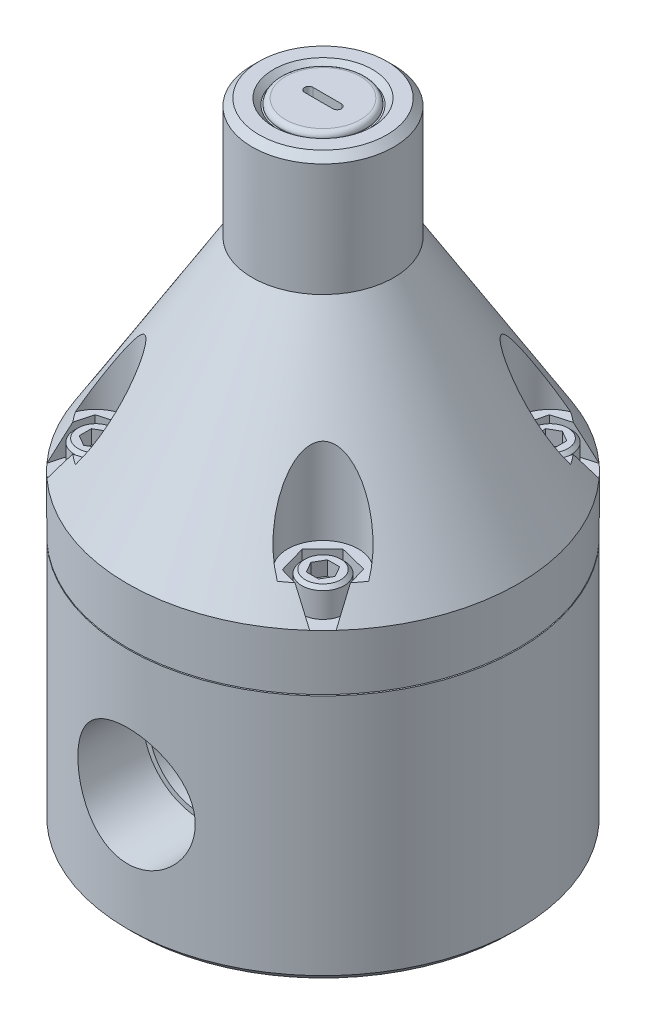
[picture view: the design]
ISO-10303-21;
HEADER;
FILE_DESCRIPTION(('STEP AP214'),'2;1');
FILE_NAME('part.step','',(''),(''),'','','');
FILE_SCHEMA(('AUTOMOTIVE_DESIGN { 1 0 10303 214 1 1 1 1 }'));
ENDSEC;
DATA;
#1=APPLICATION_CONTEXT('core data for automotive mechanical design processes');
#2=APPLICATION_PROTOCOL_DEFINITION('international standard','automotive_design',2000,#1);
#3=PRODUCT_CONTEXT('',#1,'mechanical');
#4=PRODUCT('Part','Part','',(#3));
#5=PRODUCT_RELATED_PRODUCT_CATEGORY('part','',(#4));
#6=PRODUCT_DEFINITION_FORMATION('','',#4);
#7=PRODUCT_DEFINITION_CONTEXT('part definition',#1,'design');
#8=PRODUCT_DEFINITION('design','',#6,#7);
#9=PRODUCT_DEFINITION_SHAPE('','',#8);
#10=(LENGTH_UNIT() NAMED_UNIT(*) SI_UNIT(.MILLI.,.METRE.));
#11=(NAMED_UNIT(*) PLANE_ANGLE_UNIT() SI_UNIT($,.RADIAN.));
#12=(NAMED_UNIT(*) SI_UNIT($,.STERADIAN.) SOLID_ANGLE_UNIT());
#13=UNCERTAINTY_MEASURE_WITH_UNIT(LENGTH_MEASURE(1.E-05),#10,'distance_accuracy_value','');
#14=(GEOMETRIC_REPRESENTATION_CONTEXT(3) GLOBAL_UNCERTAINTY_ASSIGNED_CONTEXT((#13)) GLOBAL_UNIT_ASSIGNED_CONTEXT((#10,
#11,#12)) REPRESENTATION_CONTEXT('',''));
#15=CARTESIAN_POINT('',(0.,0.,0.));
#16=DIRECTION('',(0.,0.,1.));
#17=DIRECTION('',(1.,0.,0.));
#18=AXIS2_PLACEMENT_3D('',#15,#16,#17);
#19=CARTESIAN_POINT('',(0.,68.58,0.));
#20=DIRECTION('',(0.,-1.,0.));
#21=DIRECTION('',(0.,0.,-1.));
#22=AXIS2_PLACEMENT_3D('',#19,#20,#21);
#23=CONICAL_SURFACE('',#22,43.815,0.551031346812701);
#24=CARTESIAN_POINT('',(31.1854504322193,74.9302,-24.909570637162));
#25=CARTESIAN_POINT('',(31.2917993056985,74.4052604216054,-25.2932994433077));
#26=CARTESIAN_POINT('',(31.3977224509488,73.8791142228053,-25.6754921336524));
#27=CARTESIAN_POINT('',(31.6087824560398,72.8246364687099,-26.4370404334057));
#28=CARTESIAN_POINT('',(31.713919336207,72.2963049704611,-26.8163961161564));
#29=CARTESIAN_POINT('',(31.9234771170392,71.2376591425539,-27.5725240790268));
#30=CARTESIAN_POINT('',(32.0278980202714,70.7073448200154,-27.9492963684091));
#31=CARTESIAN_POINT('',(32.2360838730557,69.6448927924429,-28.7004741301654));
#32=CARTESIAN_POINT('',(32.3398488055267,69.1127550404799,-29.0748795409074));
#33=CARTESIAN_POINT('',(32.443312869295,68.5798,-29.4481993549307));
#34=B_SPLINE_CURVE_WITH_KNOTS('',3,(#24,#25,#26,#27,#28,#29,#30,#31,#32,#33),.UNSPECIFIED.,.F.,
.F.,(4,2,2,2,4),(0.,1.97662629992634,3.95320132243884,5.9297692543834,7.90638844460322),.UNSPECIFIED.);
#35=CARTESIAN_POINT('',(31.1854909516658,74.93,-24.9097168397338));
#36=VERTEX_POINT('',#35);
#37=CARTESIAN_POINT('',(32.4432740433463,68.58,-29.4480592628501));
#38=VERTEX_POINT('',#37);
#39=EDGE_CURVE('E746',#36,#38,#34,.T.);
#40=ORIENTED_EDGE('',*,*,#39,.F.);
#41=CARTESIAN_POINT('',(0.,74.93,0.));
#42=DIRECTION('',(0.,1.,0.));
#43=DIRECTION('',(0.,0.,1.));
#44=AXIS2_PLACEMENT_3D('',#41,#42,#43);
#45=CIRCLE('',#44,39.9127653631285);
#46=CARTESIAN_POINT('',(32.8759602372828,74.93,-22.6318376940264));
#47=VERTEX_POINT('',#46);
#48=EDGE_CURVE('E1544',#36,#47,#45,.F.);
#49=ORIENTED_EDGE('',*,*,#48,.T.);
#50=CARTESIAN_POINT('',(32.8760134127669,74.9298,-22.6319772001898));
#51=CARTESIAN_POINT('',(32.8078201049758,75.1861952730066,-22.4531520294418));
#52=CARTESIAN_POINT('',(32.7341907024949,75.4445704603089,-22.2793275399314));
#53=CARTESIAN_POINT('',(32.5770087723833,75.9645959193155,-21.9414911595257));
#54=CARTESIAN_POINT('',(32.4934589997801,76.2262452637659,-21.7774765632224));
#55=CARTESIAN_POINT('',(32.3174500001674,76.7519681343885,-21.4591594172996));
#56=CARTESIAN_POINT('',(32.2250013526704,77.0160384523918,-21.3048456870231));
#57=CARTESIAN_POINT('',(32.0318436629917,77.5464258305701,-21.0055220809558));
#58=CARTESIAN_POINT('',(31.9311339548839,77.8127430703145,-20.8605129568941));
#59=CARTESIAN_POINT('',(31.6173532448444,78.6150033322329,-20.4388792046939));
#60=CARTESIAN_POINT('',(31.3928032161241,79.1537454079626,-20.1759549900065));
#61=CARTESIAN_POINT('',(30.9170512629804,80.2357477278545,-19.6857657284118));
#62=CARTESIAN_POINT('',(30.6658395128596,80.7790095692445,-19.458513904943));
#63=CARTESIAN_POINT('',(30.118158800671,81.9115352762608,-19.022517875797));
#64=CARTESIAN_POINT('',(29.8196739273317,82.5009764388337,-18.8167433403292));
#65=CARTESIAN_POINT('',(29.3524342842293,83.3846139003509,-18.5396319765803));
#66=CARTESIAN_POINT('',(29.1934054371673,83.6791250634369,-18.452507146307));
#67=CARTESIAN_POINT('',(28.8689346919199,84.2675878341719,-18.2889878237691));
#68=CARTESIAN_POINT('',(28.7034932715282,84.5615394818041,-18.2125925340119));
#69=CARTESIAN_POINT('',(28.3660149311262,85.1488284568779,-18.0707333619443));
#70=CARTESIAN_POINT('',(28.1939696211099,85.442164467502,-18.0052839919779));
#71=CARTESIAN_POINT('',(27.8434345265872,86.0273145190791,-17.885863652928));
#72=CARTESIAN_POINT('',(27.6649449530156,86.3191286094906,-17.8318923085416));
#73=CARTESIAN_POINT('',(27.3014619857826,86.9004622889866,-17.7360312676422));
#74=CARTESIAN_POINT('',(27.1164723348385,87.1899830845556,-17.6941347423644));
#75=CARTESIAN_POINT('',(26.7396312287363,87.7661102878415,-17.6231649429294));
#76=CARTESIAN_POINT('',(26.5477800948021,88.0527168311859,-17.5940910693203));
#77=CARTESIAN_POINT('',(26.1388486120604,88.6481794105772,-17.5477736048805));
#78=CARTESIAN_POINT('',(25.9210687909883,88.9566632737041,-17.531860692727));
#79=CARTESIAN_POINT('',(25.4761618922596,89.5671217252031,-17.5184250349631));
#80=CARTESIAN_POINT('',(25.2490377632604,89.8690983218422,-17.5208965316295));
#81=CARTESIAN_POINT('',(24.7853264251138,90.462861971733,-17.546770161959));
#82=CARTESIAN_POINT('',(24.5487844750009,90.7546875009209,-17.5700815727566));
#83=CARTESIAN_POINT('',(24.1854004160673,91.182662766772,-17.6234209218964));
#84=CARTESIAN_POINT('',(24.0628808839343,91.3236542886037,-17.6442539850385));
#85=CARTESIAN_POINT('',(23.8147710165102,91.6017141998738,-17.6926688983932));
#86=CARTESIAN_POINT('',(23.6891808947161,91.7387828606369,-17.7202502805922));
#87=CARTESIAN_POINT('',(23.3476505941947,92.1003741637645,-17.8043004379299));
#88=CARTESIAN_POINT('',(23.1286985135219,92.320550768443,-17.8676208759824));
#89=CARTESIAN_POINT('',(22.6802930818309,92.7420139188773,-18.0200246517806));
#90=CARTESIAN_POINT('',(22.450819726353,92.9432620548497,-18.1091589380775));
#91=CARTESIAN_POINT('',(22.0978320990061,93.2244666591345,-18.2671443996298));
#92=CARTESIAN_POINT('',(21.9777912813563,93.315346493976,-18.3243659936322));
#93=CARTESIAN_POINT('',(21.7355133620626,93.4877899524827,-18.4477596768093));
#94=CARTESIAN_POINT('',(21.6132758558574,93.5693518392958,-18.5139334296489));
#95=CARTESIAN_POINT('',(21.3676920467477,93.7206957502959,-18.6557254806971));
#96=CARTESIAN_POINT('',(21.2443516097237,93.7905207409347,-18.7313074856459));
#97=CARTESIAN_POINT('',(20.997270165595,93.9162293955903,-18.8925662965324));
#98=CARTESIAN_POINT('',(20.8735295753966,93.9721245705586,-18.9782346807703));
#99=CARTESIAN_POINT('',(20.596353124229,94.0793061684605,-19.1825009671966));
#100=CARTESIAN_POINT('',(20.4431915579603,94.1259831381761,-19.303987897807));
#101=CARTESIAN_POINT('',(20.1429486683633,94.1891665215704,-19.561379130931));
#102=CARTESIAN_POINT('',(19.995862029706,94.2056998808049,-19.6972704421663));
#103=CARTESIAN_POINT('',(19.7121854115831,94.2068511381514,-19.9801670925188));
#104=CARTESIAN_POINT('',(19.5756118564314,94.1914201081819,-20.1271891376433));
#105=CARTESIAN_POINT('',(19.3168358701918,94.130256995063,-20.4274436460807));
#106=CARTESIAN_POINT('',(19.1946462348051,94.0844981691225,-20.5806814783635));
#107=CARTESIAN_POINT('',(18.9333227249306,93.9499537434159,-20.9335168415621));
#108=CARTESIAN_POINT('',(18.7994959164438,93.8525556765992,-21.1337148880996));
#109=CARTESIAN_POINT('',(18.5575341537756,93.6253225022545,-21.5311982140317));
#110=CARTESIAN_POINT('',(18.4494578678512,93.4954146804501,-21.7284758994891));
#111=CARTESIAN_POINT('',(18.2734255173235,93.2378861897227,-22.0822323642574));
#112=CARTESIAN_POINT('',(18.2017503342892,93.114033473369,-22.2396830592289));
#113=CARTESIAN_POINT('',(18.0717731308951,92.8543658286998,-22.5502860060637));
#114=CARTESIAN_POINT('',(18.0134803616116,92.7185427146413,-22.7034352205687));
#115=CARTESIAN_POINT('',(17.9085459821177,92.4375711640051,-23.0055063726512));
#116=CARTESIAN_POINT('',(17.8619238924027,92.2924076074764,-23.1544208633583));
#117=CARTESIAN_POINT('',(17.7789950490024,91.9949331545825,-23.4479825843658));
#118=CARTESIAN_POINT('',(17.7426923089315,91.842619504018,-23.5926281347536));
#119=CARTESIAN_POINT('',(17.6793668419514,91.5330276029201,-23.877261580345));
#120=CARTESIAN_POINT('',(17.6523073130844,91.3757718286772,-24.0172658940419));
#121=CARTESIAN_POINT('',(17.6063247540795,91.0568516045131,-24.2934532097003));
#122=CARTESIAN_POINT('',(17.5874006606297,90.8951877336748,-24.4296367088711));
#123=CARTESIAN_POINT('',(17.5416007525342,90.4045581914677,-24.8331155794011));
#124=CARTESIAN_POINT('',(17.5257415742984,90.0701857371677,-25.0951300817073));
#125=CARTESIAN_POINT('',(17.5187750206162,89.3910127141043,-25.6073018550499));
#126=CARTESIAN_POINT('',(17.5277362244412,89.0461858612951,-25.8574243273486));
#127=CARTESIAN_POINT('',(17.5674604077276,88.3499543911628,-26.346266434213));
#128=CARTESIAN_POINT('',(17.5982177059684,87.9985515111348,-26.5849890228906));
#129=CARTESIAN_POINT('',(17.6752315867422,87.3273950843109,-27.0279886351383));
#130=CARTESIAN_POINT('',(17.7195760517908,87.0080899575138,-27.2332880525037));
#131=CARTESIAN_POINT('',(17.8230232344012,86.366765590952,-27.6358491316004));
#132=CARTESIAN_POINT('',(17.8821279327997,86.0447459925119,-27.8331097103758));
#133=CARTESIAN_POINT('',(18.0143479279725,85.3986613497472,-28.2199078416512));
#134=CARTESIAN_POINT('',(18.0874725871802,85.0745950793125,-28.4094401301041));
#135=CARTESIAN_POINT('',(18.247146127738,84.4253288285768,-28.7807004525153));
#136=CARTESIAN_POINT('',(18.3336943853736,84.100128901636,-28.9624288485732));
#137=CARTESIAN_POINT('',(18.5196821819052,83.4497138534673,-29.3177238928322));
#138=CARTESIAN_POINT('',(18.6190998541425,83.1244996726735,-29.4913037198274));
#139=CARTESIAN_POINT('',(18.8307065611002,82.4740292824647,-29.830436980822));
#140=CARTESIAN_POINT('',(18.9428959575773,82.1487730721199,-29.9959901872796));
#141=CARTESIAN_POINT('',(19.1798765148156,81.4988617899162,-30.3186806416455));
#142=CARTESIAN_POINT('',(19.3046623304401,81.1742065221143,-30.4758214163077));
#143=CARTESIAN_POINT('',(19.566846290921,80.5258852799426,-30.7813029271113));
#144=CARTESIAN_POINT('',(19.7042435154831,80.2022192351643,-30.929644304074));
#145=CARTESIAN_POINT('',(20.0356080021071,79.4577845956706,-31.2608218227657));
#146=CARTESIAN_POINT('',(20.2340425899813,79.0375277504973,-31.4403688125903));
#147=CARTESIAN_POINT('',(20.6528330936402,78.2009180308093,-31.7817933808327));
#148=CARTESIAN_POINT('',(20.8731810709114,77.7845638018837,-31.943677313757));
#149=CARTESIAN_POINT('',(21.2204706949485,77.1642648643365,-32.1715277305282));
#150=CARTESIAN_POINT('',(21.3389735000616,76.9582923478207,-32.244953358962));
#151=CARTESIAN_POINT('',(21.5816967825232,76.5479021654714,-32.3865049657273));
#152=CARTESIAN_POINT('',(21.7059169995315,76.3434844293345,-32.454631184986));
#153=CARTESIAN_POINT('',(21.9602864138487,75.936277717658,-32.5852592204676));
#154=CARTESIAN_POINT('',(22.0904406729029,75.7334903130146,-32.647756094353));
#155=CARTESIAN_POINT('',(22.3567119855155,75.3299985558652,-32.7666088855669));
#156=CARTESIAN_POINT('',(22.4928299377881,75.1292945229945,-32.8229638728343));
#157=CARTESIAN_POINT('',(22.6319772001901,74.9298,-32.8760134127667));
#158=B_SPLINE_CURVE_WITH_KNOTS('',3,(#50,#51,#52,#53,#54,#55,#56,#57,#58,#59,#60,#61,#62,#63,
#64,#65,#66,#67,#68,#69,#70,#71,#72,#73,#74,#75,#76,#77,#78,#79,#80,#81,#82,#83,#84,#85,#86,#87,
#88,#89,#90,#91,#92,#93,#94,#95,#96,#97,#98,#99,#100,#101,#102,#103,#104,#105,#106,#107,#108,
#109,#110,#111,#112,#113,#114,#115,#116,#117,#118,#119,#120,#121,#122,#123,#124,#125,#126,#127,
#128,#129,#130,#131,#132,#133,#134,#135,#136,#137,#138,#139,#140,#141,#142,#143,#144,#145,#146,
#147,#148,#149,#150,#151,#152,#153,#154,#155,#156,#157),.UNSPECIFIED.,.F.,.F.,(4,2,2,2,2,2,2,2,
2,2,2,2,2,2,2,2,2,2,2,2,2,2,2,2,2,2,2,2,2,2,2,2,2,2,2,2,2,2,2,2,2,2,2,2,2,2,2,2,2,2,2,2,2,4),
(0.,0.959681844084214,1.9190977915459,2.87738689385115,3.83575332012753,5.75433905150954,
7.67363431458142,9.74768208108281,10.7850777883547,11.8223963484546,12.8610794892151,
13.8997286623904,14.9377892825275,15.9758013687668,17.1090815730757,18.2420068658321,
19.3700240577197,19.9337037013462,20.4973442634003,21.4467185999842,22.3979796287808,
22.8807596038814,23.363629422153,23.8446911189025,24.3253539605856,24.9256472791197,
25.5254037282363,26.1260789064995,26.7272844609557,27.5022221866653,28.2789089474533,
28.9163059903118,29.5541423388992,30.193038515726,30.8321828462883,31.4687519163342,
32.1052377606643,33.3791509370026,34.6565874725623,35.9336911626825,37.0798743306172,
38.2262114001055,39.3733166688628,40.520368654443,41.665496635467,42.8106570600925,
43.9553335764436,45.0999266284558,46.5938371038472,48.0872083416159,48.8332472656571,
49.5792522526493,50.325905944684,51.0726725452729),.UNSPECIFIED.);
#159=CARTESIAN_POINT('',(22.6318376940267,74.93,-32.8759602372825));
#160=VERTEX_POINT('',#159);
#161=EDGE_CURVE('E897',#47,#160,#158,.T.);
#162=ORIENTED_EDGE('',*,*,#161,.T.);
#163=CARTESIAN_POINT('',(24.9752922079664,74.93,-31.1329988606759));
#164=VERTEX_POINT('',#163);
#165=EDGE_CURVE('E906',#160,#164,#45,.F.);
#166=ORIENTED_EDGE('',*,*,#165,.T.);
#167=CARTESIAN_POINT('',(29.4766640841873,68.5798,-32.4174531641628));
#168=CARTESIAN_POINT('',(29.1062316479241,69.1125841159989,-32.3117512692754));
#169=CARTESIAN_POINT('',(28.7347583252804,69.6445870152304,-32.2057523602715));
#170=CARTESIAN_POINT('',(27.9895431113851,70.7068520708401,-31.9931072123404));
#171=CARTESIAN_POINT('',(27.6158012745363,71.2371142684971,-31.8864609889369));
#172=CARTESIAN_POINT('',(26.8658433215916,72.2957468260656,-31.6724625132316));
#173=CARTESIAN_POINT('',(26.4896271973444,72.8241171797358,-31.5651102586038));
#174=CARTESIAN_POINT('',(25.7344797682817,73.8787747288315,-31.3496309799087));
#175=CARTESIAN_POINT('',(25.3555483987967,74.4050618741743,-31.2415039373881));
#176=CARTESIAN_POINT('',(24.9751473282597,74.9302,-31.132957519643));
#177=B_SPLINE_CURVE_WITH_KNOTS('',3,(#167,#168,#169,#170,#171,#172,#173,#174,#175,#176),
.UNSPECIFIED.,.F.,.F.,(4,2,2,2,4),(0.,1.97237650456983,3.9447058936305,5.91704178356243,
7.88942480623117),.UNSPECIFIED.);
#178=CARTESIAN_POINT('',(29.4765250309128,68.58,-32.4174134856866));
#179=VERTEX_POINT('',#178);
#180=EDGE_CURVE('E729',#179,#164,#177,.T.);
#181=ORIENTED_EDGE('',*,*,#180,.F.);
#182=CARTESIAN_POINT('',(0.,68.58,0.));
#183=DIRECTION('',(0.,-1.,0.));
#184=DIRECTION('',(0.,0.,-1.));
#185=AXIS2_PLACEMENT_3D('',#182,#183,#184);
#186=CIRCLE('',#185,43.815);
#187=CARTESIAN_POINT('',(-29.4480592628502,68.58,-32.4432740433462));
#188=VERTEX_POINT('',#187);
#189=EDGE_CURVE('E1308',#188,#179,#186,.T.);
#190=ORIENTED_EDGE('',*,*,#189,.F.);
#191=CARTESIAN_POINT('',(-24.9095706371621,74.9302,-31.1854504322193));
#192=CARTESIAN_POINT('',(-25.2932994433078,74.4052604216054,-31.2917993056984));
#193=CARTESIAN_POINT('',(-25.6754921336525,73.8791142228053,-31.3977224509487));
#194=CARTESIAN_POINT('',(-26.4370404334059,72.8246364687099,-31.6087824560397));
#195=CARTESIAN_POINT('',(-26.8163961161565,72.2963049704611,-31.7139193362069));
#196=CARTESIAN_POINT('',(-27.5725240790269,71.2376591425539,-31.9234771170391));
#197=CARTESIAN_POINT('',(-27.9492963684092,70.7073448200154,-32.0278980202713));
#198=CARTESIAN_POINT('',(-28.7004741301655,69.6448927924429,-32.2360838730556));
#199=CARTESIAN_POINT('',(-29.0748795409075,69.1127550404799,-32.3398488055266));
#200=CARTESIAN_POINT('',(-29.4481993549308,68.5798,-32.4433128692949));
#201=B_SPLINE_CURVE_WITH_KNOTS('',3,(#191,#192,#193,#194,#195,#196,#197,#198,#199,#200),
.UNSPECIFIED.,.F.,.F.,(4,2,2,2,4),(0.,1.97662629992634,3.95320132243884,5.9297692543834,
7.90638844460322),.UNSPECIFIED.);
#202=CARTESIAN_POINT('',(-24.9097168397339,74.93,-31.1854909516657));
#203=VERTEX_POINT('',#202);
#204=EDGE_CURVE('E803',#203,#188,#201,.T.);
#205=ORIENTED_EDGE('',*,*,#204,.F.);
#206=CARTESIAN_POINT('',(0.,74.93,0.));
#207=DIRECTION('',(0.,1.,0.));
#208=DIRECTION('',(0.,0.,1.));
#209=AXIS2_PLACEMENT_3D('',#206,#207,#208);
#210=CIRCLE('',#209,39.9127653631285);
#211=CARTESIAN_POINT('',(-22.6318376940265,74.93,-32.8759602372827));
#212=VERTEX_POINT('',#211);
#213=EDGE_CURVE('E1676',#203,#212,#210,.F.);
#214=ORIENTED_EDGE('',*,*,#213,.T.);
#215=CARTESIAN_POINT('',(-22.6319772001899,74.9298,-32.8760134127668));
#216=CARTESIAN_POINT('',(-22.4531520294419,75.1861952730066,-32.8078201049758));
#217=CARTESIAN_POINT('',(-22.2793275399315,75.4445704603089,-32.7341907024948));
#218=CARTESIAN_POINT('',(-21.9414911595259,75.9645959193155,-32.5770087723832));
#219=CARTESIAN_POINT('',(-21.7774765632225,76.2262452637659,-32.49345899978));
#220=CARTESIAN_POINT('',(-21.4591594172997,76.7519681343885,-32.3174500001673));
#221=CARTESIAN_POINT('',(-21.3048456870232,77.0160384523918,-32.2250013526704));
#222=CARTESIAN_POINT('',(-21.0055220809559,77.5464258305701,-32.0318436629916));
#223=CARTESIAN_POINT('',(-20.8605129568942,77.8127430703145,-31.9311339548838));
#224=CARTESIAN_POINT('',(-20.438879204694,78.6150033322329,-31.6173532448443));
#225=CARTESIAN_POINT('',(-20.1759549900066,79.1537454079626,-31.392803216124));
#226=CARTESIAN_POINT('',(-19.6857657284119,80.2357477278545,-30.9170512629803));
#227=CARTESIAN_POINT('',(-19.4585139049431,80.7790095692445,-30.6658395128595));
#228=CARTESIAN_POINT('',(-19.0225178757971,81.9115352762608,-30.1181588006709));
#229=CARTESIAN_POINT('',(-18.8167433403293,82.5009764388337,-29.8196739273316));
#230=CARTESIAN_POINT('',(-18.5396319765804,83.3846139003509,-29.3524342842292));
#231=CARTESIAN_POINT('',(-18.4525071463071,83.6791250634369,-29.1934054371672));
#232=CARTESIAN_POINT('',(-18.2889878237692,84.2675878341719,-28.8689346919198));
#233=CARTESIAN_POINT('',(-18.212592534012,84.5615394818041,-28.7034932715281));
#234=CARTESIAN_POINT('',(-18.0707333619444,85.148828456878,-28.3660149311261));
#235=CARTESIAN_POINT('',(-18.005283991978,85.4421644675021,-28.1939696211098));
#236=CARTESIAN_POINT('',(-17.8858636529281,86.0273145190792,-27.8434345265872));
#237=CARTESIAN_POINT('',(-17.8318923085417,86.3191286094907,-27.6649449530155));
#238=CARTESIAN_POINT('',(-17.7360312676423,86.9004622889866,-27.3014619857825));
#239=CARTESIAN_POINT('',(-17.6941347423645,87.1899830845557,-27.1164723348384));
#240=CARTESIAN_POINT('',(-17.6231649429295,87.7661102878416,-26.7396312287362));
#241=CARTESIAN_POINT('',(-17.5940910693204,88.052716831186,-26.547780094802));
#242=CARTESIAN_POINT('',(-17.5477736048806,88.6481794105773,-26.1388486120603));
#243=CARTESIAN_POINT('',(-17.5318606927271,88.9566632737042,-25.9210687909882));
#244=CARTESIAN_POINT('',(-17.5184250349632,89.5671217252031,-25.4761618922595));
#245=CARTESIAN_POINT('',(-17.5208965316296,89.8690983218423,-25.2490377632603));
#246=CARTESIAN_POINT('',(-17.5467701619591,90.462861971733,-24.7853264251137));
#247=CARTESIAN_POINT('',(-17.5700815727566,90.754687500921,-24.5487844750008));
#248=CARTESIAN_POINT('',(-17.6234209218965,91.1826627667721,-24.1854004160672));
#249=CARTESIAN_POINT('',(-17.6442539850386,91.3236542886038,-24.0628808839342));
#250=CARTESIAN_POINT('',(-17.6926688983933,91.6017141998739,-23.8147710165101));
#251=CARTESIAN_POINT('',(-17.7202502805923,91.7387828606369,-23.6891808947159));
#252=CARTESIAN_POINT('',(-17.80430043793,92.1003741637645,-23.3476505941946));
#253=CARTESIAN_POINT('',(-17.8676208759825,92.320550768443,-23.1286985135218));
#254=CARTESIAN_POINT('',(-18.0200246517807,92.7420139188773,-22.6802930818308));
#255=CARTESIAN_POINT('',(-18.1091589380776,92.9432620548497,-22.4508197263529));
#256=CARTESIAN_POINT('',(-18.2671443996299,93.2244666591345,-22.097832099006));
#257=CARTESIAN_POINT('',(-18.3243659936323,93.3153464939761,-21.9777912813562));
#258=CARTESIAN_POINT('',(-18.4477596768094,93.4877899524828,-21.7355133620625));
#259=CARTESIAN_POINT('',(-18.513933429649,93.5693518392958,-21.6132758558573));
#260=CARTESIAN_POINT('',(-18.6557254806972,93.7206957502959,-21.3676920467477));
#261=CARTESIAN_POINT('',(-18.731307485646,93.7905207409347,-21.2443516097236));
#262=CARTESIAN_POINT('',(-18.8925662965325,93.9162293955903,-20.9972701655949));
#263=CARTESIAN_POINT('',(-18.9782346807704,93.9721245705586,-20.8735295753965));
#264=CARTESIAN_POINT('',(-19.1825009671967,94.0793061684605,-20.5963531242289));
#265=CARTESIAN_POINT('',(-19.3039878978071,94.1259831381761,-20.4431915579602));
#266=CARTESIAN_POINT('',(-19.5613791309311,94.1891665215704,-20.1429486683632));
#267=CARTESIAN_POINT('',(-19.6972704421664,94.2056998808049,-19.9958620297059));
#268=CARTESIAN_POINT('',(-19.9801670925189,94.2068511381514,-19.7121854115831));
#269=CARTESIAN_POINT('',(-20.1271891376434,94.1914201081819,-19.5756118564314));
#270=CARTESIAN_POINT('',(-20.4274436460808,94.130256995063,-19.3168358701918));
#271=CARTESIAN_POINT('',(-20.5806814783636,94.0844981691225,-19.194646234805));
#272=CARTESIAN_POINT('',(-20.9335168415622,93.9499537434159,-18.9333227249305));
#273=CARTESIAN_POINT('',(-21.1337148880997,93.8525556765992,-18.7994959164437));
#274=CARTESIAN_POINT('',(-21.5311982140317,93.6253225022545,-18.5575341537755));
#275=CARTESIAN_POINT('',(-21.7284758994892,93.4954146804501,-18.4494578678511));
#276=CARTESIAN_POINT('',(-22.0822323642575,93.2378861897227,-18.2734255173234));
#277=CARTESIAN_POINT('',(-22.239683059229,93.114033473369,-18.2017503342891));
#278=CARTESIAN_POINT('',(-22.5502860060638,92.8543658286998,-18.071773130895));
#279=CARTESIAN_POINT('',(-22.7034352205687,92.7185427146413,-18.0134803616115));
#280=CARTESIAN_POINT('',(-23.0055063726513,92.437571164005,-17.9085459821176));
#281=CARTESIAN_POINT('',(-23.1544208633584,92.2924076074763,-17.8619238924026));
#282=CARTESIAN_POINT('',(-23.4479825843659,91.9949331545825,-17.7789950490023));
#283=CARTESIAN_POINT('',(-23.5926281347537,91.842619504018,-17.7426923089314));
#284=CARTESIAN_POINT('',(-23.8772615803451,91.5330276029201,-17.6793668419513));
#285=CARTESIAN_POINT('',(-24.017265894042,91.3757718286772,-17.6523073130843));
#286=CARTESIAN_POINT('',(-24.2934532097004,91.0568516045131,-17.6063247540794));
#287=CARTESIAN_POINT('',(-24.4296367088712,90.8951877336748,-17.5874006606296));
#288=CARTESIAN_POINT('',(-24.8331155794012,90.4045581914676,-17.5416007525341));
#289=CARTESIAN_POINT('',(-25.0951300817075,90.0701857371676,-17.5257415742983));
#290=CARTESIAN_POINT('',(-25.60730185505,89.3910127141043,-17.5187750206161));
#291=CARTESIAN_POINT('',(-25.8574243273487,89.046185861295,-17.5277362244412));
#292=CARTESIAN_POINT('',(-26.3462664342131,88.3499543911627,-17.5674604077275));
#293=CARTESIAN_POINT('',(-26.5849890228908,87.9985515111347,-17.5982177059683));
#294=CARTESIAN_POINT('',(-27.0279886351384,87.3273950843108,-17.6752315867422));
#295=CARTESIAN_POINT('',(-27.2332880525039,87.0080899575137,-17.7195760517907));
#296=CARTESIAN_POINT('',(-27.6358491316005,86.366765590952,-17.8230232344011));
#297=CARTESIAN_POINT('',(-27.8331097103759,86.0447459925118,-17.8821279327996));
#298=CARTESIAN_POINT('',(-28.2199078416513,85.3986613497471,-18.0143479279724));
#299=CARTESIAN_POINT('',(-28.4094401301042,85.0745950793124,-18.0874725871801));
#300=CARTESIAN_POINT('',(-28.7807004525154,84.4253288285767,-18.2471461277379));
#301=CARTESIAN_POINT('',(-28.9624288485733,84.1001289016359,-18.3336943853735));
#302=CARTESIAN_POINT('',(-29.3177238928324,83.4497138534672,-18.5196821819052));
#303=CARTESIAN_POINT('',(-29.4913037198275,83.1244996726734,-18.6190998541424));
#304=CARTESIAN_POINT('',(-29.8304369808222,82.4740292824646,-18.8307065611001));
#305=CARTESIAN_POINT('',(-29.9959901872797,82.1487730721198,-18.9428959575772));
#306=CARTESIAN_POINT('',(-30.3186806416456,81.498861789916,-19.1798765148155));
#307=CARTESIAN_POINT('',(-30.4758214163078,81.1742065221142,-19.3046623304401));
#308=CARTESIAN_POINT('',(-30.7813029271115,80.5258852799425,-19.5668462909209));
#309=CARTESIAN_POINT('',(-30.9296443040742,80.2022192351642,-19.7042435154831));
#310=CARTESIAN_POINT('',(-31.2608218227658,79.4577845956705,-20.0356080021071));
#311=CARTESIAN_POINT('',(-31.4403688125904,79.0375277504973,-20.2340425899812));
#312=CARTESIAN_POINT('',(-31.7817933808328,78.2009180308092,-20.6528330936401));
#313=CARTESIAN_POINT('',(-31.9436773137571,77.7845638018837,-20.8731810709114));
#314=CARTESIAN_POINT('',(-32.1715277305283,77.1642648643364,-21.2204706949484));
#315=CARTESIAN_POINT('',(-32.2449533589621,76.9582923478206,-21.3389735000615));
#316=CARTESIAN_POINT('',(-32.3865049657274,76.5479021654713,-21.5816967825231));
#317=CARTESIAN_POINT('',(-32.4546311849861,76.3434844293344,-21.7059169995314));
#318=CARTESIAN_POINT('',(-32.5852592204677,75.9362777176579,-21.9602864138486));
#319=CARTESIAN_POINT('',(-32.6477560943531,75.7334903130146,-22.0904406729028));
#320=CARTESIAN_POINT('',(-32.766608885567,75.3299985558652,-22.3567119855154));
#321=CARTESIAN_POINT('',(-32.8229638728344,75.1292945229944,-22.492829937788));
#322=CARTESIAN_POINT('',(-32.8760134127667,74.9298,-22.63197720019));
#323=B_SPLINE_CURVE_WITH_KNOTS('',3,(#215,#216,#217,#218,#219,#220,#221,#222,#223,#224,#225,
#226,#227,#228,#229,#230,#231,#232,#233,#234,#235,#236,#237,#238,#239,#240,#241,#242,#243,#244,
#245,#246,#247,#248,#249,#250,#251,#252,#253,#254,#255,#256,#257,#258,#259,#260,#261,#262,#263,
#264,#265,#266,#267,#268,#269,#270,#271,#272,#273,#274,#275,#276,#277,#278,#279,#280,#281,#282,
#283,#284,#285,#286,#287,#288,#289,#290,#291,#292,#293,#294,#295,#296,#297,#298,#299,#300,#301,
#302,#303,#304,#305,#306,#307,#308,#309,#310,#311,#312,#313,#314,#315,#316,#317,#318,#319,#320,
#321,#322),.UNSPECIFIED.,.F.,.F.,(4,2,2,2,2,2,2,2,2,2,2,2,2,2,2,2,2,2,2,2,2,2,2,2,2,2,2,2,2,2,2,
2,2,2,2,2,2,2,2,2,2,2,2,2,2,2,2,2,2,2,2,2,2,4),(0.,0.959681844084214,1.9190977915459,
2.87738689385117,3.83575332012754,5.75433905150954,7.67363431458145,9.74768208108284,
10.7850777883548,11.8223963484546,12.8610794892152,13.8997286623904,14.9377892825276,
15.9758013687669,17.1090815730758,18.2420068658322,19.3700240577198,19.9337037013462,
20.4973442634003,21.4467185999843,22.3979796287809,22.8807596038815,23.3636294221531,
23.8446911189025,24.3253539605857,24.9256472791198,25.5254037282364,26.1260789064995,
26.7272844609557,27.5022221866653,28.2789089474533,28.9163059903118,29.5541423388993,
30.193038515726,30.8321828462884,31.4687519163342,32.1052377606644,33.3791509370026,
34.6565874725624,35.9336911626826,37.0798743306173,38.2262114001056,39.373316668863,
40.5203686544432,41.6654966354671,42.8106570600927,43.9553335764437,45.0999266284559,
46.5938371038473,48.0872083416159,48.8332472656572,49.5792522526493,50.3259059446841,
51.0726725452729),.UNSPECIFIED.);
#324=CARTESIAN_POINT('',(-32.8759602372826,74.93,-22.6318376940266));
#325=VERTEX_POINT('',#324);
#326=EDGE_CURVE('E1545',#212,#325,#323,.T.);
#327=ORIENTED_EDGE('',*,*,#326,.T.);
#328=CARTESIAN_POINT('',(-31.132998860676,74.93,-24.9752922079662));
#329=VERTEX_POINT('',#328);
#330=EDGE_CURVE('E1359',#325,#329,#210,.F.);
#331=ORIENTED_EDGE('',*,*,#330,.T.);
#332=CARTESIAN_POINT('',(-32.4174531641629,68.5798,-29.4766640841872));
#333=CARTESIAN_POINT('',(-32.3117512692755,69.1125841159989,-29.106231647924));
#334=CARTESIAN_POINT('',(-32.2057523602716,69.6445870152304,-28.7347583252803));
#335=CARTESIAN_POINT('',(-31.9931072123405,70.7068520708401,-27.989543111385));
#336=CARTESIAN_POINT('',(-31.886460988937,71.2371142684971,-27.6158012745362));
#337=CARTESIAN_POINT('',(-31.6724625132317,72.2957468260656,-26.8658433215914));
#338=CARTESIAN_POINT('',(-31.5651102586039,72.8241171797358,-26.4896271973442));
#339=CARTESIAN_POINT('',(-31.3496309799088,73.8787747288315,-25.7344797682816));
#340=CARTESIAN_POINT('',(-31.2415039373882,74.4050618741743,-25.3555483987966));
#341=CARTESIAN_POINT('',(-31.1329575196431,74.9302,-24.9751473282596));
#342=B_SPLINE_CURVE_WITH_KNOTS('',3,(#332,#333,#334,#335,#336,#337,#338,#339,#340,#341),
.UNSPECIFIED.,.F.,.F.,(4,2,2,2,4),(0.,1.9723765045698,3.94470589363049,5.91704178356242,
7.88942480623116),.UNSPECIFIED.);
#343=CARTESIAN_POINT('',(-32.4174134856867,68.58,-29.4765250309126));
#344=VERTEX_POINT('',#343);
#345=EDGE_CURVE('E796',#344,#329,#342,.T.);
#346=ORIENTED_EDGE('',*,*,#345,.F.);
#347=CARTESIAN_POINT('',(-32.4432740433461,68.58,29.4480592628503));
#348=VERTEX_POINT('',#347);
#349=EDGE_CURVE('E1315',#348,#344,#186,.T.);
#350=ORIENTED_EDGE('',*,*,#349,.F.);
#351=CARTESIAN_POINT('',(-31.1854504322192,74.9302,24.9095706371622));
#352=CARTESIAN_POINT('',(-31.2917993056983,74.4052604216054,25.2932994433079));
#353=CARTESIAN_POINT('',(-31.3977224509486,73.8791142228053,25.6754921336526));
#354=CARTESIAN_POINT('',(-31.6087824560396,72.8246364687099,26.437040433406));
#355=CARTESIAN_POINT('',(-31.7139193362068,72.2963049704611,26.8163961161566));
#356=CARTESIAN_POINT('',(-31.9234771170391,71.2376591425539,27.572524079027));
#357=CARTESIAN_POINT('',(-32.0278980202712,70.7073448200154,27.9492963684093));
#358=CARTESIAN_POINT('',(-32.2360838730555,69.6448927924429,28.7004741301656));
#359=CARTESIAN_POINT('',(-32.3398488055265,69.1127550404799,29.0748795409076));
#360=CARTESIAN_POINT('',(-32.4433128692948,68.5798,29.4481993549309));
#361=B_SPLINE_CURVE_WITH_KNOTS('',3,(#351,#352,#353,#354,#355,#356,#357,#358,#359,#360),
.UNSPECIFIED.,.F.,.F.,(4,2,2,2,4),(0.,1.97662629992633,3.95320132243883,5.9297692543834,
7.90638844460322),.UNSPECIFIED.);
#362=CARTESIAN_POINT('',(-31.1854909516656,74.93,24.9097168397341));
#363=VERTEX_POINT('',#362);
#364=EDGE_CURVE('E866',#363,#348,#361,.T.);
#365=ORIENTED_EDGE('',*,*,#364,.F.);
#366=CARTESIAN_POINT('',(0.,74.93,0.));
#367=DIRECTION('',(0.,1.,0.));
#368=DIRECTION('',(0.,0.,1.));
#369=AXIS2_PLACEMENT_3D('',#366,#367,#368);
#370=CIRCLE('',#369,39.9127653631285);
#371=CARTESIAN_POINT('',(-32.8759602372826,74.93,22.6318376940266));
#372=VERTEX_POINT('',#371);
#373=EDGE_CURVE('E1673',#363,#372,#370,.F.);
#374=ORIENTED_EDGE('',*,*,#373,.T.);
#375=CARTESIAN_POINT('',(-32.8760134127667,74.9298,22.63197720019));
#376=CARTESIAN_POINT('',(-32.8078201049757,75.1861952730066,22.453152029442));
#377=CARTESIAN_POINT('',(-32.7341907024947,75.4445704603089,22.2793275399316));
#378=CARTESIAN_POINT('',(-32.5770087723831,75.9645959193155,21.941491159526));
#379=CARTESIAN_POINT('',(-32.4934589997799,76.2262452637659,21.7774765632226));
#380=CARTESIAN_POINT('',(-32.3174500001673,76.7519681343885,21.4591594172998));
#381=CARTESIAN_POINT('',(-32.2250013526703,77.0160384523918,21.3048456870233));
#382=CARTESIAN_POINT('',(-32.0318436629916,77.5464258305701,21.005522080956));
#383=CARTESIAN_POINT('',(-31.9311339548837,77.8127430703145,20.8605129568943));
#384=CARTESIAN_POINT('',(-31.6173532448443,78.6150033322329,20.4388792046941));
#385=CARTESIAN_POINT('',(-31.3928032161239,79.1537454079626,20.1759549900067));
#386=CARTESIAN_POINT('',(-30.9170512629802,80.2357477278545,19.685765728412));
#387=CARTESIAN_POINT('',(-30.6658395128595,80.7790095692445,19.4585139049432));
#388=CARTESIAN_POINT('',(-30.1181588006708,81.9115352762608,19.0225178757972));
#389=CARTESIAN_POINT('',(-29.8196739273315,82.5009764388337,18.8167433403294));
#390=CARTESIAN_POINT('',(-29.3524342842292,83.3846139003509,18.5396319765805));
#391=CARTESIAN_POINT('',(-29.1934054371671,83.6791250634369,18.4525071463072));
#392=CARTESIAN_POINT('',(-28.8689346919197,84.2675878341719,18.2889878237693));
#393=CARTESIAN_POINT('',(-28.703493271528,84.5615394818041,18.2125925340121));
#394=CARTESIAN_POINT('',(-28.3660149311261,85.1488284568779,18.0707333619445));
#395=CARTESIAN_POINT('',(-28.1939696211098,85.442164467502,18.0052839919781));
#396=CARTESIAN_POINT('',(-27.8434345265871,86.0273145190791,17.8858636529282));
#397=CARTESIAN_POINT('',(-27.6649449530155,86.3191286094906,17.8318923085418));
#398=CARTESIAN_POINT('',(-27.3014619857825,86.9004622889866,17.7360312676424));
#399=CARTESIAN_POINT('',(-27.1164723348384,87.1899830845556,17.6941347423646));
#400=CARTESIAN_POINT('',(-26.7396312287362,87.7661102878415,17.6231649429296));
#401=CARTESIAN_POINT('',(-26.5477800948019,88.0527168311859,17.5940910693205));
#402=CARTESIAN_POINT('',(-26.1388486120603,88.6481794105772,17.5477736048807));
#403=CARTESIAN_POINT('',(-25.9210687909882,88.9566632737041,17.5318606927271));
#404=CARTESIAN_POINT('',(-25.4761618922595,89.5671217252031,17.5184250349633));
#405=CARTESIAN_POINT('',(-25.2490377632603,89.8690983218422,17.5208965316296));
#406=CARTESIAN_POINT('',(-24.7853264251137,90.462861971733,17.5467701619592));
#407=CARTESIAN_POINT('',(-24.5487844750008,90.7546875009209,17.5700815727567));
#408=CARTESIAN_POINT('',(-24.1854004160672,91.1826627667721,17.6234209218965));
#409=CARTESIAN_POINT('',(-24.0628808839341,91.3236542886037,17.6442539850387));
#410=CARTESIAN_POINT('',(-23.8147710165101,91.6017141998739,17.6926688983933));
#411=CARTESIAN_POINT('',(-23.6891808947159,91.7387828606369,17.7202502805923));
#412=CARTESIAN_POINT('',(-23.3476505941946,92.1003741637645,17.80430043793));
#413=CARTESIAN_POINT('',(-23.1286985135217,92.320550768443,17.8676208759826));
#414=CARTESIAN_POINT('',(-22.6802930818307,92.7420139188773,18.0200246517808));
#415=CARTESIAN_POINT('',(-22.4508197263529,92.9432620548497,18.1091589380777));
#416=CARTESIAN_POINT('',(-22.0978320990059,93.2244666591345,18.2671443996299));
#417=CARTESIAN_POINT('',(-21.9777912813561,93.315346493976,18.3243659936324));
#418=CARTESIAN_POINT('',(-21.7355133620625,93.4877899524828,18.4477596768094));
#419=CARTESIAN_POINT('',(-21.6132758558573,93.5693518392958,18.5139334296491));
#420=CARTESIAN_POINT('',(-21.3676920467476,93.7206957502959,18.6557254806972));
#421=CARTESIAN_POINT('',(-21.2443516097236,93.7905207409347,18.7313074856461));
#422=CARTESIAN_POINT('',(-20.9972701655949,93.9162293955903,18.8925662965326));
#423=CARTESIAN_POINT('',(-20.8735295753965,93.9721245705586,18.9782346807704));
#424=CARTESIAN_POINT('',(-20.5963531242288,94.0793061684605,19.1825009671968));
#425=CARTESIAN_POINT('',(-20.4431915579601,94.1259831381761,19.3039878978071));
#426=CARTESIAN_POINT('',(-20.1429486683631,94.1891665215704,19.5613791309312));
#427=CARTESIAN_POINT('',(-19.9958620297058,94.2056998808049,19.6972704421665));
#428=CARTESIAN_POINT('',(-19.712185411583,94.2068511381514,19.980167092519));
#429=CARTESIAN_POINT('',(-19.5756118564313,94.1914201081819,20.1271891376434));
#430=CARTESIAN_POINT('',(-19.3168358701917,94.130256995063,20.4274436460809));
#431=CARTESIAN_POINT('',(-19.194646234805,94.0844981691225,20.5806814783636));
#432=CARTESIAN_POINT('',(-18.9333227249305,93.9499537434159,20.9335168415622));
#433=CARTESIAN_POINT('',(-18.7994959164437,93.8525556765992,21.1337148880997));
#434=CARTESIAN_POINT('',(-18.5575341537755,93.6253225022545,21.5311982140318));
#435=CARTESIAN_POINT('',(-18.449457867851,93.4954146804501,21.7284758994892));
#436=CARTESIAN_POINT('',(-18.2734255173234,93.2378861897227,22.0822323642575));
#437=CARTESIAN_POINT('',(-18.201750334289,93.114033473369,22.239683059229));
#438=CARTESIAN_POINT('',(-18.0717731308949,92.8543658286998,22.5502860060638));
#439=CARTESIAN_POINT('',(-18.0134803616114,92.7185427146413,22.7034352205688));
#440=CARTESIAN_POINT('',(-17.9085459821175,92.4375711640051,23.0055063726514));
#441=CARTESIAN_POINT('',(-17.8619238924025,92.2924076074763,23.1544208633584));
#442=CARTESIAN_POINT('',(-17.7789950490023,91.9949331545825,23.447982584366));
#443=CARTESIAN_POINT('',(-17.7426923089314,91.842619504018,23.5926281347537));
#444=CARTESIAN_POINT('',(-17.6793668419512,91.5330276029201,23.8772615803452));
#445=CARTESIAN_POINT('',(-17.6523073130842,91.3757718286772,24.017265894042));
#446=CARTESIAN_POINT('',(-17.6063247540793,91.0568516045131,24.2934532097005));
#447=CARTESIAN_POINT('',(-17.5874006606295,90.8951877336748,24.4296367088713));
#448=CARTESIAN_POINT('',(-17.541600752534,90.4045581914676,24.8331155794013));
#449=CARTESIAN_POINT('',(-17.5257415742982,90.0701857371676,25.0951300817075));
#450=CARTESIAN_POINT('',(-17.518775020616,89.3910127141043,25.6073018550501));
#451=CARTESIAN_POINT('',(-17.5277362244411,89.046185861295,25.8574243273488));
#452=CARTESIAN_POINT('',(-17.5674604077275,88.3499543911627,26.3462664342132));
#453=CARTESIAN_POINT('',(-17.5982177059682,87.9985515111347,26.5849890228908));
#454=CARTESIAN_POINT('',(-17.6752315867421,87.3273950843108,27.0279886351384));
#455=CARTESIAN_POINT('',(-17.7195760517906,87.0080899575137,27.2332880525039));
#456=CARTESIAN_POINT('',(-17.823023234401,86.366765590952,27.6358491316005));
#457=CARTESIAN_POINT('',(-17.8821279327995,86.0447459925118,27.833109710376));
#458=CARTESIAN_POINT('',(-18.0143479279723,85.3986613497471,28.2199078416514));
#459=CARTESIAN_POINT('',(-18.08747258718,85.0745950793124,28.4094401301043));
#460=CARTESIAN_POINT('',(-18.2471461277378,84.4253288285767,28.7807004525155));
#461=CARTESIAN_POINT('',(-18.3336943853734,84.1001289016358,28.9624288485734));
#462=CARTESIAN_POINT('',(-18.5196821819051,83.4497138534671,29.3177238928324));
#463=CARTESIAN_POINT('',(-18.6190998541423,83.1244996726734,29.4913037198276));
#464=CARTESIAN_POINT('',(-18.8307065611,82.4740292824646,29.8304369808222));
#465=CARTESIAN_POINT('',(-18.9428959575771,82.1487730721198,29.9959901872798));
#466=CARTESIAN_POINT('',(-19.1798765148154,81.498861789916,30.3186806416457));
#467=CARTESIAN_POINT('',(-19.30466233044,81.1742065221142,30.4758214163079));
#468=CARTESIAN_POINT('',(-19.5668462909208,80.5258852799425,30.7813029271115));
#469=CARTESIAN_POINT('',(-19.704243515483,80.2022192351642,30.9296443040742));
#470=CARTESIAN_POINT('',(-20.035608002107,79.4577845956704,31.2608218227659));
#471=CARTESIAN_POINT('',(-20.2340425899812,79.0375277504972,31.4403688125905));
#472=CARTESIAN_POINT('',(-20.65283309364,78.2009180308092,31.7817933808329));
#473=CARTESIAN_POINT('',(-20.8731810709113,77.7845638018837,31.9436773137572));
#474=CARTESIAN_POINT('',(-21.2204706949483,77.1642648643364,32.1715277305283));
#475=CARTESIAN_POINT('',(-21.3389735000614,76.9582923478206,32.2449533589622));
#476=CARTESIAN_POINT('',(-21.581696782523,76.5479021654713,32.3865049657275));
#477=CARTESIAN_POINT('',(-21.7059169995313,76.3434844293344,32.4546311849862));
#478=CARTESIAN_POINT('',(-21.9602864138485,75.9362777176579,32.5852592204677));
#479=CARTESIAN_POINT('',(-22.0904406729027,75.7334903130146,32.6477560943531));
#480=CARTESIAN_POINT('',(-22.3567119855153,75.3299985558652,32.7666088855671));
#481=CARTESIAN_POINT('',(-22.4928299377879,75.1292945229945,32.8229638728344));
#482=CARTESIAN_POINT('',(-22.6319772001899,74.9298,32.8760134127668));
#483=B_SPLINE_CURVE_WITH_KNOTS('',3,(#375,#376,#377,#378,#379,#380,#381,#382,#383,#384,#385,
#386,#387,#388,#389,#390,#391,#392,#393,#394,#395,#396,#397,#398,#399,#400,#401,#402,#403,#404,
#405,#406,#407,#408,#409,#410,#411,#412,#413,#414,#415,#416,#417,#418,#419,#420,#421,#422,#423,
#424,#425,#426,#427,#428,#429,#430,#431,#432,#433,#434,#435,#436,#437,#438,#439,#440,#441,#442,
#443,#444,#445,#446,#447,#448,#449,#450,#451,#452,#453,#454,#455,#456,#457,#458,#459,#460,#461,
#462,#463,#464,#465,#466,#467,#468,#469,#470,#471,#472,#473,#474,#475,#476,#477,#478,#479,#480,
#481,#482),.UNSPECIFIED.,.F.,.F.,(4,2,2,2,2,2,2,2,2,2,2,2,2,2,2,2,2,2,2,2,2,2,2,2,2,2,2,2,2,2,2,
2,2,2,2,2,2,2,2,2,2,2,2,2,2,2,2,2,2,2,2,2,2,4),(0.,0.959681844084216,1.9190977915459,
2.87738689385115,3.83575332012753,5.75433905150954,7.67363431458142,9.74768208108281,
10.7850777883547,11.8223963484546,12.8610794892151,13.8997286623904,14.9377892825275,
15.9758013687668,17.1090815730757,18.2420068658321,19.3700240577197,19.9337037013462,
20.4973442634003,21.4467185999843,22.3979796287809,22.8807596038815,23.3636294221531,
23.8446911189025,24.3253539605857,24.9256472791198,25.5254037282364,26.1260789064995,
26.7272844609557,27.5022221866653,28.2789089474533,28.9163059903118,29.5541423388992,
30.193038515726,30.8321828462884,31.4687519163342,32.1052377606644,33.3791509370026,
34.6565874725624,35.9336911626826,37.0798743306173,38.2262114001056,39.373316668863,
40.5203686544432,41.6654966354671,42.8106570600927,43.9553335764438,45.099926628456,
46.5938371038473,48.087208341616,48.8332472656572,49.5792522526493,50.325905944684,
51.0726725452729),.UNSPECIFIED.);
#484=CARTESIAN_POINT('',(-22.6318376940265,74.93,32.8759602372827));
#485=VERTEX_POINT('',#484);
#486=EDGE_CURVE('E1675',#372,#485,#483,.T.);
#487=ORIENTED_EDGE('',*,*,#486,.T.);
#488=CARTESIAN_POINT('',(-24.9752922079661,74.93,31.132998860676));
#489=VERTEX_POINT('',#488);
#490=EDGE_CURVE('E1336',#485,#489,#370,.F.);
#491=ORIENTED_EDGE('',*,*,#490,.T.);
#492=CARTESIAN_POINT('',(-29.476664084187,68.5798,32.417453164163));
#493=CARTESIAN_POINT('',(-29.1062316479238,69.1125841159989,32.3117512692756));
#494=CARTESIAN_POINT('',(-28.7347583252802,69.6445870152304,32.2057523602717));
#495=CARTESIAN_POINT('',(-27.9895431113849,70.7068520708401,31.9931072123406));
#496=CARTESIAN_POINT('',(-27.6158012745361,71.2371142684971,31.8864609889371));
#497=CARTESIAN_POINT('',(-26.8658433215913,72.2957468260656,31.6724625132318));
#498=CARTESIAN_POINT('',(-26.4896271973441,72.8241171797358,31.565110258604));
#499=CARTESIAN_POINT('',(-25.7344797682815,73.8787747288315,31.3496309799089));
#500=CARTESIAN_POINT('',(-25.3555483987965,74.4050618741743,31.2415039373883));
#501=CARTESIAN_POINT('',(-24.9751473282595,74.9302,31.1329575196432));
#502=B_SPLINE_CURVE_WITH_KNOTS('',3,(#492,#493,#494,#495,#496,#497,#498,#499,#500,#501),
.UNSPECIFIED.,.F.,.F.,(4,2,2,2,4),(0.,1.97237650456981,3.9447058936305,5.91704178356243,
7.88942480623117),.UNSPECIFIED.);
#503=CARTESIAN_POINT('',(-29.4765250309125,68.58,32.4174134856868));
#504=VERTEX_POINT('',#503);
#505=EDGE_CURVE('E850',#504,#489,#502,.T.);
#506=ORIENTED_EDGE('',*,*,#505,.F.);
#507=CARTESIAN_POINT('',(29.4480592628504,68.58,32.443274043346));
#508=VERTEX_POINT('',#507);
#509=EDGE_CURVE('E1171',#508,#504,#186,.T.);
#510=ORIENTED_EDGE('',*,*,#509,.F.);
#511=CARTESIAN_POINT('',(24.9095706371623,74.9302,31.1854504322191));
#512=CARTESIAN_POINT('',(25.2932994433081,74.4052604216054,31.2917993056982));
#513=CARTESIAN_POINT('',(25.6754921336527,73.8791142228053,31.3977224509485));
#514=CARTESIAN_POINT('',(26.4370404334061,72.8246364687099,31.6087824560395));
#515=CARTESIAN_POINT('',(26.8163961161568,72.2963049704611,31.7139193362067));
#516=CARTESIAN_POINT('',(27.5725240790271,71.2376591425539,31.923477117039));
#517=CARTESIAN_POINT('',(27.9492963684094,70.7073448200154,32.0278980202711));
#518=CARTESIAN_POINT('',(28.7004741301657,69.6448927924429,32.2360838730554));
#519=CARTESIAN_POINT('',(29.0748795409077,69.1127550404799,32.3398488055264));
#520=CARTESIAN_POINT('',(29.448199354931,68.5798,32.4433128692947));
#521=B_SPLINE_CURVE_WITH_KNOTS('',3,(#511,#512,#513,#514,#515,#516,#517,#518,#519,#520),
.UNSPECIFIED.,.F.,.F.,(4,2,2,2,4),(0.,1.97662629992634,3.95320132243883,5.9297692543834,
7.90638844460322),.UNSPECIFIED.);
#522=CARTESIAN_POINT('',(24.9097168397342,74.93,31.1854909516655));
#523=VERTEX_POINT('',#522);
#524=EDGE_CURVE('E1332',#523,#508,#521,.T.);
#525=ORIENTED_EDGE('',*,*,#524,.F.);
#526=CARTESIAN_POINT('',(0.,74.93,0.));
#527=DIRECTION('',(0.,1.,0.));
#528=DIRECTION('',(0.,0.,1.));
#529=AXIS2_PLACEMENT_3D('',#526,#527,#528);
#530=CIRCLE('',#529,39.9127653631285);
#531=CARTESIAN_POINT('',(22.6318376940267,74.93,32.8759602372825));
#532=VERTEX_POINT('',#531);
#533=EDGE_CURVE('E1211',#523,#532,#530,.F.);
#534=ORIENTED_EDGE('',*,*,#533,.T.);
#535=CARTESIAN_POINT('',(22.6319772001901,74.9298,32.8760134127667));
#536=CARTESIAN_POINT('',(22.4531520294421,75.1861952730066,32.8078201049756));
#537=CARTESIAN_POINT('',(22.2793275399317,75.4445704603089,32.7341907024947));
#538=CARTESIAN_POINT('',(21.9414911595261,75.9645959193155,32.5770087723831));
#539=CARTESIAN_POINT('',(21.7774765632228,76.2262452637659,32.4934589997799));
#540=CARTESIAN_POINT('',(21.4591594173,76.7519681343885,32.3174500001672));
#541=CARTESIAN_POINT('',(21.3048456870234,77.0160384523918,32.2250013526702));
#542=CARTESIAN_POINT('',(21.0055220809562,77.5464258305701,32.0318436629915));
#543=CARTESIAN_POINT('',(20.8605129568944,77.8127430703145,31.9311339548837));
#544=CARTESIAN_POINT('',(20.4388792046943,78.6150033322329,31.6173532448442));
#545=CARTESIAN_POINT('',(20.1759549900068,79.1537454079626,31.3928032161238));
#546=CARTESIAN_POINT('',(19.6857657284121,80.2357477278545,30.9170512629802));
#547=CARTESIAN_POINT('',(19.4585139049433,80.7790095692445,30.6658395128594));
#548=CARTESIAN_POINT('',(19.0225178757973,81.9115352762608,30.1181588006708));
#549=CARTESIAN_POINT('',(18.8167433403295,82.5009764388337,29.8196739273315));
#550=CARTESIAN_POINT('',(18.5396319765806,83.3846139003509,29.3524342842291));
#551=CARTESIAN_POINT('',(18.4525071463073,83.6791250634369,29.1934054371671));
#552=CARTESIAN_POINT('',(18.2889878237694,84.2675878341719,28.8689346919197));
#553=CARTESIAN_POINT('',(18.2125925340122,84.5615394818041,28.703493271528));
#554=CARTESIAN_POINT('',(18.0707333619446,85.1488284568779,28.366014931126));
#555=CARTESIAN_POINT('',(18.0052839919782,85.442164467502,28.1939696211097));
#556=CARTESIAN_POINT('',(17.8858636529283,86.0273145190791,27.8434345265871));
#557=CARTESIAN_POINT('',(17.8318923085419,86.3191286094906,27.6649449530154));
#558=CARTESIAN_POINT('',(17.7360312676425,86.9004622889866,27.3014619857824));
#559=CARTESIAN_POINT('',(17.6941347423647,87.1899830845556,27.1164723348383));
#560=CARTESIAN_POINT('',(17.6231649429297,87.7661102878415,26.7396312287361));
#561=CARTESIAN_POINT('',(17.5940910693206,88.0527168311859,26.5477800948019));
#562=CARTESIAN_POINT('',(17.5477736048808,88.6481794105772,26.1388486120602));
#563=CARTESIAN_POINT('',(17.5318606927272,88.9566632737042,25.9210687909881));
#564=CARTESIAN_POINT('',(17.5184250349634,89.5671217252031,25.4761618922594));
#565=CARTESIAN_POINT('',(17.5208965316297,89.8690983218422,25.2490377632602));
#566=CARTESIAN_POINT('',(17.5467701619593,90.462861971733,24.7853264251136));
#567=CARTESIAN_POINT('',(17.5700815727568,90.7546875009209,24.5487844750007));
#568=CARTESIAN_POINT('',(17.6234209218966,91.182662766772,24.1854004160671));
#569=CARTESIAN_POINT('',(17.6442539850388,91.3236542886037,24.0628808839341));
#570=CARTESIAN_POINT('',(17.6926688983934,91.6017141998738,23.81477101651));
#571=CARTESIAN_POINT('',(17.7202502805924,91.7387828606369,23.6891808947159));
#572=CARTESIAN_POINT('',(17.8043004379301,92.1003741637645,23.3476505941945));
#573=CARTESIAN_POINT('',(17.8676208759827,92.320550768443,23.1286985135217));
#574=CARTESIAN_POINT('',(18.0200246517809,92.7420139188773,22.6802930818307));
#575=CARTESIAN_POINT('',(18.1091589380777,92.9432620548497,22.4508197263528));
#576=CARTESIAN_POINT('',(18.26714439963,93.2244666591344,22.0978320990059));
#577=CARTESIAN_POINT('',(18.3243659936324,93.315346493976,21.9777912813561));
#578=CARTESIAN_POINT('',(18.4477596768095,93.4877899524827,21.7355133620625));
#579=CARTESIAN_POINT('',(18.5139334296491,93.5693518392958,21.6132758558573));
#580=CARTESIAN_POINT('',(18.6557254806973,93.7206957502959,21.3676920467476));
#581=CARTESIAN_POINT('',(18.7313074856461,93.7905207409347,21.2443516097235));
#582=CARTESIAN_POINT('',(18.8925662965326,93.9162293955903,20.9972701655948));
#583=CARTESIAN_POINT('',(18.9782346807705,93.9721245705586,20.8735295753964));
#584=CARTESIAN_POINT('',(19.1825009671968,94.0793061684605,20.5963531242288));
#585=CARTESIAN_POINT('',(19.3039878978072,94.1259831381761,20.4431915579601));
#586=CARTESIAN_POINT('',(19.5613791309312,94.1891665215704,20.1429486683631));
#587=CARTESIAN_POINT('',(19.6972704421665,94.2056998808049,19.9958620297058));
#588=CARTESIAN_POINT('',(19.980167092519,94.2068511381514,19.712185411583));
#589=CARTESIAN_POINT('',(20.1271891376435,94.1914201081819,19.5756118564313));
#590=CARTESIAN_POINT('',(20.4274436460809,94.130256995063,19.3168358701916));
#591=CARTESIAN_POINT('',(20.5806814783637,94.0844981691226,19.1946462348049));
#592=CARTESIAN_POINT('',(20.9335168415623,93.9499537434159,18.9333227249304));
#593=CARTESIAN_POINT('',(21.1337148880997,93.8525556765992,18.7994959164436));
#594=CARTESIAN_POINT('',(21.5311982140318,93.6253225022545,18.5575341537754));
#595=CARTESIAN_POINT('',(21.7284758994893,93.4954146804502,18.4494578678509));
#596=CARTESIAN_POINT('',(22.0822323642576,93.2378861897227,18.2734255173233));
#597=CARTESIAN_POINT('',(22.2396830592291,93.114033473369,18.2017503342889));
#598=CARTESIAN_POINT('',(22.5502860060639,92.8543658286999,18.0717731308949));
#599=CARTESIAN_POINT('',(22.7034352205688,92.7185427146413,18.0134803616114));
#600=CARTESIAN_POINT('',(23.0055063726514,92.4375711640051,17.9085459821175));
#601=CARTESIAN_POINT('',(23.1544208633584,92.2924076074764,17.8619238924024));
#602=CARTESIAN_POINT('',(23.447982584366,91.9949331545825,17.7789950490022));
#603=CARTESIAN_POINT('',(23.5926281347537,91.842619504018,17.7426923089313));
#604=CARTESIAN_POINT('',(23.8772615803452,91.5330276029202,17.6793668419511));
#605=CARTESIAN_POINT('',(24.017265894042,91.3757718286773,17.6523073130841));
#606=CARTESIAN_POINT('',(24.2934532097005,91.0568516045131,17.6063247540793));
#607=CARTESIAN_POINT('',(24.4296367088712,90.8951877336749,17.5874006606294));
#608=CARTESIAN_POINT('',(24.8331155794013,90.4045581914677,17.5416007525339));
#609=CARTESIAN_POINT('',(25.0951300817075,90.0701857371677,17.5257415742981));
#610=CARTESIAN_POINT('',(25.6073018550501,89.3910127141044,17.5187750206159));
#611=CARTESIAN_POINT('',(25.8574243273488,89.0461858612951,17.527736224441));
#612=CARTESIAN_POINT('',(26.3462664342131,88.3499543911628,17.5674604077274));
#613=CARTESIAN_POINT('',(26.5849890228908,87.9985515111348,17.5982177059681));
#614=CARTESIAN_POINT('',(27.0279886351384,87.327395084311,17.6752315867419));
#615=CARTESIAN_POINT('',(27.2332880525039,87.0080899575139,17.7195760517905));
#616=CARTESIAN_POINT('',(27.6358491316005,86.3667655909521,17.8230232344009));
#617=CARTESIAN_POINT('',(27.833109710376,86.044745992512,17.8821279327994));
#618=CARTESIAN_POINT('',(28.2199078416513,85.3986613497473,18.0143479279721));
#619=CARTESIAN_POINT('',(28.4094401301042,85.0745950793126,18.0874725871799));
#620=CARTESIAN_POINT('',(28.7807004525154,84.4253288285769,18.2471461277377));
#621=CARTESIAN_POINT('',(28.9624288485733,84.100128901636,18.3336943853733));
#622=CARTESIAN_POINT('',(29.3177238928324,83.4497138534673,18.5196821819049));
#623=CARTESIAN_POINT('',(29.4913037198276,83.1244996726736,18.6190998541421));
#624=CARTESIAN_POINT('',(29.8304369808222,82.4740292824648,18.8307065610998));
#625=CARTESIAN_POINT('',(29.9959901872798,82.1487730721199,18.9428959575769));
#626=CARTESIAN_POINT('',(30.3186806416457,81.4988617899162,19.1798765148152));
#627=CARTESIAN_POINT('',(30.4758214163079,81.1742065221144,19.3046623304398));
#628=CARTESIAN_POINT('',(30.7813029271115,80.5258852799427,19.5668462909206));
#629=CARTESIAN_POINT('',(30.9296443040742,80.2022192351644,19.7042435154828));
#630=CARTESIAN_POINT('',(31.2608218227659,79.4577845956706,20.0356080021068));
#631=CARTESIAN_POINT('',(31.4403688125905,79.0375277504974,20.234042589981));
#632=CARTESIAN_POINT('',(31.7817933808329,78.2009180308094,20.6528330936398));
#633=CARTESIAN_POINT('',(31.9436773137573,77.7845638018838,20.8731810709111));
#634=CARTESIAN_POINT('',(32.1715277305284,77.1642648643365,21.2204706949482));
#635=CARTESIAN_POINT('',(32.2449533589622,76.9582923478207,21.3389735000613));
#636=CARTESIAN_POINT('',(32.3865049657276,76.5479021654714,21.5816967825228));
#637=CARTESIAN_POINT('',(32.4546311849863,76.3434844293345,21.7059169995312));
#638=CARTESIAN_POINT('',(32.5852592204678,75.936277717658,21.9602864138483));
#639=CARTESIAN_POINT('',(32.6477560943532,75.7334903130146,22.0904406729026));
#640=CARTESIAN_POINT('',(32.7666088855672,75.3299985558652,22.3567119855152));
#641=CARTESIAN_POINT('',(32.8229638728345,75.1292945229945,22.4928299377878));
#642=CARTESIAN_POINT('',(32.8760134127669,74.9298,22.6319772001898));
#643=B_SPLINE_CURVE_WITH_KNOTS('',3,(#535,#536,#537,#538,#539,#540,#541,#542,#543,#544,#545,
#546,#547,#548,#549,#550,#551,#552,#553,#554,#555,#556,#557,#558,#559,#560,#561,#562,#563,#564,
#565,#566,#567,#568,#569,#570,#571,#572,#573,#574,#575,#576,#577,#578,#579,#580,#581,#582,#583,
#584,#585,#586,#587,#588,#589,#590,#591,#592,#593,#594,#595,#596,#597,#598,#599,#600,#601,#602,
#603,#604,#605,#606,#607,#608,#609,#610,#611,#612,#613,#614,#615,#616,#617,#618,#619,#620,#621,
#622,#623,#624,#625,#626,#627,#628,#629,#630,#631,#632,#633,#634,#635,#636,#637,#638,#639,#640,
#641,#642),.UNSPECIFIED.,.F.,.F.,(4,2,2,2,2,2,2,2,2,2,2,2,2,2,2,2,2,2,2,2,2,2,2,2,2,2,2,2,2,2,2,
2,2,2,2,2,2,2,2,2,2,2,2,2,2,2,2,2,2,2,2,2,2,4),(0.,0.959681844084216,1.9190977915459,
2.87738689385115,3.83575332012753,5.75433905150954,7.67363431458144,9.74768208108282,
10.7850777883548,11.8223963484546,12.8610794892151,13.8997286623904,14.9377892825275,
15.9758013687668,17.1090815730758,18.2420068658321,19.3700240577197,19.9337037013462,
20.4973442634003,21.4467185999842,22.3979796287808,22.8807596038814,23.363629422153,
23.8446911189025,24.3253539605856,24.9256472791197,25.5254037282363,26.1260789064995,
26.7272844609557,27.5022221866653,28.2789089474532,28.9163059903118,29.5541423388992,
30.193038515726,30.8321828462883,31.4687519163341,32.1052377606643,33.3791509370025,
34.6565874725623,35.9336911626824,37.0798743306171,38.2262114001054,39.3733166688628,
40.520368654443,41.6654966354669,42.8106570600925,43.9553335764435,45.0999266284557,
46.5938371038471,48.0872083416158,48.8332472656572,49.5792522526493,50.325905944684,
51.0726725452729),.UNSPECIFIED.);
#644=CARTESIAN_POINT('',(32.8759602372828,74.93,22.6318376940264));
#645=VERTEX_POINT('',#644);
#646=EDGE_CURVE('E1216',#532,#645,#643,.T.);
#647=ORIENTED_EDGE('',*,*,#646,.T.);
#648=CARTESIAN_POINT('',(31.1329988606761,74.93,24.975292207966));
#649=VERTEX_POINT('',#648);
#650=EDGE_CURVE('E1212',#645,#649,#530,.F.);
#651=ORIENTED_EDGE('',*,*,#650,.T.);
#652=CARTESIAN_POINT('',(32.4174531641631,68.5798,29.4766640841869));
#653=CARTESIAN_POINT('',(32.3117512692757,69.1125841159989,29.1062316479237));
#654=CARTESIAN_POINT('',(32.2057523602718,69.6445870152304,28.7347583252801));
#655=CARTESIAN_POINT('',(31.9931072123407,70.7068520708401,27.9895431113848));
#656=CARTESIAN_POINT('',(31.8864609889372,71.2371142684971,27.615801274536));
#657=CARTESIAN_POINT('',(31.6724625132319,72.2957468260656,26.8658433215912));
#658=CARTESIAN_POINT('',(31.5651102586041,72.8241171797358,26.489627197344));
#659=CARTESIAN_POINT('',(31.349630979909,73.8787747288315,25.7344797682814));
#660=CARTESIAN_POINT('',(31.2415039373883,74.4050618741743,25.3555483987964));
#661=CARTESIAN_POINT('',(31.1329575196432,74.9302,24.9751473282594));
#662=B_SPLINE_CURVE_WITH_KNOTS('',3,(#652,#653,#654,#655,#656,#657,#658,#659,#660,#661),
.UNSPECIFIED.,.F.,.F.,(4,2,2,2,4),(0.,1.97237650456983,3.9447058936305,5.91704178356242,
7.88942480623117),.UNSPECIFIED.);
#663=CARTESIAN_POINT('',(32.4174134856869,68.58,29.4765250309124));
#664=VERTEX_POINT('',#663);
#665=EDGE_CURVE('E1438',#664,#649,#662,.T.);
#666=ORIENTED_EDGE('',*,*,#665,.F.);
#667=EDGE_CURVE('E1173',#38,#664,#186,.T.);
#668=ORIENTED_EDGE('',*,*,#667,.F.);
#669=EDGE_LOOP('',(#40,#49,#162,#166,#181,#190,#205,#214,#327,#331,#346,#350,#365,#374,#487,
#491,#506,#510,#525,#534,#647,#651,#666,#668));
#670=FACE_BOUND('',#669,.T.);
#671=CARTESIAN_POINT('',(0.,114.046,0.));
#672=DIRECTION('',(0.,-1.,0.));
#673=DIRECTION('',(0.,0.,-1.));
#674=AXIS2_PLACEMENT_3D('',#671,#672,#673);
#675=CIRCLE('',#674,15.875);
#676=CARTESIAN_POINT('',(0.,114.046,-15.875));
#677=VERTEX_POINT('',#676);
#678=EDGE_CURVE('E1158',#677,#677,#675,.T.);
#679=ORIENTED_EDGE('',*,*,#678,.T.);
#680=EDGE_LOOP('',(#679));
#681=FACE_BOUND('',#680,.T.);
#682=ADVANCED_FACE('F37',(#670,#681),#23,.T.);
#683=CARTESIAN_POINT('',(0.,140.97,0.));
#684=DIRECTION('',(0.,-1.,0.));
#685=DIRECTION('',(0.,0.,-1.));
#686=AXIS2_PLACEMENT_3D('',#683,#684,#685);
#687=CYLINDRICAL_SURFACE('',#686,43.815);
#688=CARTESIAN_POINT('',(-9.68298069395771,18.4825735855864,-42.7316523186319));
#689=CARTESIAN_POINT('',(-9.43405366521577,18.210649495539,-42.7880588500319));
#690=CARTESIAN_POINT('',(-9.17374525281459,17.9491843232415,-42.8447565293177));
#691=CARTESIAN_POINT('',(-8.63200295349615,17.4488875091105,-42.9571795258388));
#692=CARTESIAN_POINT('',(-8.35056789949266,17.210057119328,-43.0129047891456));
#693=CARTESIAN_POINT('',(-7.76826742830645,16.7566105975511,-43.1218735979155));
#694=CARTESIAN_POINT('',(-7.46739798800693,16.5419995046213,-43.1751166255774));
#695=CARTESIAN_POINT('',(-6.84819093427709,16.1385987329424,-43.2776497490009));
#696=CARTESIAN_POINT('',(-6.52985402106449,15.949808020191,-43.3269400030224));
#697=CARTESIAN_POINT('',(-5.8772587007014,15.5992097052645,-43.4202815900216));
#698=CARTESIAN_POINT('',(-5.54297632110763,15.4374444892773,-43.4643246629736));
#699=CARTESIAN_POINT('',(-4.86121271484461,15.1425826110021,-43.5458457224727));
#700=CARTESIAN_POINT('',(-4.51373140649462,15.0094861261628,-43.5833236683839));
#701=CARTESIAN_POINT('',(-3.80812602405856,14.7731592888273,-43.6506352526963));
#702=CARTESIAN_POINT('',(-3.45000465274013,14.6699214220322,-43.6804708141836));
#703=CARTESIAN_POINT('',(-2.72569416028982,14.4942271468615,-43.7316430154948));
#704=CARTESIAN_POINT('',(-2.35950529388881,14.4217697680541,-43.7529799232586));
#705=CARTESIAN_POINT('',(-1.63316793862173,14.3100717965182,-43.7860147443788));
#706=CARTESIAN_POINT('',(-1.27317767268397,14.2698823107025,-43.7979877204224));
#707=CARTESIAN_POINT('',(-0.550921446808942,14.2194604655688,-43.8130250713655));
#708=CARTESIAN_POINT('',(-0.188655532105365,14.2092275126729,-43.8160896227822));
#709=CARTESIAN_POINT('',(0.535402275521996,14.2188148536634,-43.813224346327));
#710=CARTESIAN_POINT('',(0.897194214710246,14.2386319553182,-43.8072954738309));
#711=CARTESIAN_POINT('',(1.61764013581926,14.3081255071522,-43.7866113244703));
#712=CARTESIAN_POINT('',(1.97629414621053,14.3578016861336,-43.7718561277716));
#713=CARTESIAN_POINT('',(2.67924881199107,14.4849962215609,-43.734388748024));
#714=CARTESIAN_POINT('',(3.02368709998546,14.5618150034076,-43.7118768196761));
#715=CARTESIAN_POINT('',(3.70471577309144,14.7427859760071,-43.6594313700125));
#716=CARTESIAN_POINT('',(4.04130631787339,14.8469376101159,-43.6294979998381));
#717=CARTESIAN_POINT('',(4.70446165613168,15.0817306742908,-43.5629812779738));
#718=CARTESIAN_POINT('',(5.03102566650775,15.2123741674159,-43.5263974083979));
#719=CARTESIAN_POINT('',(5.67205240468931,15.4991352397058,-43.4475125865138));
#720=CARTESIAN_POINT('',(5.98651482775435,15.6552534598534,-43.4052114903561));
#721=CARTESIAN_POINT('',(6.6087849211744,15.9958489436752,-43.3148864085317));
#722=CARTESIAN_POINT('',(6.91625424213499,16.1809145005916,-43.2667498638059));
#723=CARTESIAN_POINT('',(7.51463998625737,16.5752341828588,-43.1668442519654));
#724=CARTESIAN_POINT('',(7.80555620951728,16.7844886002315,-43.1150751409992));
#725=CARTESIAN_POINT('',(8.3691749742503,17.225826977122,-43.0092243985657));
#726=CARTESIAN_POINT('',(8.64187350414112,17.4579159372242,-42.9551422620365));
#727=CARTESIAN_POINT('',(9.1673942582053,17.9434067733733,-42.8460633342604));
#728=CARTESIAN_POINT('',(9.42021600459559,18.1968091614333,-42.7910665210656));
#729=CARTESIAN_POINT('',(9.9141659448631,18.7338965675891,-42.6793884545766));
#730=CARTESIAN_POINT('',(10.154424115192,19.018386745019,-42.6227276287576));
#731=CARTESIAN_POINT('',(10.6102585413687,19.6069021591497,-42.511547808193));
#732=CARTESIAN_POINT('',(10.825834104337,19.9109279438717,-42.4570288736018));
#733=CARTESIAN_POINT('',(11.2308268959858,20.5365599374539,-42.351700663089));
#734=CARTESIAN_POINT('',(11.4202433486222,20.8581666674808,-42.3008914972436));
#735=CARTESIAN_POINT('',(11.771526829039,21.5168402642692,-42.2044852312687));
#736=CARTESIAN_POINT('',(11.9333941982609,21.8539069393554,-42.1588880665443));
#737=CARTESIAN_POINT('',(12.2284455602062,22.5415198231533,-42.0742550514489));
#738=CARTESIAN_POINT('',(12.3616049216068,22.8920773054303,-42.0352248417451));
#739=CARTESIAN_POINT('',(12.5979495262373,23.603930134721,-41.9649986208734));
#740=CARTESIAN_POINT('',(12.7011346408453,23.9652255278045,-41.9338026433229));
#741=CARTESIAN_POINT('',(12.8765857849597,24.6957957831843,-41.8802601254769));
#742=CARTESIAN_POINT('',(12.9488599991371,25.0650685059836,-41.8579112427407));
#743=CARTESIAN_POINT('',(13.0618478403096,25.808858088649,-41.8227912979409));
#744=CARTESIAN_POINT('',(13.1025625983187,26.1833747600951,-41.8100198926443));
#745=CARTESIAN_POINT('',(13.1511027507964,26.9204651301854,-41.7947763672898));
#746=CARTESIAN_POINT('',(13.1601164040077,27.2829533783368,-41.791932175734));
#747=CARTESIAN_POINT('',(13.1484896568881,28.0074006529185,-41.7955916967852));
#748=CARTESIAN_POINT('',(13.1278500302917,28.3693596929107,-41.8020951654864));
#749=CARTESIAN_POINT('',(13.0571070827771,29.0900824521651,-41.8242459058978));
#750=CARTESIAN_POINT('',(13.0070051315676,29.4488463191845,-41.8398927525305));
#751=CARTESIAN_POINT('',(12.8777844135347,30.1606160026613,-41.8798454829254));
#752=CARTESIAN_POINT('',(12.7986655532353,30.5136218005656,-41.904151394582));
#753=CARTESIAN_POINT('',(12.6132908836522,31.2069115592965,-41.960318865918));
#754=CARTESIAN_POINT('',(12.5073973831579,31.5473007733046,-41.9920791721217));
#755=CARTESIAN_POINT('',(12.2688361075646,32.2178274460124,-42.0623981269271));
#756=CARTESIAN_POINT('',(12.1361686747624,32.5479650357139,-42.1009566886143));
#757=CARTESIAN_POINT('',(11.8450469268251,33.1959090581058,-42.1837880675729));
#758=CARTESIAN_POINT('',(11.6865929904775,33.5137156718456,-42.2280608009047));
#759=CARTESIAN_POINT('',(11.3449405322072,34.1351843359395,-42.3211282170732));
#760=CARTESIAN_POINT('',(11.1617331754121,34.4388412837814,-42.3699245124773));
#761=CARTESIAN_POINT('',(10.7652958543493,35.039978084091,-42.4724136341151));
#762=CARTESIAN_POINT('',(10.55126773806,35.3369132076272,-42.5262155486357));
#763=CARTESIAN_POINT('',(10.0995132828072,35.9117935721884,-42.6357603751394));
#764=CARTESIAN_POINT('',(9.86178640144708,36.1897383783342,-42.6915033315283));
#765=CARTESIAN_POINT('',(9.36404574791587,36.724991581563,-42.8034338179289));
#766=CARTESIAN_POINT('',(9.10402419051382,36.9822927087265,-42.8596214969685));
#767=CARTESIAN_POINT('',(8.56345896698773,37.4744134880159,-42.9708913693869));
#768=CARTESIAN_POINT('',(8.28292233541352,37.7092407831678,-43.0259739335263));
#769=CARTESIAN_POINT('',(7.69550193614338,38.1606749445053,-43.1349621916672));
#770=CARTESIAN_POINT('',(7.38812645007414,38.3766587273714,-43.1888012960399));
#771=CARTESIAN_POINT('',(6.75550098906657,38.7818215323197,-43.2922642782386));
#772=CARTESIAN_POINT('',(6.43025063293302,38.9709999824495,-43.3418880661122));
#773=CARTESIAN_POINT('',(5.76411376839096,39.3210186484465,-43.435495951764));
#774=CARTESIAN_POINT('',(5.42322940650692,39.4818627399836,-43.4794808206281));
#775=CARTESIAN_POINT('',(4.7281825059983,39.7738687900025,-43.5605429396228));
#776=CARTESIAN_POINT('',(4.37402039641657,39.9050317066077,-43.5976204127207));
#777=CARTESIAN_POINT('',(3.66378714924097,40.1336645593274,-43.6629699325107));
#778=CARTESIAN_POINT('',(3.3079730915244,40.2318780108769,-43.6914346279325));
#779=CARTESIAN_POINT('',(2.58877520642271,40.3980251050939,-43.7399399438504));
#780=CARTESIAN_POINT('',(2.22539148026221,40.4659591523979,-43.7599806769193));
#781=CARTESIAN_POINT('',(1.49388527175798,40.5708868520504,-43.791055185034));
#782=CARTESIAN_POINT('',(1.12576389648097,40.6078876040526,-43.802091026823));
#783=CARTESIAN_POINT('',(0.387553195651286,40.6506103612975,-43.8148409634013));
#784=CARTESIAN_POINT('',(0.0174639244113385,40.6563332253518,-43.8165553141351));
#785=CARTESIAN_POINT('',(-0.707388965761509,40.6368353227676,-43.8107298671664));
#786=CARTESIAN_POINT('',(-1.0621882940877,40.6128105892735,-43.8035477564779));
#787=CARTESIAN_POINT('',(-1.76838163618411,40.5360447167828,-43.780724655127));
#788=CARTESIAN_POINT('',(-2.11977574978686,40.4833044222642,-43.7650839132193));
#789=CARTESIAN_POINT('',(-2.81668096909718,40.3495797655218,-43.725763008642));
#790=CARTESIAN_POINT('',(-3.16219211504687,40.2685955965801,-43.7020829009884));
#791=CARTESIAN_POINT('',(-3.84497099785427,40.0790812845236,-43.6473107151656));
#792=CARTESIAN_POINT('',(-4.18223862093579,39.970550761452,-43.6162185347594));
#793=CARTESIAN_POINT('',(-4.84689013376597,39.7266206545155,-43.5473732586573));
#794=CARTESIAN_POINT('',(-5.17425538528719,39.5911736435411,-43.5096084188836));
#795=CARTESIAN_POINT('',(-5.81639472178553,39.2945900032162,-43.428429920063));
#796=CARTESIAN_POINT('',(-6.13116885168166,39.1334534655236,-43.3850162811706));
#797=CARTESIAN_POINT('',(-6.74621507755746,38.786668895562,-43.2936424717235));
#798=CARTESIAN_POINT('',(-7.04648709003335,38.6010207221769,-43.2456822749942));
#799=CARTESIAN_POINT('',(-7.63086759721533,38.2064210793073,-43.1464016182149));
#800=CARTESIAN_POINT('',(-7.91497027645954,37.9974613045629,-43.095079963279));
#801=CARTESIAN_POINT('',(-8.47612914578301,37.5489640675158,-42.9883033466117));
#802=CARTESIAN_POINT('',(-8.75246605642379,37.3085459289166,-42.9327652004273));
#803=CARTESIAN_POINT('',(-9.28410808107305,36.8056383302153,-42.8209454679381));
#804=CARTESIAN_POINT('',(-9.53941270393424,36.5431483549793,-42.7646638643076));
#805=CARTESIAN_POINT('',(-10.0274965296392,35.9976749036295,-42.6528575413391));
#806=CARTESIAN_POINT('',(-10.2602676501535,35.7146841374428,-42.5973330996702));
#807=CARTESIAN_POINT('',(-10.7016182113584,35.1301659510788,-42.4886013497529));
#808=CARTESIAN_POINT('',(-10.9102059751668,34.8286449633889,-42.4353932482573));
#809=CARTESIAN_POINT('',(-11.3066551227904,34.2013167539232,-42.3315107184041));
#810=CARTESIAN_POINT('',(-11.493889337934,33.8750973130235,-42.280929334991));
#811=CARTESIAN_POINT('',(-11.8402150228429,33.207260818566,-42.1852560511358));
#812=CARTESIAN_POINT('',(-11.9993059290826,32.8656434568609,-42.1401642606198));
#813=CARTESIAN_POINT('',(-12.2880419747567,32.1694384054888,-42.0568762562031));
#814=CARTESIAN_POINT('',(-12.4176926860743,31.8148531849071,-42.0186787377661));
#815=CARTESIAN_POINT('',(-12.6464716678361,31.0952092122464,-41.9503903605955));
#816=CARTESIAN_POINT('',(-12.745600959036,30.7301508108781,-41.9202992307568));
#817=CARTESIAN_POINT('',(-12.9102907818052,30.0017939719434,-41.8698679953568));
#818=CARTESIAN_POINT('',(-12.9766494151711,29.63869193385,-41.8492969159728));
#819=CARTESIAN_POINT('',(-13.0789404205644,28.9078214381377,-41.8174416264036));
#820=CARTESIAN_POINT('',(-13.1148732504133,28.5400530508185,-41.8061572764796));
#821=CARTESIAN_POINT('',(-13.1559730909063,27.802686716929,-41.793241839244));
#822=CARTESIAN_POINT('',(-13.1611446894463,27.4330890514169,-41.7916093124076));
#823=CARTESIAN_POINT('',(-13.1406847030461,26.6948371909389,-41.7980471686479));
#824=CARTESIAN_POINT('',(-13.1150537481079,26.3261829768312,-41.8061173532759));
#825=CARTESIAN_POINT('',(-13.0345565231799,25.6044756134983,-41.8312832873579));
#826=CARTESIAN_POINT('',(-12.9806612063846,25.251303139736,-41.8480791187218));
#827=CARTESIAN_POINT('',(-12.8447215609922,24.5509295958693,-41.8900036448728));
#828=CARTESIAN_POINT('',(-12.7626776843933,24.203728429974,-41.9151322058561));
#829=CARTESIAN_POINT('',(-12.5711263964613,23.5176684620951,-41.9729794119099));
#830=CARTESIAN_POINT('',(-12.4616207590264,23.1788091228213,-42.0056975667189));
#831=CARTESIAN_POINT('',(-12.2160007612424,22.5116147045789,-42.0777841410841));
#832=CARTESIAN_POINT('',(-12.0798867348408,22.1832794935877,-42.1171524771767));
#833=CARTESIAN_POINT('',(-11.7881053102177,21.552272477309,-42.1997254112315));
#834=CARTESIAN_POINT('',(-11.6334562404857,21.2490999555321,-42.2427093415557));
#835=CARTESIAN_POINT('',(-11.3015094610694,20.6558985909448,-42.3327259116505));
#836=CARTESIAN_POINT('',(-11.1242033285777,20.3658746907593,-42.3797600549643));
#837=CARTESIAN_POINT('',(-10.7480564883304,19.8006794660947,-42.4767137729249));
#838=CARTESIAN_POINT('',(-10.5492169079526,19.5255073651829,-42.5266331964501));
#839=CARTESIAN_POINT('',(-10.1311196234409,18.9914669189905,-42.6281704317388));
#840=CARTESIAN_POINT('',(-9.91186119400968,18.7325991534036,-42.6797883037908));
#841=CARTESIAN_POINT('',(-9.68298069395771,18.4825735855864,-42.7316523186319));
#842=B_SPLINE_CURVE_WITH_KNOTS('',3,(#688,#689,#690,#691,#692,#693,#694,#695,#696,#697,#698,
#699,#700,#701,#702,#703,#704,#705,#706,#707,#708,#709,#710,#711,#712,#713,#714,#715,#716,#717,
#718,#719,#720,#721,#722,#723,#724,#725,#726,#727,#728,#729,#730,#731,#732,#733,#734,#735,#736,
#737,#738,#739,#740,#741,#742,#743,#744,#745,#746,#747,#748,#749,#750,#751,#752,#753,#754,#755,
#756,#757,#758,#759,#760,#761,#762,#763,#764,#765,#766,#767,#768,#769,#770,#771,#772,#773,#774,
#775,#776,#777,#778,#779,#780,#781,#782,#783,#784,#785,#786,#787,#788,#789,#790,#791,#792,#793,
#794,#795,#796,#797,#798,#799,#800,#801,#802,#803,#804,#805,#806,#807,#808,#809,#810,#811,#812,
#813,#814,#815,#816,#817,#818,#819,#820,#821,#822,#823,#824,#825,#826,#827,#828,#829,#830,#831,
#832,#833,#834,#835,#836,#837,#838,#839,#840,#841),.UNSPECIFIED.,.T.,.F.,(4,2,2,2,2,2,2,2,2,2,2,
2,2,2,2,2,2,2,2,2,2,2,2,2,2,2,2,2,2,2,2,2,2,2,2,2,2,2,2,2,2,2,2,2,2,2,2,2,2,2,2,2,2,2,2,2,2,2,2,
2,2,2,2,2,2,2,2,2,2,2,2,2,2,2,2,2,4),(0.,1.11854474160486,2.23715131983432,3.3559902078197,
4.47478427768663,5.595316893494,6.71585644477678,7.83611375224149,8.95633573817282,
10.0422670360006,11.1281768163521,12.2139712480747,13.2997558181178,14.359382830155,
15.4189882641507,16.4786762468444,17.538390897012,18.6234169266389,19.7084560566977,
20.7937333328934,21.8790366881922,23.0076761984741,24.1363473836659,25.2650520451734,
26.3937427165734,27.5233979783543,28.6530580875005,29.7824188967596,30.9117392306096,
31.9982494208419,33.0847312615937,34.1711625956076,35.2575974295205,36.3300516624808,
37.4024921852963,38.4749169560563,39.5477255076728,40.6563523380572,41.765004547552,
42.8740454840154,43.9827079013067,45.1198525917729,46.2570215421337,47.3940348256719,
48.5310114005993,49.6402667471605,50.7495072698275,51.8584931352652,52.9674485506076,
54.033229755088,55.0989796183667,56.1647221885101,57.2304794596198,58.2981315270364,
59.3657797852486,60.4334341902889,61.5014701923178,62.611609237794,63.7217741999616,
64.8323358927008,65.9425142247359,67.0796824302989,68.2168734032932,69.3538489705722,
70.490786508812,71.5984704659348,72.7061377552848,73.8136398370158,74.921119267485,
75.9928302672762,77.0645240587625,78.1361486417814,79.2077597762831,80.235860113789,
81.2643437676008,82.2927736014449,83.3212399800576),.UNSPECIFIED.);
#843=CARTESIAN_POINT('',(-9.68298069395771,18.4825735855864,-42.7316523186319));
#844=VERTEX_POINT('',#843);
#845=EDGE_CURVE('E11',#844,#844,#842,.T.);
#846=ORIENTED_EDGE('',*,*,#845,.T.);
#847=EDGE_LOOP('',(#846));
#848=FACE_BOUND('',#847,.T.);
#849=CARTESIAN_POINT('',(-9.68298069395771,18.4825735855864,42.7316523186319));
#850=CARTESIAN_POINT('',(-9.93175038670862,18.7543276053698,42.675281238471));
#851=CARTESIAN_POINT('',(-10.1691726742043,19.0365488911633,42.6191965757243));
#852=CARTESIAN_POINT('',(-10.6197823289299,19.6201260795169,42.5091550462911));
#853=CARTESIAN_POINT('',(-10.8329683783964,19.9214830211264,42.4551982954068));
#854=CARTESIAN_POINT('',(-11.2336987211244,20.5414740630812,42.350928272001));
#855=CARTESIAN_POINT('',(-11.4212383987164,20.8601112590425,42.300615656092));
#856=CARTESIAN_POINT('',(-11.7692802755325,21.5125493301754,42.2051045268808));
#857=CARTESIAN_POINT('',(-11.9297835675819,21.8463495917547,42.1599058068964));
#858=CARTESIAN_POINT('',(-12.222758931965,22.5274358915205,42.0759036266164));
#859=CARTESIAN_POINT('',(-12.355187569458,22.8747418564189,42.0371100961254));
#860=CARTESIAN_POINT('',(-12.5906128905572,23.5799530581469,41.9671989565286));
#861=CARTESIAN_POINT('',(-12.6936094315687,23.9378583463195,41.9360813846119));
#862=CARTESIAN_POINT('',(-12.8692444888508,24.6615843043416,41.8825167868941));
#863=CARTESIAN_POINT('',(-12.9418910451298,25.0274028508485,41.8600674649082));
#864=CARTESIAN_POINT('',(-13.0561941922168,25.764298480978,41.8245575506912));
#865=CARTESIAN_POINT('',(-13.0978516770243,26.1353754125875,41.8114966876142));
#866=CARTESIAN_POINT('',(-13.1490243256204,26.8690478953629,41.7954312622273));
#867=CARTESIAN_POINT('',(-13.1594429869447,27.2315745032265,41.7921440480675));
#868=CARTESIAN_POINT('',(-13.1506108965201,27.956225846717,41.7949241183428));
#869=CARTESIAN_POINT('',(-13.131360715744,28.3183505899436,41.8009912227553));
#870=CARTESIAN_POINT('',(-13.0633679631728,29.0395341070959,41.822289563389));
#871=CARTESIAN_POINT('',(-13.014626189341,29.3985929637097,41.8375205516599));
#872=CARTESIAN_POINT('',(-12.8880855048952,30.1110675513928,41.876674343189));
#873=CARTESIAN_POINT('',(-12.8102865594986,30.4644832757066,41.9005971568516));
#874=CARTESIAN_POINT('',(-12.6275226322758,31.1585524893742,41.9560350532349));
#875=CARTESIAN_POINT('',(-12.5229319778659,31.4993131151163,41.9874451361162));
#876=CARTESIAN_POINT('',(-12.2869422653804,32.1706881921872,42.0571087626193));
#877=CARTESIAN_POINT('',(-12.1555435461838,32.5013027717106,42.0953622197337));
#878=CARTESIAN_POINT('',(-11.8669190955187,33.1502983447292,42.177635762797));
#879=CARTESIAN_POINT('',(-11.7096938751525,33.4686795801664,42.2216557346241));
#880=CARTESIAN_POINT('',(-11.3704531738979,34.0913912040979,42.3142757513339));
#881=CARTESIAN_POINT('',(-11.1884288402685,34.3957165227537,42.3628774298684));
#882=CARTESIAN_POINT('',(-10.7944069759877,34.998208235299,42.4650181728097));
#883=CARTESIAN_POINT('',(-10.5816172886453,35.2958381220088,42.5186673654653));
#884=CARTESIAN_POINT('',(-10.1322947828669,35.8722099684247,42.6279752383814));
#885=CARTESIAN_POINT('',(-9.89576141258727,36.1509514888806,42.6836339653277));
#886=CARTESIAN_POINT('',(-9.40035659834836,36.6878984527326,42.7954671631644));
#887=CARTESIAN_POINT('',(-9.14147732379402,36.9460966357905,42.8516418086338));
#888=CARTESIAN_POINT('',(-8.60313733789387,37.4401096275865,42.9629580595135));
#889=CARTESIAN_POINT('',(-8.32368366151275,37.6759320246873,43.0181000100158));
#890=CARTESIAN_POINT('',(-7.73825319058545,38.1295850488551,43.1273069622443));
#891=CARTESIAN_POINT('',(-7.43177379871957,38.3467836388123,43.1813060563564));
#892=CARTESIAN_POINT('',(-6.8008432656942,38.7544506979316,43.2851586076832));
#893=CARTESIAN_POINT('',(-6.47639173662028,38.9449185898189,43.3350119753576));
#894=CARTESIAN_POINT('',(-5.81174444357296,39.2975859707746,43.4291431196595));
#895=CARTESIAN_POINT('',(-5.47155077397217,39.4597892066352,43.473421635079));
#896=CARTESIAN_POINT('',(-4.77776854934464,39.7545754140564,43.5551274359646));
#897=CARTESIAN_POINT('',(-4.42418042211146,39.8871593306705,43.5925549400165));
#898=CARTESIAN_POINT('',(-3.7147682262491,40.1187126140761,43.6586598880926));
#899=CARTESIAN_POINT('',(-3.35919877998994,40.2184085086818,43.6875247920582));
#900=CARTESIAN_POINT('',(-2.64035448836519,40.3875265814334,43.7368554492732));
#901=CARTESIAN_POINT('',(-2.27707974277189,40.4569491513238,43.7573213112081));
#902=CARTESIAN_POINT('',(-1.54565476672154,40.5648457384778,43.7892582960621));
#903=CARTESIAN_POINT('',(-1.17750568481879,40.6033269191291,43.8007315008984));
#904=CARTESIAN_POINT('',(-0.43910315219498,40.6489883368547,43.8143555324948));
#905=CARTESIAN_POINT('',(-0.0688497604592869,40.6561694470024,43.8165066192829));
#906=CARTESIAN_POINT('',(0.656375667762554,40.6394970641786,43.8115249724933));
#907=CARTESIAN_POINT('',(1.01137851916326,40.6168474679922,43.8047523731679));
#908=CARTESIAN_POINT('',(1.71809743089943,40.542798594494,43.7827288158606));
#909=CARTESIAN_POINT('',(2.06981358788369,40.4914001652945,43.7674781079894));
#910=CARTESIAN_POINT('',(2.76747406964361,40.3603150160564,43.7289078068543));
#911=CARTESIAN_POINT('',(3.11341844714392,40.2806285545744,43.7055882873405));
#912=CARTESIAN_POINT('',(3.7971675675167,40.0936560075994,43.6514990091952));
#913=CARTESIAN_POINT('',(4.13497220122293,39.986369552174,43.6207291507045));
#914=CARTESIAN_POINT('',(4.8005920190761,39.7449416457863,43.5525040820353));
#915=CARTESIAN_POINT('',(5.12839502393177,39.6107688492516,43.515041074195));
#916=CARTESIAN_POINT('',(5.77151173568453,39.3166970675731,43.4344208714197));
#917=CARTESIAN_POINT('',(6.0868254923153,39.1567981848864,43.3912636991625));
#918=CARTESIAN_POINT('',(6.70304652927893,38.8124464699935,43.3003510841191));
#919=CARTESIAN_POINT('',(7.0039537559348,38.6279935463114,43.2525956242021));
#920=CARTESIAN_POINT('',(7.58969590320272,38.235736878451,43.1536673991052));
#921=CARTESIAN_POINT('',(7.87452504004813,38.027924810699,43.1024934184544));
#922=CARTESIAN_POINT('',(8.43720324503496,37.581754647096,42.9959650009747));
#923=CARTESIAN_POINT('',(8.71433988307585,37.3425179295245,42.9405253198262));
#924=CARTESIAN_POINT('',(9.24767832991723,36.8419187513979,42.8288328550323));
#925=CARTESIAN_POINT('',(9.50387964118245,36.5805557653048,42.7725800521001));
#926=CARTESIAN_POINT('',(9.99385192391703,36.0372754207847,42.6607586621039));
#927=CARTESIAN_POINT('',(10.2276148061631,35.7553507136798,42.6051903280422));
#928=CARTESIAN_POINT('',(10.6710409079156,35.1728956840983,42.4962966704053));
#929=CARTESIAN_POINT('',(10.8807123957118,34.8723717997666,42.442970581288));
#930=CARTESIAN_POINT('',(11.2795458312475,34.2468279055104,42.3387484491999));
#931=CARTESIAN_POINT('',(11.4680696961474,33.9213850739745,42.2879455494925));
#932=CARTESIAN_POINT('',(11.8170375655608,33.2549954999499,42.1917601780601));
#933=CARTESIAN_POINT('',(11.9774809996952,32.9140484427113,42.1463778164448));
#934=CARTESIAN_POINT('',(12.2689793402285,32.2190657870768,42.0624463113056));
#935=CARTESIAN_POINT('',(12.4000395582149,31.8650325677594,42.0238959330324));
#936=CARTESIAN_POINT('',(12.6316847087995,31.1463681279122,41.9548494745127));
#937=CARTESIAN_POINT('',(12.7322706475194,30.7817372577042,41.9243531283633));
#938=CARTESIAN_POINT('',(12.8999141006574,30.0539107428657,41.8730693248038));
#939=CARTESIAN_POINT('',(12.9677536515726,29.6909110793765,41.8520562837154));
#940=CARTESIAN_POINT('',(13.072997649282,28.9601098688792,41.8193018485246));
#941=CARTESIAN_POINT('',(13.1104025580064,28.5923083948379,41.8075603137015));
#942=CARTESIAN_POINT('',(13.1544229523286,27.8547542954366,41.7937305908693));
#943=CARTESIAN_POINT('',(13.16104413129,27.4850020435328,41.7916406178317));
#944=CARTESIAN_POINT('',(13.1434490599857,26.7463093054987,41.7971776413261));
#945=CARTESIAN_POINT('',(13.1192333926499,26.3773688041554,41.8048044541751));
#946=CARTESIAN_POINT('',(13.0414903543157,25.6551234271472,41.8291206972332));
#947=CARTESIAN_POINT('',(12.9889473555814,25.3017017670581,41.8455056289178));
#948=CARTESIAN_POINT('',(12.8556818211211,24.6007189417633,41.8866389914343));
#949=CARTESIAN_POINT('',(12.7749599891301,24.253157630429,41.911387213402));
#950=CARTESIAN_POINT('',(12.5859986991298,23.5662203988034,41.9685190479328));
#951=CARTESIAN_POINT('',(12.477757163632,23.2268450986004,42.0009032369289));
#952=CARTESIAN_POINT('',(12.2346085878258,22.5585146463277,42.0723736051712));
#953=CARTESIAN_POINT('',(12.0997009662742,22.2295597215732,42.1114599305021));
#954=CARTESIAN_POINT('',(11.8020314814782,21.5793649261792,42.1958593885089));
#955=CARTESIAN_POINT('',(11.6388874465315,21.2583109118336,42.2412560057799));
#956=CARTESIAN_POINT('',(11.2873262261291,20.6310600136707,42.3365521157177));
#957=CARTESIAN_POINT('',(11.0989088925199,20.3248632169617,42.3864516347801));
#958=CARTESIAN_POINT('',(10.6980606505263,19.7291856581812,42.4893930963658));
#959=CARTESIAN_POINT('',(10.4856302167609,19.4397045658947,42.5424349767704));
#960=CARTESIAN_POINT('',(10.0379916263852,18.8790573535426,42.6502750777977));
#961=CARTESIAN_POINT('',(9.80277298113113,18.6078997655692,42.7050740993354));
#962=CARTESIAN_POINT('',(9.30171889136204,18.0757584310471,42.8170597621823));
#963=CARTESIAN_POINT('',(9.03506018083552,17.8155515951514,42.8742580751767));
#964=CARTESIAN_POINT('',(8.48064107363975,17.318634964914,42.9873579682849));
#965=CARTESIAN_POINT('',(8.19288991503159,17.0819149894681,43.0432601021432));
#966=CARTESIAN_POINT('',(7.59792402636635,16.6334295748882,43.1522565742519));
#967=CARTESIAN_POINT('',(7.29070407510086,16.4216708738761,43.2053501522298));
#968=CARTESIAN_POINT('',(6.65885587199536,16.0247517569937,43.3072308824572));
#969=CARTESIAN_POINT('',(6.3342278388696,15.8395910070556,43.3560180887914));
#970=CARTESIAN_POINT('',(5.66979054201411,15.4973632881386,43.4479014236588));
#971=CARTESIAN_POINT('',(5.32998442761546,15.3402905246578,43.490998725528));
#972=CARTESIAN_POINT('',(4.63748652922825,15.0555196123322,43.5702809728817));
#973=CARTESIAN_POINT('',(4.28479468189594,14.9278216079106,43.6064658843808));
#974=CARTESIAN_POINT('',(3.56918508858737,14.7029817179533,43.670861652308));
#975=CARTESIAN_POINT('',(3.20626999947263,14.6058319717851,43.6990745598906));
#976=CARTESIAN_POINT('',(2.47288807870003,14.4429721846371,43.7467032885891));
#977=CARTESIAN_POINT('',(2.10242154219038,14.3772609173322,43.7661194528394));
#978=CARTESIAN_POINT('',(1.37182635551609,14.2799206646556,43.794983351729));
#979=CARTESIAN_POINT('',(1.01188005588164,14.2470288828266,43.8048001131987));
#980=CARTESIAN_POINT('',(0.290371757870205,14.2111121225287,43.8155231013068));
#981=CARTESIAN_POINT('',(-0.0711901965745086,14.2080863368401,43.8164295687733));
#982=CARTESIAN_POINT('',(-0.793205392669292,14.2319282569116,43.8093070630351));
#983=CARTESIAN_POINT('',(-1.15365872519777,14.2587934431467,43.8012788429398));
#984=CARTESIAN_POINT('',(-1.87081504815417,14.3421601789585,43.7765120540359));
#985=CARTESIAN_POINT('',(-2.22751806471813,14.3986615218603,43.7597735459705));
#986=CARTESIAN_POINT('',(-2.92691346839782,14.5392377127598,43.7185025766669));
#987=CARTESIAN_POINT('',(-3.2697419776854,14.6226888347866,43.6941467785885));
#988=CARTESIAN_POINT('',(-3.94700871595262,14.8167468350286,43.6381806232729));
#989=CARTESIAN_POINT('',(-4.28144703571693,14.9273534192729,43.6065703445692));
#990=CARTESIAN_POINT('',(-4.93974509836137,15.1748209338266,43.5369120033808));
#991=CARTESIAN_POINT('',(-5.26360531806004,15.3116806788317,43.4988642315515));
#992=CARTESIAN_POINT('',(-5.89874691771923,15.6106124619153,43.4172953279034));
#993=CARTESIAN_POINT('',(-6.21002838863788,15.7726843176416,43.373774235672));
#994=CARTESIAN_POINT('',(-6.80933853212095,16.1158285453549,43.2836724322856));
#995=CARTESIAN_POINT('',(-7.09777957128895,16.2962145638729,43.2372168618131));
#996=CARTESIAN_POINT('',(-7.65958886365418,16.678587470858,43.1412351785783));
#997=CARTESIAN_POINT('',(-7.93295139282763,16.88058247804,43.0917079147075));
#998=CARTESIAN_POINT('',(-8.46302368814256,17.3048987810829,42.9907461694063));
#999=CARTESIAN_POINT('',(-8.71973400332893,17.5272194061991,42.939311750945));
#1000=CARTESIAN_POINT('',(-9.21516471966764,17.990925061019,42.8357213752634));
#1001=CARTESIAN_POINT('',(-9.45388450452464,18.232310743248,42.7835653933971));
#1002=CARTESIAN_POINT('',(-9.68298069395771,18.4825735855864,42.7316523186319));
#1003=B_SPLINE_CURVE_WITH_KNOTS('',3,(#849,#850,#851,#852,#853,#854,#855,#856,#857,#858,#859,
#860,#861,#862,#863,#864,#865,#866,#867,#868,#869,#870,#871,#872,#873,#874,#875,#876,#877,#878,
#879,#880,#881,#882,#883,#884,#885,#886,#887,#888,#889,#890,#891,#892,#893,#894,#895,#896,#897,
#898,#899,#900,#901,#902,#903,#904,#905,#906,#907,#908,#909,#910,#911,#912,#913,#914,#915,#916,
#917,#918,#919,#920,#921,#922,#923,#924,#925,#926,#927,#928,#929,#930,#931,#932,#933,#934,#935,
#936,#937,#938,#939,#940,#941,#942,#943,#944,#945,#946,#947,#948,#949,#950,#951,#952,#953,#954,
#955,#956,#957,#958,#959,#960,#961,#962,#963,#964,#965,#966,#967,#968,#969,#970,#971,#972,#973,
#974,#975,#976,#977,#978,#979,#980,#981,#982,#983,#984,#985,#986,#987,#988,#989,#990,#991,#992,
#993,#994,#995,#996,#997,#998,#999,#1000,#1001,#1002),.UNSPECIFIED.,.T.,.F.,(4,2,2,2,2,2,2,2,2,
2,2,2,2,2,2,2,2,2,2,2,2,2,2,2,2,2,2,2,2,2,2,2,2,2,2,2,2,2,2,2,2,2,2,2,2,2,2,2,2,2,2,2,2,2,2,2,2,
2,2,2,2,2,2,2,2,2,2,2,2,2,2,2,2,2,2,2,4),(0.,1.11784168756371,2.23574412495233,3.35384749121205,
4.47190565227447,5.5916811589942,6.71146209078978,7.83094619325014,8.95039799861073,
10.0371444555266,11.1238699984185,12.2105661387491,13.2972635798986,14.3695355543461,
15.4417939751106,16.5140311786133,17.5866521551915,18.6947452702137,19.8028641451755,
20.911372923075,22.0195044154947,23.1566242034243,24.2937685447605,25.4307620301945,
26.56771923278,27.6775501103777,28.7873666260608,29.8969261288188,31.0064546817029,
32.0725488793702,33.1386116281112,34.2046646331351,35.2707319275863,36.3380494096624,
37.4053626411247,38.4726798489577,39.5403785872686,40.6499723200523,41.7595924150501,
42.8696110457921,43.9792475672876,45.1164206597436,46.2536168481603,47.3906073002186,
48.5275602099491,49.6358220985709,50.7440671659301,51.8521072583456,52.9601264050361,
54.0319138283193,55.1036744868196,56.1755160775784,57.2473810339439,58.3350861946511,
59.4227977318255,60.5104877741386,61.5986808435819,62.7281811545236,63.8571896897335,
64.9865022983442,66.1158007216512,67.2448659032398,68.3739366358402,69.5027165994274,
70.6314525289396,71.7148571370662,72.7982324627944,73.8815164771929,74.9647929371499,
76.0246064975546,77.0844085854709,78.144162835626,79.2039094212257,80.2329593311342,
81.2623972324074,82.2918011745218,83.3212403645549),.UNSPECIFIED.);
#1004=CARTESIAN_POINT('',(-9.68298069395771,18.4825735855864,42.7316523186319));
#1005=VERTEX_POINT('',#1004);
#1006=EDGE_CURVE('E50',#1005,#1005,#1003,.T.);
#1007=ORIENTED_EDGE('',*,*,#1006,.T.);
#1008=EDGE_LOOP('',(#1007));
#1009=FACE_BOUND('',#1008,.T.);
#1010=CARTESIAN_POINT('',(0.,1.57479999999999,0.));
#1011=DIRECTION('',(0.,1.,0.));
#1012=DIRECTION('',(0.,0.,1.));
#1013=AXIS2_PLACEMENT_3D('',#1010,#1011,#1012);
#1014=CIRCLE('',#1013,43.815);
#1015=CARTESIAN_POINT('',(0.,1.57479999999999,43.815));
#1016=VERTEX_POINT('',#1015);
#1017=EDGE_CURVE('E1183',#1016,#1016,#1014,.T.);
#1018=ORIENTED_EDGE('',*,*,#1017,.T.);
#1019=EDGE_LOOP('',(#1018));
#1020=FACE_BOUND('',#1019,.T.);
#1021=CARTESIAN_POINT('',(0.,55.88,0.));
#1022=DIRECTION('',(0.,1.,0.));
#1023=DIRECTION('',(0.,0.,1.));
#1024=AXIS2_PLACEMENT_3D('',#1021,#1022,#1023);
#1025=CIRCLE('',#1024,43.815);
#1026=CARTESIAN_POINT('',(0.,55.88,43.815));
#1027=VERTEX_POINT('',#1026);
#1028=EDGE_CURVE('E1179',#1027,#1027,#1025,.T.);
#1029=ORIENTED_EDGE('',*,*,#1028,.F.);
#1030=EDGE_LOOP('',(#1029));
#1031=FACE_BOUND('',#1030,.T.);
#1032=ADVANCED_FACE('F1145',(#848,#1009,#1020,#1031),#687,.T.);
#1033=CARTESIAN_POINT('',(0.,0.,0.));
#1034=DIRECTION('',(0.,1.,0.));
#1035=DIRECTION('',(0.,0.,1.));
#1036=AXIS2_PLACEMENT_3D('',#1033,#1034,#1035);
#1037=PLANE('',#1036);
#1038=CARTESIAN_POINT('',(0.,0.,0.));
#1039=DIRECTION('',(0.,1.,0.));
#1040=DIRECTION('',(0.,0.,1.));
#1041=AXIS2_PLACEMENT_3D('',#1038,#1039,#1040);
#1042=CIRCLE('',#1041,42.2402);
#1043=CARTESIAN_POINT('',(0.,0.,42.2402));
#1044=VERTEX_POINT('',#1043);
#1045=EDGE_CURVE('E1187',#1044,#1044,#1042,.F.);
#1046=ORIENTED_EDGE('',*,*,#1045,.T.);
#1047=EDGE_LOOP('',(#1046));
#1048=FACE_BOUND('',#1047,.T.);
#1049=ADVANCED_FACE('F1150',(#1048),#1037,.F.);
#1050=CARTESIAN_POINT('',(-30.226,55.88,0.));
#1051=DIRECTION('',(0.,1.,0.));
#1052=DIRECTION('',(0.,0.,1.));
#1053=AXIS2_PLACEMENT_3D('',#1050,#1051,#1052);
#1054=PLANE('',#1053);
#1055=CARTESIAN_POINT('',(0.,55.88,0.));
#1056=DIRECTION('',(0.,-1.,0.));
#1057=DIRECTION('',(0.,0.,-1.));
#1058=AXIS2_PLACEMENT_3D('',#1055,#1056,#1057);
#1059=CIRCLE('',#1058,30.226);
#1060=CARTESIAN_POINT('',(0.,55.88,-30.226));
#1061=VERTEX_POINT('',#1060);
#1062=EDGE_CURVE('E1161',#1061,#1061,#1059,.T.);
#1063=ORIENTED_EDGE('',*,*,#1062,.T.);
#1064=EDGE_LOOP('',(#1063));
#1065=FACE_BOUND('',#1064,.T.);
#1066=ORIENTED_EDGE('',*,*,#1028,.T.);
#1067=EDGE_LOOP('',(#1066));
#1068=FACE_BOUND('',#1067,.T.);
#1069=ADVANCED_FACE('F2357',(#1065,#1068),#1054,.T.);
#1070=CARTESIAN_POINT('',(-43.815,56.134,0.));
#1071=DIRECTION('',(0.,-1.,0.));
#1072=DIRECTION('',(0.,0.,-1.));
#1073=AXIS2_PLACEMENT_3D('',#1070,#1071,#1072);
#1074=PLANE('',#1073);
#1075=CARTESIAN_POINT('',(0.,56.134,0.));
#1076=DIRECTION('',(0.,-1.,0.));
#1077=DIRECTION('',(0.,0.,-1.));
#1078=AXIS2_PLACEMENT_3D('',#1075,#1076,#1077);
#1079=CIRCLE('',#1078,43.815);
#1080=CARTESIAN_POINT('',(0.,56.134,-43.815));
#1081=VERTEX_POINT('',#1080);
#1082=EDGE_CURVE('E1290',#1081,#1081,#1079,.T.);
#1083=ORIENTED_EDGE('',*,*,#1082,.T.);
#1084=EDGE_LOOP('',(#1083));
#1085=FACE_BOUND('',#1084,.T.);
#1086=CARTESIAN_POINT('',(0.,56.134,0.));
#1087=DIRECTION('',(0.,-1.,0.));
#1088=DIRECTION('',(0.,0.,-1.));
#1089=AXIS2_PLACEMENT_3D('',#1086,#1087,#1088);
#1090=CIRCLE('',#1089,30.226);
#1091=CARTESIAN_POINT('',(0.,56.134,-30.226));
#1092=VERTEX_POINT('',#1091);
#1093=EDGE_CURVE('E1167',#1092,#1092,#1090,.T.);
#1094=ORIENTED_EDGE('',*,*,#1093,.F.);
#1095=EDGE_LOOP('',(#1094));
#1096=FACE_BOUND('',#1095,.T.);
#1097=ADVANCED_FACE('F2347',(#1085,#1096),#1074,.T.);
#1098=CARTESIAN_POINT('',(0.,0.,0.));
#1099=DIRECTION('',(0.,-1.,0.));
#1100=DIRECTION('',(0.,0.,-1.));
#1101=AXIS2_PLACEMENT_3D('',#1098,#1099,#1100);
#1102=CYLINDRICAL_SURFACE('',#1101,30.226);
#1103=ORIENTED_EDGE('',*,*,#1093,.T.);
#1104=EDGE_LOOP('',(#1103));
#1105=FACE_BOUND('',#1104,.T.);
#1106=ORIENTED_EDGE('',*,*,#1062,.F.);
#1107=EDGE_LOOP('',(#1106));
#1108=FACE_BOUND('',#1107,.T.);
#1109=ADVANCED_FACE('F2342',(#1105,#1108),#1102,.T.);
#1110=EDGE_CURVE('E1162',#664,#508,#186,.T.);
#1111=ORIENTED_EDGE('',*,*,#1110,.T.);
#1112=ORIENTED_EDGE('',*,*,#509,.T.);
#1113=EDGE_CURVE('E1319',#504,#348,#186,.T.);
#1114=ORIENTED_EDGE('',*,*,#1113,.T.);
#1115=ORIENTED_EDGE('',*,*,#349,.T.);
#1116=EDGE_CURVE('E1311',#344,#188,#186,.T.);
#1117=ORIENTED_EDGE('',*,*,#1116,.T.);
#1118=ORIENTED_EDGE('',*,*,#189,.T.);
#1119=EDGE_CURVE('E1302',#179,#38,#186,.T.);
#1120=ORIENTED_EDGE('',*,*,#1119,.T.);
#1121=ORIENTED_EDGE('',*,*,#667,.T.);
#1122=EDGE_LOOP('',(#1111,#1112,#1114,#1115,#1117,#1118,#1120,#1121));
#1123=FACE_BOUND('',#1122,.T.);
#1124=ORIENTED_EDGE('',*,*,#1082,.F.);
#1125=EDGE_LOOP('',(#1124));
#1126=FACE_BOUND('',#1125,.T.);
#1127=ADVANCED_FACE('F968',(#1123,#1126),#687,.T.);
#1128=CARTESIAN_POINT('',(0.,0.,0.));
#1129=DIRECTION('',(0.,-1.,0.));
#1130=DIRECTION('',(0.,0.,-1.));
#1131=AXIS2_PLACEMENT_3D('',#1128,#1129,#1130);
#1132=CYLINDRICAL_SURFACE('',#1131,15.875);
#1133=CARTESIAN_POINT('',(0.,139.3952,0.));
#1134=DIRECTION('',(0.,1.,0.));
#1135=DIRECTION('',(0.,0.,1.));
#1136=AXIS2_PLACEMENT_3D('',#1133,#1134,#1135);
#1137=CIRCLE('',#1136,15.875);
#1138=CARTESIAN_POINT('',(0.,139.3952,15.875));
#1139=VERTEX_POINT('',#1138);
#1140=EDGE_CURVE('E1195',#1139,#1139,#1137,.F.);
#1141=ORIENTED_EDGE('',*,*,#1140,.T.);
#1142=EDGE_LOOP('',(#1141));
#1143=FACE_BOUND('',#1142,.T.);
#1144=ORIENTED_EDGE('',*,*,#678,.F.);
#1145=EDGE_LOOP('',(#1144));
#1146=FACE_BOUND('',#1145,.T.);
#1147=ADVANCED_FACE('F1274',(#1143,#1146),#1132,.T.);
#1148=CARTESIAN_POINT('',(0.,140.97,0.));
#1149=DIRECTION('',(0.,1.,0.));
#1150=DIRECTION('',(0.,0.,1.));
#1151=AXIS2_PLACEMENT_3D('',#1148,#1149,#1150);
#1152=PLANE('',#1151);
#1153=CARTESIAN_POINT('',(0.,140.97,0.));
#1154=DIRECTION('',(0.,1.,0.));
#1155=DIRECTION('',(0.,0.,1.));
#1156=AXIS2_PLACEMENT_3D('',#1153,#1154,#1155);
#1157=CIRCLE('',#1156,14.3002);
#1158=CARTESIAN_POINT('',(0.,140.97,14.3002));
#1159=VERTEX_POINT('',#1158);
#1160=EDGE_CURVE('E1191',#1159,#1159,#1157,.T.);
#1161=ORIENTED_EDGE('',*,*,#1160,.T.);
#1162=EDGE_LOOP('',(#1161));
#1163=FACE_BOUND('',#1162,.T.);
#1164=CARTESIAN_POINT('',(0.,140.97,0.));
#1165=DIRECTION('',(0.,1.,0.));
#1166=DIRECTION('',(0.,0.,1.));
#1167=AXIS2_PLACEMENT_3D('',#1164,#1165,#1166);
#1168=CIRCLE('',#1167,11.1125);
#1169=CARTESIAN_POINT('',(0.,140.97,11.1125));
#1170=VERTEX_POINT('',#1169);
#1171=EDGE_CURVE('E1283',#1170,#1170,#1168,.T.);
#1172=ORIENTED_EDGE('',*,*,#1171,.F.);
#1173=EDGE_LOOP('',(#1172));
#1174=FACE_BOUND('',#1173,.T.);
#1175=ADVANCED_FACE('F1269',(#1163,#1174),#1152,.T.);
#1176=CARTESIAN_POINT('',(0.,140.97,0.));
#1177=DIRECTION('',(0.,1.,0.));
#1178=DIRECTION('',(0.,0.,1.));
#1179=AXIS2_PLACEMENT_3D('',#1176,#1177,#1178);
#1180=CONICAL_SURFACE('',#1179,11.1125,0.78539816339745);
#1181=CARTESIAN_POINT('',(0.,139.7,0.));
#1182=DIRECTION('',(0.,1.,0.));
#1183=DIRECTION('',(0.,0.,1.));
#1184=AXIS2_PLACEMENT_3D('',#1181,#1182,#1183);
#1185=CIRCLE('',#1184,9.8425);
#1186=CARTESIAN_POINT('',(0.,139.7,9.8425));
#1187=VERTEX_POINT('',#1186);
#1188=EDGE_CURVE('E1280',#1187,#1187,#1185,.T.);
#1189=ORIENTED_EDGE('',*,*,#1188,.F.);
#1190=EDGE_LOOP('',(#1189));
#1191=FACE_BOUND('',#1190,.T.);
#1192=ORIENTED_EDGE('',*,*,#1171,.T.);
#1193=EDGE_LOOP('',(#1192));
#1194=FACE_BOUND('',#1193,.T.);
#1195=ADVANCED_FACE('F1266',(#1191,#1194),#1180,.F.);
#1196=CARTESIAN_POINT('',(0.,139.7,0.));
#1197=DIRECTION('',(0.,1.,0.));
#1198=DIRECTION('',(0.,0.,1.));
#1199=AXIS2_PLACEMENT_3D('',#1196,#1197,#1198);
#1200=PLANE('',#1199);
#1201=CARTESIAN_POINT('',(0.,139.7,0.));
#1202=DIRECTION('',(0.,1.,0.));
#1203=DIRECTION('',(0.,0.,1.));
#1204=AXIS2_PLACEMENT_3D('',#1201,#1202,#1203);
#1205=CIRCLE('',#1204,9.525);
#1206=CARTESIAN_POINT('',(0.,139.7,9.525));
#1207=VERTEX_POINT('',#1206);
#1208=EDGE_CURVE('E1199',#1207,#1207,#1205,.T.);
#1209=ORIENTED_EDGE('',*,*,#1208,.F.);
#1210=EDGE_LOOP('',(#1209));
#1211=FACE_BOUND('',#1210,.T.);
#1212=ORIENTED_EDGE('',*,*,#1188,.T.);
#1213=EDGE_LOOP('',(#1212));
#1214=FACE_BOUND('',#1213,.T.);
#1215=ADVANCED_FACE('F1263',(#1211,#1214),#1200,.T.);
#1216=CARTESIAN_POINT('',(0.,1.57479999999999,0.));
#1217=DIRECTION('',(0.,1.,0.));
#1218=DIRECTION('',(0.,0.,1.));
#1219=AXIS2_PLACEMENT_3D('',#1216,#1217,#1218);
#1220=CONICAL_SURFACE('',#1219,43.815,0.78539816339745);
#1221=ORIENTED_EDGE('',*,*,#1045,.F.);
#1222=EDGE_LOOP('',(#1221));
#1223=FACE_BOUND('',#1222,.T.);
#1224=ORIENTED_EDGE('',*,*,#1017,.F.);
#1225=EDGE_LOOP('',(#1224));
#1226=FACE_BOUND('',#1225,.T.);
#1227=ADVANCED_FACE('F1265',(#1223,#1226),#1220,.T.);
#1228=CARTESIAN_POINT('',(0.,140.97,0.));
#1229=DIRECTION('',(0.,-1.,0.));
#1230=DIRECTION('',(0.,0.,-1.));
#1231=AXIS2_PLACEMENT_3D('',#1228,#1229,#1230);
#1232=CONICAL_SURFACE('',#1231,14.3002,0.785398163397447);
#1233=ORIENTED_EDGE('',*,*,#1140,.F.);
#1234=EDGE_LOOP('',(#1233));
#1235=FACE_BOUND('',#1234,.T.);
#1236=ORIENTED_EDGE('',*,*,#1160,.F.);
#1237=EDGE_LOOP('',(#1236));
#1238=FACE_BOUND('',#1237,.T.);
#1239=ADVANCED_FACE('F1261',(#1235,#1238),#1232,.T.);
#1240=CARTESIAN_POINT('',(0.,112.759231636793,0.));
#1241=DIRECTION('',(0.,1.,0.));
#1242=DIRECTION('',(0.,0.,1.));
#1243=AXIS2_PLACEMENT_3D('',#1240,#1241,#1242);
#1244=CYLINDRICAL_SURFACE('',#1243,9.525);
#1245=CARTESIAN_POINT('',(0.,139.827,0.));
#1246=DIRECTION('',(0.,1.,0.));
#1247=DIRECTION('',(0.,0.,1.));
#1248=AXIS2_PLACEMENT_3D('',#1245,#1246,#1247);
#1249=CIRCLE('',#1248,9.525);
#1250=CARTESIAN_POINT('',(0.,139.827,9.525));
#1251=VERTEX_POINT('',#1250);
#1252=EDGE_CURVE('E1207',#1251,#1251,#1249,.F.);
#1253=ORIENTED_EDGE('',*,*,#1252,.T.);
#1254=EDGE_LOOP('',(#1253));
#1255=FACE_BOUND('',#1254,.T.);
#1256=ORIENTED_EDGE('',*,*,#1208,.T.);
#1257=EDGE_LOOP('',(#1256));
#1258=FACE_BOUND('',#1257,.T.);
#1259=ADVANCED_FACE('F1257',(#1255,#1258),#1244,.T.);
#1260=CARTESIAN_POINT('',(0.,140.97,0.));
#1261=DIRECTION('',(0.,1.,0.));
#1262=DIRECTION('',(0.,0.,1.));
#1263=AXIS2_PLACEMENT_3D('',#1260,#1261,#1262);
#1264=PLANE('',#1263);
#1265=CARTESIAN_POINT('',(-3.175,140.97,0.));
#1266=DIRECTION('',(0.,1.,0.));
#1267=DIRECTION('',(0.,0.,1.));
#1268=AXIS2_PLACEMENT_3D('',#1265,#1266,#1267);
#1269=CIRCLE('',#1268,0.9652);
#1270=CARTESIAN_POINT('',(-3.175,140.97,-0.9652));
#1271=VERTEX_POINT('',#1270);
#1272=CARTESIAN_POINT('',(-3.175,140.97,0.9652));
#1273=VERTEX_POINT('',#1272);
#1274=EDGE_CURVE('E1549',#1271,#1273,#1269,.T.);
#1275=ORIENTED_EDGE('',*,*,#1274,.F.);
#1276=DIRECTION('',(-1.,0.,0.));
#1277=VECTOR('',#1276,1.);
#1278=CARTESIAN_POINT('',(3.175,140.97,-0.9652));
#1279=LINE('',#1278,#1277);
#1280=CARTESIAN_POINT('',(3.175,140.97,-0.9652));
#1281=VERTEX_POINT('',#1280);
#1282=EDGE_CURVE('E1555',#1281,#1271,#1279,.T.);
#1283=ORIENTED_EDGE('',*,*,#1282,.F.);
#1284=CARTESIAN_POINT('',(3.175,140.97,0.));
#1285=DIRECTION('',(0.,1.,0.));
#1286=DIRECTION('',(0.,0.,1.));
#1287=AXIS2_PLACEMENT_3D('',#1284,#1285,#1286);
#1288=CIRCLE('',#1287,0.9652);
#1289=CARTESIAN_POINT('',(3.175,140.97,0.965199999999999));
#1290=VERTEX_POINT('',#1289);
#1291=EDGE_CURVE('E1548',#1290,#1281,#1288,.T.);
#1292=ORIENTED_EDGE('',*,*,#1291,.F.);
#1293=DIRECTION('',(1.,0.,0.));
#1294=VECTOR('',#1293,1.);
#1295=CARTESIAN_POINT('',(-3.175,140.97,0.9652));
#1296=LINE('',#1295,#1294);
#1297=EDGE_CURVE('E1546',#1273,#1290,#1296,.T.);
#1298=ORIENTED_EDGE('',*,*,#1297,.F.);
#1299=EDGE_LOOP('',(#1275,#1283,#1292,#1298));
#1300=FACE_BOUND('',#1299,.T.);
#1301=CARTESIAN_POINT('',(0.,140.97,0.));
#1302=DIRECTION('',(0.,1.,0.));
#1303=DIRECTION('',(0.,0.,1.));
#1304=AXIS2_PLACEMENT_3D('',#1301,#1302,#1303);
#1305=CIRCLE('',#1304,8.382);
#1306=CARTESIAN_POINT('',(0.,140.97,8.382));
#1307=VERTEX_POINT('',#1306);
#1308=EDGE_CURVE('E1203',#1307,#1307,#1305,.T.);
#1309=ORIENTED_EDGE('',*,*,#1308,.T.);
#1310=EDGE_LOOP('',(#1309));
#1311=FACE_BOUND('',#1310,.T.);
#1312=ADVANCED_FACE('F1254',(#1300,#1311),#1264,.T.);
#1313=CARTESIAN_POINT('',(0.,139.827,0.));
#1314=DIRECTION('',(0.,1.,0.));
#1315=DIRECTION('',(0.,0.,1.));
#1316=AXIS2_PLACEMENT_3D('',#1313,#1314,#1315);
#1317=TOROIDAL_SURFACE('',#1316,8.382,1.143);
#1318=ORIENTED_EDGE('',*,*,#1252,.F.);
#1319=EDGE_LOOP('',(#1318));
#1320=FACE_BOUND('',#1319,.T.);
#1321=ORIENTED_EDGE('',*,*,#1308,.F.);
#1322=EDGE_LOOP('',(#1321));
#1323=FACE_BOUND('',#1322,.T.);
#1324=ADVANCED_FACE('F1242',(#1320,#1323),#1317,.T.);
#1325=CARTESIAN_POINT('',(-3.175,140.97,0.));
#1326=DIRECTION('',(0.,1.,0.));
#1327=DIRECTION('',(0.,0.,1.));
#1328=AXIS2_PLACEMENT_3D('',#1325,#1326,#1327);
#1329=CONICAL_SURFACE('',#1328,0.9652,0.0174532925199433);
#1330=ORIENTED_EDGE('',*,*,#1274,.T.);
#1331=DIRECTION('',(0.,0.999847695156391,0.0174524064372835));
#1332=VECTOR('',#1331,1.);
#1333=CARTESIAN_POINT('',(-3.175,140.97,0.9652));
#1334=LINE('',#1333,#1332);
#1335=CARTESIAN_POINT('',(-3.175,137.668,0.907563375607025));
#1336=VERTEX_POINT('',#1335);
#1337=EDGE_CURVE('E1563',#1336,#1273,#1334,.T.);
#1338=ORIENTED_EDGE('',*,*,#1337,.F.);
#1339=CARTESIAN_POINT('',(-3.175,137.668,0.));
#1340=DIRECTION('',(0.,1.,0.));
#1341=DIRECTION('',(0.,0.,1.));
#1342=AXIS2_PLACEMENT_3D('',#1339,#1340,#1341);
#1343=CIRCLE('',#1342,0.907563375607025);
#1344=CARTESIAN_POINT('',(-3.175,137.668,-0.907563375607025));
#1345=VERTEX_POINT('',#1344);
#1346=EDGE_CURVE('E1561',#1345,#1336,#1343,.T.);
#1347=ORIENTED_EDGE('',*,*,#1346,.F.);
#1348=DIRECTION('',(0.,0.999847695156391,-0.0174524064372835));
#1349=VECTOR('',#1348,1.);
#1350=CARTESIAN_POINT('',(-3.175,140.97,-0.9652));
#1351=LINE('',#1350,#1349);
#1352=EDGE_CURVE('E1286',#1345,#1271,#1351,.T.);
#1353=ORIENTED_EDGE('',*,*,#1352,.T.);
#1354=EDGE_LOOP('',(#1330,#1338,#1347,#1353));
#1355=FACE_BOUND('',#1354,.T.);
#1356=ADVANCED_FACE('F1238',(#1355),#1329,.F.);
#1357=CARTESIAN_POINT('',(3.175,140.97,-0.9652));
#1358=DIRECTION('',(0.,-0.0174524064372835,-0.999847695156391));
#1359=DIRECTION('',(0.,0.999847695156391,-0.0174524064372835));
#1360=AXIS2_PLACEMENT_3D('',#1357,#1358,#1359);
#1361=PLANE('',#1360);
#1362=ORIENTED_EDGE('',*,*,#1282,.T.);
#1363=ORIENTED_EDGE('',*,*,#1352,.F.);
#1364=DIRECTION('',(-1.,0.,0.));
#1365=VECTOR('',#1364,1.);
#1366=CARTESIAN_POINT('',(-3.175,137.668,-0.907563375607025));
#1367=LINE('',#1366,#1365);
#1368=CARTESIAN_POINT('',(3.175,137.668,-0.907563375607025));
#1369=VERTEX_POINT('',#1368);
#1370=EDGE_CURVE('E1567',#1369,#1345,#1367,.T.);
#1371=ORIENTED_EDGE('',*,*,#1370,.F.);
#1372=DIRECTION('',(0.,0.999847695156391,-0.0174524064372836));
#1373=VECTOR('',#1372,1.);
#1374=CARTESIAN_POINT('',(3.175,140.97,-0.9652));
#1375=LINE('',#1374,#1373);
#1376=EDGE_CURVE('E1292',#1369,#1281,#1375,.T.);
#1377=ORIENTED_EDGE('',*,*,#1376,.T.);
#1378=EDGE_LOOP('',(#1362,#1363,#1371,#1377));
#1379=FACE_BOUND('',#1378,.T.);
#1380=ADVANCED_FACE('F1241',(#1379),#1361,.F.);
#1381=CARTESIAN_POINT('',(3.175,140.97,0.));
#1382=DIRECTION('',(0.,1.,0.));
#1383=DIRECTION('',(0.,0.,1.));
#1384=AXIS2_PLACEMENT_3D('',#1381,#1382,#1383);
#1385=CONICAL_SURFACE('',#1384,0.9652,0.0174532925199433);
#1386=ORIENTED_EDGE('',*,*,#1291,.T.);
#1387=ORIENTED_EDGE('',*,*,#1376,.F.);
#1388=CARTESIAN_POINT('',(3.175,137.668,0.));
#1389=DIRECTION('',(0.,1.,0.));
#1390=DIRECTION('',(0.,0.,1.));
#1391=AXIS2_PLACEMENT_3D('',#1388,#1389,#1390);
#1392=CIRCLE('',#1391,0.907563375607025);
#1393=CARTESIAN_POINT('',(3.175,137.668,0.907563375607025));
#1394=VERTEX_POINT('',#1393);
#1395=EDGE_CURVE('E1577',#1394,#1369,#1392,.T.);
#1396=ORIENTED_EDGE('',*,*,#1395,.F.);
#1397=DIRECTION('',(0.,0.999847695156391,0.0174524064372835));
#1398=VECTOR('',#1397,1.);
#1399=CARTESIAN_POINT('',(3.175,140.97,0.965199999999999));
#1400=LINE('',#1399,#1398);
#1401=EDGE_CURVE('E1566',#1394,#1290,#1400,.T.);
#1402=ORIENTED_EDGE('',*,*,#1401,.T.);
#1403=EDGE_LOOP('',(#1386,#1387,#1396,#1402));
#1404=FACE_BOUND('',#1403,.T.);
#1405=ADVANCED_FACE('F1246',(#1404),#1385,.F.);
#1406=CARTESIAN_POINT('',(-3.175,140.97,0.9652));
#1407=DIRECTION('',(0.,-0.0174524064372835,0.999847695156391));
#1408=DIRECTION('',(0.,-0.999847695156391,-0.0174524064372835));
#1409=AXIS2_PLACEMENT_3D('',#1406,#1407,#1408);
#1410=PLANE('',#1409);
#1411=ORIENTED_EDGE('',*,*,#1297,.T.);
#1412=ORIENTED_EDGE('',*,*,#1401,.F.);
#1413=DIRECTION('',(1.,0.,0.));
#1414=VECTOR('',#1413,1.);
#1415=CARTESIAN_POINT('',(-3.175,137.668,0.907563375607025));
#1416=LINE('',#1415,#1414);
#1417=EDGE_CURVE('E1295',#1336,#1394,#1416,.T.);
#1418=ORIENTED_EDGE('',*,*,#1417,.F.);
#1419=ORIENTED_EDGE('',*,*,#1337,.T.);
#1420=EDGE_LOOP('',(#1411,#1412,#1418,#1419));
#1421=FACE_BOUND('',#1420,.T.);
#1422=ADVANCED_FACE('F1236',(#1421),#1410,.F.);
#1423=CARTESIAN_POINT('',(-3.175,137.668,0.));
#1424=DIRECTION('',(0.,1.,0.));
#1425=DIRECTION('',(0.,0.,1.));
#1426=AXIS2_PLACEMENT_3D('',#1423,#1424,#1425);
#1427=PLANE('',#1426);
#1428=ORIENTED_EDGE('',*,*,#1346,.T.);
#1429=ORIENTED_EDGE('',*,*,#1417,.T.);
#1430=ORIENTED_EDGE('',*,*,#1395,.T.);
#1431=ORIENTED_EDGE('',*,*,#1370,.T.);
#1432=EDGE_LOOP('',(#1428,#1429,#1430,#1431));
#1433=FACE_BOUND('',#1432,.T.);
#1434=ADVANCED_FACE('F1231',(#1433),#1427,.T.);
#1435=CARTESIAN_POINT('',(25.4590261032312,97.79,25.4590261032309));
#1436=DIRECTION('',(0.,-1.,0.));
#1437=DIRECTION('',(0.,0.,-1.));
#1438=AXIS2_PLACEMENT_3D('',#1435,#1436,#1437);
#1439=CYLINDRICAL_SURFACE('',#1438,7.9375);
#1440=CARTESIAN_POINT('',(25.4590261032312,74.93,25.4590261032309));
#1441=DIRECTION('',(0.,1.,0.));
#1442=DIRECTION('',(0.,0.,1.));
#1443=AXIS2_PLACEMENT_3D('',#1440,#1441,#1442);
#1444=CIRCLE('',#1443,7.9375);
#1445=EDGE_CURVE('E1448',#645,#532,#1444,.T.);
#1446=ORIENTED_EDGE('',*,*,#1445,.F.);
#1447=ORIENTED_EDGE('',*,*,#646,.F.);
#1448=EDGE_LOOP('',(#1446,#1447));
#1449=FACE_BOUND('',#1448,.T.);
#1450=ADVANCED_FACE('F1225',(#1449),#1439,.F.);
#1451=CARTESIAN_POINT('',(25.4590261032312,74.93,25.4590261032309));
#1452=DIRECTION('',(0.,1.,0.));
#1453=DIRECTION('',(0.,0.,1.));
#1454=AXIS2_PLACEMENT_3D('',#1451,#1452,#1453);
#1455=PLANE('',#1454);
#1456=DIRECTION('',(0.963674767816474,0.,0.267078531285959));
#1457=VECTOR('',#1456,1.);
#1458=CARTESIAN_POINT('',(33.591654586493,74.93,33.5916545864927));
#1459=LINE('',#1458,#1457);
#1460=CARTESIAN_POINT('',(20.9694445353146,74.93,30.0934605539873));
#1461=VERTEX_POINT('',#1460);
#1462=EDGE_CURVE('E1491',#1461,#523,#1459,.T.);
#1463=ORIENTED_EDGE('',*,*,#1462,.F.);
#1464=DIRECTION('',(0.274119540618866,0.,0.96169562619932));
#1465=VECTOR('',#1464,1.);
#1466=CARTESIAN_POINT('',(19.2006973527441,74.93,23.888151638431));
#1467=LINE('',#1466,#1465);
#1468=CARTESIAN_POINT('',(19.2006973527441,74.93,23.888151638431));
#1469=VERTEX_POINT('',#1468);
#1470=EDGE_CURVE('E1498',#1469,#1461,#1467,.T.);
#1471=ORIENTED_EDGE('',*,*,#1470,.F.);
#1472=DIRECTION('',(-0.695793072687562,0.,0.718242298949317));
#1473=VECTOR('',#1472,1.);
#1474=CARTESIAN_POINT('',(23.6902789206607,74.93,19.2537171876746));
#1475=LINE('',#1474,#1473);
#1476=CARTESIAN_POINT('',(23.6902789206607,74.93,19.2537171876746));
#1477=VERTEX_POINT('',#1476);
#1478=EDGE_CURVE('E1505',#1477,#1469,#1475,.T.);
#1479=ORIENTED_EDGE('',*,*,#1478,.F.);
#1480=DIRECTION('',(-0.969912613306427,0.,-0.243453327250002));
#1481=VECTOR('',#1480,1.);
#1482=CARTESIAN_POINT('',(29.9486076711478,74.93,20.8245916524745));
#1483=LINE('',#1482,#1481);
#1484=CARTESIAN_POINT('',(29.9486076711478,74.93,20.8245916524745));
#1485=VERTEX_POINT('',#1484);
#1486=EDGE_CURVE('E1519',#1485,#1477,#1483,.T.);
#1487=ORIENTED_EDGE('',*,*,#1486,.F.);
#1488=DIRECTION('',(-0.274394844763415,0.,-0.961617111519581));
#1489=VECTOR('',#1488,1.);
#1490=CARTESIAN_POINT('',(30.8334304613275,74.93,23.9254543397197));
#1491=LINE('',#1490,#1489);
#1492=EDGE_CURVE('E1223',#649,#1485,#1491,.T.);
#1493=ORIENTED_EDGE('',*,*,#1492,.F.);
#1494=ORIENTED_EDGE('',*,*,#650,.F.);
#1495=ORIENTED_EDGE('',*,*,#1445,.T.);
#1496=ORIENTED_EDGE('',*,*,#533,.F.);
#1497=EDGE_LOOP('',(#1463,#1471,#1479,#1487,#1493,#1494,#1495,#1496));
#1498=FACE_BOUND('',#1497,.T.);
#1499=ADVANCED_FACE('F1230',(#1498),#1455,.T.);
#1500=CARTESIAN_POINT('',(14.8360543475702,68.58,28.3936164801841));
#1501=DIRECTION('',(0.,1.,0.));
#1502=DIRECTION('',(0.,0.,1.));
#1503=AXIS2_PLACEMENT_3D('',#1500,#1501,#1502);
#1504=PLANE('',#1503);
#1505=CARTESIAN_POINT('',(25.4590261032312,68.58,25.4590261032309));
#1506=DIRECTION('',(0.,1.,0.));
#1507=DIRECTION('',(0.,0.,1.));
#1508=AXIS2_PLACEMENT_3D('',#1505,#1506,#1507);
#1509=CIRCLE('',#1508,4.7625);
#1510=CARTESIAN_POINT('',(25.4590261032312,68.58,30.2215261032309));
#1511=VERTEX_POINT('',#1510);
#1512=EDGE_CURVE('E916',#1511,#1511,#1509,.T.);
#1513=ORIENTED_EDGE('',*,*,#1512,.F.);
#1514=EDGE_LOOP('',(#1513));
#1515=FACE_BOUND('',#1514,.T.);
#1516=ORIENTED_EDGE('',*,*,#1110,.F.);
#1517=DIRECTION('',(-0.274394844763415,0.,-0.961617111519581));
#1518=VECTOR('',#1517,1.);
#1519=CARTESIAN_POINT('',(29.9486076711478,68.58,20.8245916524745));
#1520=LINE('',#1519,#1518);
#1521=CARTESIAN_POINT('',(29.9486076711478,68.58,20.8245916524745));
#1522=VERTEX_POINT('',#1521);
#1523=EDGE_CURVE('E1497',#664,#1522,#1520,.T.);
#1524=ORIENTED_EDGE('',*,*,#1523,.T.);
#1525=DIRECTION('',(-0.969912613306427,0.,-0.243453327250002));
#1526=VECTOR('',#1525,1.);
#1527=CARTESIAN_POINT('',(29.9486076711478,68.58,20.8245916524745));
#1528=LINE('',#1527,#1526);
#1529=CARTESIAN_POINT('',(23.6902789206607,68.58,19.2537171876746));
#1530=VERTEX_POINT('',#1529);
#1531=EDGE_CURVE('E1502',#1522,#1530,#1528,.T.);
#1532=ORIENTED_EDGE('',*,*,#1531,.T.);
#1533=DIRECTION('',(-0.695793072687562,0.,0.718242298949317));
#1534=VECTOR('',#1533,1.);
#1535=CARTESIAN_POINT('',(23.6902789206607,68.58,19.2537171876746));
#1536=LINE('',#1535,#1534);
#1537=CARTESIAN_POINT('',(19.2006973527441,68.58,23.888151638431));
#1538=VERTEX_POINT('',#1537);
#1539=EDGE_CURVE('E1514',#1530,#1538,#1536,.T.);
#1540=ORIENTED_EDGE('',*,*,#1539,.T.);
#1541=DIRECTION('',(0.274119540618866,0.,0.96169562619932));
#1542=VECTOR('',#1541,1.);
#1543=CARTESIAN_POINT('',(19.2006973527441,68.58,23.888151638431));
#1544=LINE('',#1543,#1542);
#1545=CARTESIAN_POINT('',(20.9694445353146,68.58,30.0934605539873));
#1546=VERTEX_POINT('',#1545);
#1547=EDGE_CURVE('E1495',#1538,#1546,#1544,.T.);
#1548=ORIENTED_EDGE('',*,*,#1547,.T.);
#1549=DIRECTION('',(0.963674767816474,0.,0.267078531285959));
#1550=VECTOR('',#1549,1.);
#1551=CARTESIAN_POINT('',(33.591654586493,68.58,33.5916545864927));
#1552=LINE('',#1551,#1550);
#1553=EDGE_CURVE('E1488',#1546,#508,#1552,.T.);
#1554=ORIENTED_EDGE('',*,*,#1553,.T.);
#1555=EDGE_LOOP('',(#1516,#1524,#1532,#1540,#1548,#1554));
#1556=FACE_BOUND('',#1555,.T.);
#1557=ADVANCED_FACE('F1475',(#1515,#1556),#1504,.T.);
#1558=CARTESIAN_POINT('',(33.591654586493,68.58,33.5916545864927));
#1559=DIRECTION('',(-0.267078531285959,0.,0.963674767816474));
#1560=DIRECTION('',(0.963674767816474,0.,0.267078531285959));
#1561=AXIS2_PLACEMENT_3D('',#1558,#1559,#1560);
#1562=PLANE('',#1561);
#1563=ORIENTED_EDGE('',*,*,#524,.T.);
#1564=ORIENTED_EDGE('',*,*,#1553,.F.);
#1565=DIRECTION('',(0.,1.,0.));
#1566=VECTOR('',#1565,1.);
#1567=CARTESIAN_POINT('',(20.9694445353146,68.58,30.0934605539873));
#1568=LINE('',#1567,#1566);
#1569=EDGE_CURVE('E1443',#1546,#1461,#1568,.T.);
#1570=ORIENTED_EDGE('',*,*,#1569,.T.);
#1571=ORIENTED_EDGE('',*,*,#1462,.T.);
#1572=EDGE_LOOP('',(#1563,#1564,#1570,#1571));
#1573=FACE_BOUND('',#1572,.T.);
#1574=ADVANCED_FACE('F1471',(#1573),#1562,.F.);
#1575=CARTESIAN_POINT('',(19.2006973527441,68.58,23.888151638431));
#1576=DIRECTION('',(-0.96169562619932,0.,0.274119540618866));
#1577=DIRECTION('',(0.274119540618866,0.,0.96169562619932));
#1578=AXIS2_PLACEMENT_3D('',#1575,#1576,#1577);
#1579=PLANE('',#1578);
#1580=ORIENTED_EDGE('',*,*,#1470,.T.);
#1581=ORIENTED_EDGE('',*,*,#1569,.F.);
#1582=ORIENTED_EDGE('',*,*,#1547,.F.);
#1583=DIRECTION('',(0.,1.,0.));
#1584=VECTOR('',#1583,1.);
#1585=CARTESIAN_POINT('',(19.2006973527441,68.58,23.888151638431));
#1586=LINE('',#1585,#1584);
#1587=EDGE_CURVE('E1451',#1538,#1469,#1586,.T.);
#1588=ORIENTED_EDGE('',*,*,#1587,.T.);
#1589=EDGE_LOOP('',(#1580,#1581,#1582,#1588));
#1590=FACE_BOUND('',#1589,.T.);
#1591=ADVANCED_FACE('F1474',(#1590),#1579,.F.);
#1592=CARTESIAN_POINT('',(23.6902789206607,68.58,19.2537171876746));
#1593=DIRECTION('',(-0.718242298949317,0.,-0.695793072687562));
#1594=DIRECTION('',(-0.695793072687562,0.,0.718242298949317));
#1595=AXIS2_PLACEMENT_3D('',#1592,#1593,#1594);
#1596=PLANE('',#1595);
#1597=ORIENTED_EDGE('',*,*,#1478,.T.);
#1598=ORIENTED_EDGE('',*,*,#1587,.F.);
#1599=ORIENTED_EDGE('',*,*,#1539,.F.);
#1600=DIRECTION('',(0.,1.,0.));
#1601=VECTOR('',#1600,1.);
#1602=CARTESIAN_POINT('',(23.6902789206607,68.58,19.2537171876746));
#1603=LINE('',#1602,#1601);
#1604=EDGE_CURVE('E1526',#1530,#1477,#1603,.T.);
#1605=ORIENTED_EDGE('',*,*,#1604,.T.);
#1606=EDGE_LOOP('',(#1597,#1598,#1599,#1605));
#1607=FACE_BOUND('',#1606,.T.);
#1608=ADVANCED_FACE('F1481',(#1607),#1596,.F.);
#1609=CARTESIAN_POINT('',(29.9486076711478,68.58,20.8245916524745));
#1610=DIRECTION('',(0.243453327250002,0.,-0.969912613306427));
#1611=DIRECTION('',(-0.969912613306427,0.,-0.243453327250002));
#1612=AXIS2_PLACEMENT_3D('',#1609,#1610,#1611);
#1613=PLANE('',#1612);
#1614=ORIENTED_EDGE('',*,*,#1486,.T.);
#1615=ORIENTED_EDGE('',*,*,#1604,.F.);
#1616=ORIENTED_EDGE('',*,*,#1531,.F.);
#1617=DIRECTION('',(0.,1.,0.));
#1618=VECTOR('',#1617,1.);
#1619=CARTESIAN_POINT('',(29.9486076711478,68.58,20.8245916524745));
#1620=LINE('',#1619,#1618);
#1621=EDGE_CURVE('E1458',#1522,#1485,#1620,.T.);
#1622=ORIENTED_EDGE('',*,*,#1621,.T.);
#1623=EDGE_LOOP('',(#1614,#1615,#1616,#1622));
#1624=FACE_BOUND('',#1623,.T.);
#1625=ADVANCED_FACE('F1469',(#1624),#1613,.F.);
#1626=CARTESIAN_POINT('',(29.9486076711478,68.58,20.8245916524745));
#1627=DIRECTION('',(0.961617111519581,0.,-0.274394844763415));
#1628=DIRECTION('',(-0.274394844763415,0.,-0.961617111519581));
#1629=AXIS2_PLACEMENT_3D('',#1626,#1627,#1628);
#1630=PLANE('',#1629);
#1631=ORIENTED_EDGE('',*,*,#665,.T.);
#1632=ORIENTED_EDGE('',*,*,#1492,.T.);
#1633=ORIENTED_EDGE('',*,*,#1621,.F.);
#1634=ORIENTED_EDGE('',*,*,#1523,.F.);
#1635=EDGE_LOOP('',(#1631,#1632,#1633,#1634));
#1636=FACE_BOUND('',#1635,.T.);
#1637=ADVANCED_FACE('F1464',(#1636),#1630,.F.);
#1638=CARTESIAN_POINT('',(-25.459026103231,97.79,25.4590261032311));
#1639=DIRECTION('',(0.,-1.,0.));
#1640=DIRECTION('',(0.,0.,-1.));
#1641=AXIS2_PLACEMENT_3D('',#1638,#1639,#1640);
#1642=CYLINDRICAL_SURFACE('',#1641,7.9375);
#1643=CARTESIAN_POINT('',(-25.459026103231,74.93,25.4590261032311));
#1644=DIRECTION('',(0.,1.,0.));
#1645=DIRECTION('',(-1.,0.,0.));
#1646=AXIS2_PLACEMENT_3D('',#1643,#1644,#1645);
#1647=CIRCLE('',#1646,7.9375);
#1648=EDGE_CURVE('E1508',#485,#372,#1647,.T.);
#1649=ORIENTED_EDGE('',*,*,#1648,.F.);
#1650=ORIENTED_EDGE('',*,*,#486,.F.);
#1651=EDGE_LOOP('',(#1649,#1650));
#1652=FACE_BOUND('',#1651,.T.);
#1653=ADVANCED_FACE('F1468',(#1652),#1642,.F.);
#1654=CARTESIAN_POINT('',(-25.459026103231,74.93,25.4590261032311));
#1655=DIRECTION('',(0.,1.,0.));
#1656=DIRECTION('',(-1.,0.,0.));
#1657=AXIS2_PLACEMENT_3D('',#1654,#1655,#1656);
#1658=PLANE('',#1657);
#1659=DIRECTION('',(-0.267078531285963,0.,0.963674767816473));
#1660=VECTOR('',#1659,1.);
#1661=CARTESIAN_POINT('',(-33.5916545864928,74.93,33.5916545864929));
#1662=LINE('',#1661,#1660);
#1663=CARTESIAN_POINT('',(-30.0934605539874,74.93,20.9694445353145));
#1664=VERTEX_POINT('',#1663);
#1665=EDGE_CURVE('E812',#1664,#363,#1662,.T.);
#1666=ORIENTED_EDGE('',*,*,#1665,.F.);
#1667=DIRECTION('',(-0.961695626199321,0.,0.274119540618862));
#1668=VECTOR('',#1667,1.);
#1669=CARTESIAN_POINT('',(-23.8881516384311,74.93,19.200697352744));
#1670=LINE('',#1669,#1668);
#1671=CARTESIAN_POINT('',(-23.8881516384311,74.93,19.200697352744));
#1672=VERTEX_POINT('',#1671);
#1673=EDGE_CURVE('E818',#1672,#1664,#1670,.T.);
#1674=ORIENTED_EDGE('',*,*,#1673,.F.);
#1675=DIRECTION('',(-0.718242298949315,0.,-0.695793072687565));
#1676=VECTOR('',#1675,1.);
#1677=CARTESIAN_POINT('',(-19.2537171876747,74.93,23.6902789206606));
#1678=LINE('',#1677,#1676);
#1679=CARTESIAN_POINT('',(-19.2537171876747,74.93,23.6902789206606));
#1680=VERTEX_POINT('',#1679);
#1681=EDGE_CURVE('E840',#1680,#1672,#1678,.T.);
#1682=ORIENTED_EDGE('',*,*,#1681,.F.);
#1683=DIRECTION('',(0.243453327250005,0.,-0.969912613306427));
#1684=VECTOR('',#1683,1.);
#1685=CARTESIAN_POINT('',(-20.8245916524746,74.93,29.9486076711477));
#1686=LINE('',#1685,#1684);
#1687=CARTESIAN_POINT('',(-20.8245916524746,74.93,29.9486076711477));
#1688=VERTEX_POINT('',#1687);
#1689=EDGE_CURVE('E836',#1688,#1680,#1686,.T.);
#1690=ORIENTED_EDGE('',*,*,#1689,.F.);
#1691=DIRECTION('',(0.961617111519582,0.,-0.274394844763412));
#1692=VECTOR('',#1691,1.);
#1693=CARTESIAN_POINT('',(-23.9254543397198,74.93,30.8334304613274));
#1694=LINE('',#1693,#1692);
#1695=EDGE_CURVE('E905',#489,#1688,#1694,.T.);
#1696=ORIENTED_EDGE('',*,*,#1695,.F.);
#1697=ORIENTED_EDGE('',*,*,#490,.F.);
#1698=ORIENTED_EDGE('',*,*,#1648,.T.);
#1699=ORIENTED_EDGE('',*,*,#373,.F.);
#1700=EDGE_LOOP('',(#1666,#1674,#1682,#1690,#1696,#1697,#1698,#1699));
#1701=FACE_BOUND('',#1700,.T.);
#1702=ADVANCED_FACE('F1343',(#1701),#1658,.T.);
#1703=CARTESIAN_POINT('',(-25.459026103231,97.79,-25.4590261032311));
#1704=DIRECTION('',(0.,-1.,0.));
#1705=DIRECTION('',(0.,0.,-1.));
#1706=AXIS2_PLACEMENT_3D('',#1703,#1704,#1705);
#1707=CYLINDRICAL_SURFACE('',#1706,7.9375);
#1708=CARTESIAN_POINT('',(-25.459026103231,74.93,-25.4590261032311));
#1709=DIRECTION('',(0.,1.,0.));
#1710=DIRECTION('',(0.,0.,-1.));
#1711=AXIS2_PLACEMENT_3D('',#1708,#1709,#1710);
#1712=CIRCLE('',#1711,7.9375);
#1713=EDGE_CURVE('E1668',#325,#212,#1712,.T.);
#1714=ORIENTED_EDGE('',*,*,#1713,.F.);
#1715=ORIENTED_EDGE('',*,*,#326,.F.);
#1716=EDGE_LOOP('',(#1714,#1715));
#1717=FACE_BOUND('',#1716,.T.);
#1718=ADVANCED_FACE('F1706',(#1717),#1707,.F.);
#1719=CARTESIAN_POINT('',(-25.459026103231,74.93,-25.4590261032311));
#1720=DIRECTION('',(0.,1.,0.));
#1721=DIRECTION('',(0.,0.,-1.));
#1722=AXIS2_PLACEMENT_3D('',#1719,#1720,#1721);
#1723=PLANE('',#1722);
#1724=DIRECTION('',(-0.963674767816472,0.,-0.267078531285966));
#1725=VECTOR('',#1724,1.);
#1726=CARTESIAN_POINT('',(-33.5916545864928,74.93,-33.5916545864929));
#1727=LINE('',#1726,#1725);
#1728=CARTESIAN_POINT('',(-20.9694445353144,74.93,-30.0934605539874));
#1729=VERTEX_POINT('',#1728);
#1730=EDGE_CURVE('E1377',#1729,#203,#1727,.T.);
#1731=ORIENTED_EDGE('',*,*,#1730,.F.);
#1732=DIRECTION('',(-0.274119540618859,0.,-0.961695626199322));
#1733=VECTOR('',#1732,1.);
#1734=CARTESIAN_POINT('',(-19.2006973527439,74.93,-23.8881516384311));
#1735=LINE('',#1734,#1733);
#1736=CARTESIAN_POINT('',(-19.2006973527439,74.93,-23.8881516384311));
#1737=VERTEX_POINT('',#1736);
#1738=EDGE_CURVE('E1381',#1737,#1729,#1735,.T.);
#1739=ORIENTED_EDGE('',*,*,#1738,.F.);
#1740=DIRECTION('',(0.695793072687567,0.,-0.718242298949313));
#1741=VECTOR('',#1740,1.);
#1742=CARTESIAN_POINT('',(-23.6902789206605,74.93,-19.2537171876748));
#1743=LINE('',#1742,#1741);
#1744=CARTESIAN_POINT('',(-23.6902789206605,74.93,-19.2537171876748));
#1745=VERTEX_POINT('',#1744);
#1746=EDGE_CURVE('E1375',#1745,#1737,#1743,.T.);
#1747=ORIENTED_EDGE('',*,*,#1746,.F.);
#1748=DIRECTION('',(0.969912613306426,0.,0.243453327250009));
#1749=VECTOR('',#1748,1.);
#1750=CARTESIAN_POINT('',(-29.9486076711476,74.93,-20.8245916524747));
#1751=LINE('',#1750,#1749);
#1752=CARTESIAN_POINT('',(-29.9486076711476,74.93,-20.8245916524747));
#1753=VERTEX_POINT('',#1752);
#1754=EDGE_CURVE('E1372',#1753,#1745,#1751,.T.);
#1755=ORIENTED_EDGE('',*,*,#1754,.F.);
#1756=DIRECTION('',(0.274394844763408,0.,0.961617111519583));
#1757=VECTOR('',#1756,1.);
#1758=CARTESIAN_POINT('',(-30.8334304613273,74.93,-23.9254543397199));
#1759=LINE('',#1758,#1757);
#1760=EDGE_CURVE('E910',#329,#1753,#1759,.T.);
#1761=ORIENTED_EDGE('',*,*,#1760,.F.);
#1762=ORIENTED_EDGE('',*,*,#330,.F.);
#1763=ORIENTED_EDGE('',*,*,#1713,.T.);
#1764=ORIENTED_EDGE('',*,*,#213,.F.);
#1765=EDGE_LOOP('',(#1731,#1739,#1747,#1755,#1761,#1762,#1763,#1764));
#1766=FACE_BOUND('',#1765,.T.);
#1767=ADVANCED_FACE('F893',(#1766),#1723,.T.);
#1768=CARTESIAN_POINT('',(25.4590261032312,97.79,-25.4590261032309));
#1769=DIRECTION('',(0.,-1.,0.));
#1770=DIRECTION('',(0.,0.,-1.));
#1771=AXIS2_PLACEMENT_3D('',#1768,#1769,#1770);
#1772=CYLINDRICAL_SURFACE('',#1771,7.9375);
#1773=CARTESIAN_POINT('',(25.4590261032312,74.93,-25.4590261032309));
#1774=DIRECTION('',(0.,1.,0.));
#1775=DIRECTION('',(1.,0.,0.));
#1776=AXIS2_PLACEMENT_3D('',#1773,#1774,#1775);
#1777=CIRCLE('',#1776,7.9375);
#1778=EDGE_CURVE('E1665',#160,#47,#1777,.T.);
#1779=ORIENTED_EDGE('',*,*,#1778,.F.);
#1780=ORIENTED_EDGE('',*,*,#161,.F.);
#1781=EDGE_LOOP('',(#1779,#1780));
#1782=FACE_BOUND('',#1781,.T.);
#1783=ADVANCED_FACE('F888',(#1782),#1772,.F.);
#1784=CARTESIAN_POINT('',(25.4590261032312,74.93,-25.4590261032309));
#1785=DIRECTION('',(0.,1.,0.));
#1786=DIRECTION('',(1.,0.,0.));
#1787=AXIS2_PLACEMENT_3D('',#1784,#1785,#1786);
#1788=PLANE('',#1787);
#1789=DIRECTION('',(0.26707853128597,0.,-0.963674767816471));
#1790=VECTOR('',#1789,1.);
#1791=CARTESIAN_POINT('',(33.591654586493,74.93,-33.5916545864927));
#1792=LINE('',#1791,#1790);
#1793=CARTESIAN_POINT('',(30.0934605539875,74.93,-20.9694445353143));
#1794=VERTEX_POINT('',#1793);
#1795=EDGE_CURVE('E676',#1794,#36,#1792,.T.);
#1796=ORIENTED_EDGE('',*,*,#1795,.F.);
#1797=DIRECTION('',(0.961695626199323,0.,-0.274119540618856));
#1798=VECTOR('',#1797,1.);
#1799=CARTESIAN_POINT('',(23.8881516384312,74.93,-19.2006973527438));
#1800=LINE('',#1799,#1798);
#1801=CARTESIAN_POINT('',(23.8881516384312,74.93,-19.2006973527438));
#1802=VERTEX_POINT('',#1801);
#1803=EDGE_CURVE('E697',#1802,#1794,#1800,.T.);
#1804=ORIENTED_EDGE('',*,*,#1803,.F.);
#1805=DIRECTION('',(0.71824229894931,0.,0.69579307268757));
#1806=VECTOR('',#1805,1.);
#1807=CARTESIAN_POINT('',(19.2537171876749,74.93,-23.6902789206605));
#1808=LINE('',#1807,#1806);
#1809=CARTESIAN_POINT('',(19.2537171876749,74.93,-23.6902789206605));
#1810=VERTEX_POINT('',#1809);
#1811=EDGE_CURVE('E719',#1810,#1802,#1808,.T.);
#1812=ORIENTED_EDGE('',*,*,#1811,.F.);
#1813=DIRECTION('',(-0.243453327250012,0.,0.969912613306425));
#1814=VECTOR('',#1813,1.);
#1815=CARTESIAN_POINT('',(20.8245916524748,74.93,-29.9486076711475));
#1816=LINE('',#1815,#1814);
#1817=CARTESIAN_POINT('',(20.8245916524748,74.93,-29.9486076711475));
#1818=VERTEX_POINT('',#1817);
#1819=EDGE_CURVE('E715',#1818,#1810,#1816,.T.);
#1820=ORIENTED_EDGE('',*,*,#1819,.F.);
#1821=DIRECTION('',(-0.961617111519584,0.,0.274394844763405));
#1822=VECTOR('',#1821,1.);
#1823=CARTESIAN_POINT('',(23.92545433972,74.93,-30.8334304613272));
#1824=LINE('',#1823,#1822);
#1825=EDGE_CURVE('E913',#164,#1818,#1824,.T.);
#1826=ORIENTED_EDGE('',*,*,#1825,.F.);
#1827=ORIENTED_EDGE('',*,*,#165,.F.);
#1828=ORIENTED_EDGE('',*,*,#1778,.T.);
#1829=ORIENTED_EDGE('',*,*,#48,.F.);
#1830=EDGE_LOOP('',(#1796,#1804,#1812,#1820,#1826,#1827,#1828,#1829));
#1831=FACE_BOUND('',#1830,.T.);
#1832=ADVANCED_FACE('F885',(#1831),#1788,.T.);
#1833=CARTESIAN_POINT('',(-28.3936164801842,68.58,14.8360543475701));
#1834=DIRECTION('',(0.,1.,0.));
#1835=DIRECTION('',(-1.,0.,0.));
#1836=AXIS2_PLACEMENT_3D('',#1833,#1834,#1835);
#1837=PLANE('',#1836);
#1838=CARTESIAN_POINT('',(-25.459026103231,68.58,25.4590261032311));
#1839=DIRECTION('',(0.,1.,0.));
#1840=DIRECTION('',(0.,0.,1.));
#1841=AXIS2_PLACEMENT_3D('',#1838,#1839,#1840);
#1842=CIRCLE('',#1841,4.7625);
#1843=CARTESIAN_POINT('',(-25.459026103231,68.58,30.2215261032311));
#1844=VERTEX_POINT('',#1843);
#1845=EDGE_CURVE('E920',#1844,#1844,#1842,.T.);
#1846=ORIENTED_EDGE('',*,*,#1845,.F.);
#1847=EDGE_LOOP('',(#1846));
#1848=FACE_BOUND('',#1847,.T.);
#1849=ORIENTED_EDGE('',*,*,#1113,.F.);
#1850=DIRECTION('',(0.961617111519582,0.,-0.274394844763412));
#1851=VECTOR('',#1850,1.);
#1852=CARTESIAN_POINT('',(-20.8245916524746,68.58,29.9486076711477));
#1853=LINE('',#1852,#1851);
#1854=CARTESIAN_POINT('',(-20.8245916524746,68.58,29.9486076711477));
#1855=VERTEX_POINT('',#1854);
#1856=EDGE_CURVE('E817',#504,#1855,#1853,.T.);
#1857=ORIENTED_EDGE('',*,*,#1856,.T.);
#1858=DIRECTION('',(0.243453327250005,0.,-0.969912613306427));
#1859=VECTOR('',#1858,1.);
#1860=CARTESIAN_POINT('',(-20.8245916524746,68.58,29.9486076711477));
#1861=LINE('',#1860,#1859);
#1862=CARTESIAN_POINT('',(-19.2537171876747,68.58,23.6902789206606));
#1863=VERTEX_POINT('',#1862);
#1864=EDGE_CURVE('E821',#1855,#1863,#1861,.T.);
#1865=ORIENTED_EDGE('',*,*,#1864,.T.);
#1866=DIRECTION('',(-0.718242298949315,0.,-0.695793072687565));
#1867=VECTOR('',#1866,1.);
#1868=CARTESIAN_POINT('',(-19.2537171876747,68.58,23.6902789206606));
#1869=LINE('',#1868,#1867);
#1870=CARTESIAN_POINT('',(-23.8881516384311,68.58,19.200697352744));
#1871=VERTEX_POINT('',#1870);
#1872=EDGE_CURVE('E825',#1863,#1871,#1869,.T.);
#1873=ORIENTED_EDGE('',*,*,#1872,.T.);
#1874=DIRECTION('',(-0.961695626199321,0.,0.274119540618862));
#1875=VECTOR('',#1874,1.);
#1876=CARTESIAN_POINT('',(-23.8881516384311,68.58,19.200697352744));
#1877=LINE('',#1876,#1875);
#1878=CARTESIAN_POINT('',(-30.0934605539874,68.58,20.9694445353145));
#1879=VERTEX_POINT('',#1878);
#1880=EDGE_CURVE('E829',#1871,#1879,#1877,.T.);
#1881=ORIENTED_EDGE('',*,*,#1880,.T.);
#1882=DIRECTION('',(-0.267078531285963,0.,0.963674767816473));
#1883=VECTOR('',#1882,1.);
#1884=CARTESIAN_POINT('',(-33.5916545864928,68.58,33.5916545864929));
#1885=LINE('',#1884,#1883);
#1886=EDGE_CURVE('E813',#1879,#348,#1885,.T.);
#1887=ORIENTED_EDGE('',*,*,#1886,.T.);
#1888=EDGE_LOOP('',(#1849,#1857,#1865,#1873,#1881,#1887));
#1889=FACE_BOUND('',#1888,.T.);
#1890=ADVANCED_FACE('F883',(#1848,#1889),#1837,.T.);
#1891=CARTESIAN_POINT('',(-33.5916545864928,68.58,33.5916545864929));
#1892=DIRECTION('',(-0.963674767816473,0.,-0.267078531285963));
#1893=DIRECTION('',(-0.267078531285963,0.,0.963674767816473));
#1894=AXIS2_PLACEMENT_3D('',#1891,#1892,#1893);
#1895=PLANE('',#1894);
#1896=ORIENTED_EDGE('',*,*,#364,.T.);
#1897=ORIENTED_EDGE('',*,*,#1886,.F.);
#1898=DIRECTION('',(0.,1.,0.));
#1899=VECTOR('',#1898,1.);
#1900=CARTESIAN_POINT('',(-30.0934605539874,68.58,20.9694445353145));
#1901=LINE('',#1900,#1899);
#1902=EDGE_CURVE('E847',#1879,#1664,#1901,.T.);
#1903=ORIENTED_EDGE('',*,*,#1902,.T.);
#1904=ORIENTED_EDGE('',*,*,#1665,.T.);
#1905=EDGE_LOOP('',(#1896,#1897,#1903,#1904));
#1906=FACE_BOUND('',#1905,.T.);
#1907=ADVANCED_FACE('F878',(#1906),#1895,.F.);
#1908=CARTESIAN_POINT('',(-23.8881516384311,68.58,19.200697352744));
#1909=DIRECTION('',(-0.274119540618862,0.,-0.961695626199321));
#1910=DIRECTION('',(-0.961695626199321,0.,0.274119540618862));
#1911=AXIS2_PLACEMENT_3D('',#1908,#1909,#1910);
#1912=PLANE('',#1911);
#1913=ORIENTED_EDGE('',*,*,#1673,.T.);
#1914=ORIENTED_EDGE('',*,*,#1902,.F.);
#1915=ORIENTED_EDGE('',*,*,#1880,.F.);
#1916=DIRECTION('',(0.,1.,0.));
#1917=VECTOR('',#1916,1.);
#1918=CARTESIAN_POINT('',(-23.8881516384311,68.58,19.200697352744));
#1919=LINE('',#1918,#1917);
#1920=EDGE_CURVE('E851',#1871,#1672,#1919,.T.);
#1921=ORIENTED_EDGE('',*,*,#1920,.T.);
#1922=EDGE_LOOP('',(#1913,#1914,#1915,#1921));
#1923=FACE_BOUND('',#1922,.T.);
#1924=ADVANCED_FACE('F882',(#1923),#1912,.F.);
#1925=CARTESIAN_POINT('',(-19.2537171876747,68.58,23.6902789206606));
#1926=DIRECTION('',(0.695793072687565,0.,-0.718242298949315));
#1927=DIRECTION('',(-0.718242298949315,0.,-0.695793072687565));
#1928=AXIS2_PLACEMENT_3D('',#1925,#1926,#1927);
#1929=PLANE('',#1928);
#1930=ORIENTED_EDGE('',*,*,#1681,.T.);
#1931=ORIENTED_EDGE('',*,*,#1920,.F.);
#1932=ORIENTED_EDGE('',*,*,#1872,.F.);
#1933=DIRECTION('',(0.,1.,0.));
#1934=VECTOR('',#1933,1.);
#1935=CARTESIAN_POINT('',(-19.2537171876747,68.58,23.6902789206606));
#1936=LINE('',#1935,#1934);
#1937=EDGE_CURVE('E854',#1863,#1680,#1936,.T.);
#1938=ORIENTED_EDGE('',*,*,#1937,.T.);
#1939=EDGE_LOOP('',(#1930,#1931,#1932,#1938));
#1940=FACE_BOUND('',#1939,.T.);
#1941=ADVANCED_FACE('F1657',(#1940),#1929,.F.);
#1942=CARTESIAN_POINT('',(-20.8245916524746,68.58,29.9486076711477));
#1943=DIRECTION('',(0.969912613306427,0.,0.243453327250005));
#1944=DIRECTION('',(0.243453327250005,0.,-0.969912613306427));
#1945=AXIS2_PLACEMENT_3D('',#1942,#1943,#1944);
#1946=PLANE('',#1945);
#1947=ORIENTED_EDGE('',*,*,#1689,.T.);
#1948=ORIENTED_EDGE('',*,*,#1937,.F.);
#1949=ORIENTED_EDGE('',*,*,#1864,.F.);
#1950=DIRECTION('',(0.,1.,0.));
#1951=VECTOR('',#1950,1.);
#1952=CARTESIAN_POINT('',(-20.8245916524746,68.58,29.9486076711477));
#1953=LINE('',#1952,#1951);
#1954=EDGE_CURVE('E833',#1855,#1688,#1953,.T.);
#1955=ORIENTED_EDGE('',*,*,#1954,.T.);
#1956=EDGE_LOOP('',(#1947,#1948,#1949,#1955));
#1957=FACE_BOUND('',#1956,.T.);
#1958=ADVANCED_FACE('F875',(#1957),#1946,.F.);
#1959=CARTESIAN_POINT('',(-20.8245916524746,68.58,29.9486076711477));
#1960=DIRECTION('',(0.274394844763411,0.,0.961617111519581));
#1961=DIRECTION('',(0.961617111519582,0.,-0.274394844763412));
#1962=AXIS2_PLACEMENT_3D('',#1959,#1960,#1961);
#1963=PLANE('',#1962);
#1964=ORIENTED_EDGE('',*,*,#505,.T.);
#1965=ORIENTED_EDGE('',*,*,#1695,.T.);
#1966=ORIENTED_EDGE('',*,*,#1954,.F.);
#1967=ORIENTED_EDGE('',*,*,#1856,.F.);
#1968=EDGE_LOOP('',(#1964,#1965,#1966,#1967));
#1969=FACE_BOUND('',#1968,.T.);
#1970=ADVANCED_FACE('F774',(#1969),#1963,.F.);
#1971=CARTESIAN_POINT('',(-14.83605434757,68.58,-28.3936164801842));
#1972=DIRECTION('',(0.,1.,0.));
#1973=DIRECTION('',(0.,0.,-1.));
#1974=AXIS2_PLACEMENT_3D('',#1971,#1972,#1973);
#1975=PLANE('',#1974);
#1976=CARTESIAN_POINT('',(-25.459026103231,68.58,-25.4590261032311));
#1977=DIRECTION('',(0.,1.,0.));
#1978=DIRECTION('',(0.,0.,1.));
#1979=AXIS2_PLACEMENT_3D('',#1976,#1977,#1978);
#1980=CIRCLE('',#1979,4.7625);
#1981=CARTESIAN_POINT('',(-25.459026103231,68.58,-20.6965261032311));
#1982=VERTEX_POINT('',#1981);
#1983=EDGE_CURVE('E924',#1982,#1982,#1980,.T.);
#1984=ORIENTED_EDGE('',*,*,#1983,.F.);
#1985=EDGE_LOOP('',(#1984));
#1986=FACE_BOUND('',#1985,.T.);
#1987=ORIENTED_EDGE('',*,*,#1116,.F.);
#1988=DIRECTION('',(0.274394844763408,0.,0.961617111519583));
#1989=VECTOR('',#1988,1.);
#1990=CARTESIAN_POINT('',(-29.9486076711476,68.58,-20.8245916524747));
#1991=LINE('',#1990,#1989);
#1992=CARTESIAN_POINT('',(-29.9486076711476,68.58,-20.8245916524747));
#1993=VERTEX_POINT('',#1992);
#1994=EDGE_CURVE('E1364',#344,#1993,#1991,.T.);
#1995=ORIENTED_EDGE('',*,*,#1994,.T.);
#1996=DIRECTION('',(0.969912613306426,0.,0.243453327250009));
#1997=VECTOR('',#1996,1.);
#1998=CARTESIAN_POINT('',(-29.9486076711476,68.58,-20.8245916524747));
#1999=LINE('',#1998,#1997);
#2000=CARTESIAN_POINT('',(-23.6902789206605,68.58,-19.2537171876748));
#2001=VERTEX_POINT('',#2000);
#2002=EDGE_CURVE('E1410',#1993,#2001,#1999,.T.);
#2003=ORIENTED_EDGE('',*,*,#2002,.T.);
#2004=DIRECTION('',(0.695793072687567,0.,-0.718242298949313));
#2005=VECTOR('',#2004,1.);
#2006=CARTESIAN_POINT('',(-23.6902789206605,68.58,-19.2537171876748));
#2007=LINE('',#2006,#2005);
#2008=CARTESIAN_POINT('',(-19.2006973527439,68.58,-23.8881516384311));
#2009=VERTEX_POINT('',#2008);
#2010=EDGE_CURVE('E1404',#2001,#2009,#2007,.T.);
#2011=ORIENTED_EDGE('',*,*,#2010,.T.);
#2012=DIRECTION('',(-0.274119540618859,0.,-0.961695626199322));
#2013=VECTOR('',#2012,1.);
#2014=CARTESIAN_POINT('',(-19.2006973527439,68.58,-23.8881516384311));
#2015=LINE('',#2014,#2013);
#2016=CARTESIAN_POINT('',(-20.9694445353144,68.58,-30.0934605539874));
#2017=VERTEX_POINT('',#2016);
#2018=EDGE_CURVE('E1399',#2009,#2017,#2015,.T.);
#2019=ORIENTED_EDGE('',*,*,#2018,.T.);
#2020=DIRECTION('',(-0.963674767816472,0.,-0.267078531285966));
#2021=VECTOR('',#2020,1.);
#2022=CARTESIAN_POINT('',(-33.5916545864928,68.58,-33.5916545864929));
#2023=LINE('',#2022,#2021);
#2024=EDGE_CURVE('E1390',#2017,#188,#2023,.T.);
#2025=ORIENTED_EDGE('',*,*,#2024,.T.);
#2026=EDGE_LOOP('',(#1987,#1995,#2003,#2011,#2019,#2025));
#2027=FACE_BOUND('',#2026,.T.);
#2028=ADVANCED_FACE('F770',(#1986,#2027),#1975,.T.);
#2029=CARTESIAN_POINT('',(-33.5916545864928,68.58,-33.5916545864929));
#2030=DIRECTION('',(0.267078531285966,0.,-0.963674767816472));
#2031=DIRECTION('',(-0.963674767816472,0.,-0.267078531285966));
#2032=AXIS2_PLACEMENT_3D('',#2029,#2030,#2031);
#2033=PLANE('',#2032);
#2034=ORIENTED_EDGE('',*,*,#204,.T.);
#2035=ORIENTED_EDGE('',*,*,#2024,.F.);
#2036=DIRECTION('',(0.,1.,0.));
#2037=VECTOR('',#2036,1.);
#2038=CARTESIAN_POINT('',(-20.9694445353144,68.58,-30.0934605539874));
#2039=LINE('',#2038,#2037);
#2040=EDGE_CURVE('E804',#2017,#1729,#2039,.T.);
#2041=ORIENTED_EDGE('',*,*,#2040,.T.);
#2042=ORIENTED_EDGE('',*,*,#1730,.T.);
#2043=EDGE_LOOP('',(#2034,#2035,#2041,#2042));
#2044=FACE_BOUND('',#2043,.T.);
#2045=ADVANCED_FACE('F773',(#2044),#2033,.F.);
#2046=CARTESIAN_POINT('',(-19.2006973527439,68.58,-23.8881516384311));
#2047=DIRECTION('',(0.961695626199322,0.,-0.274119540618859));
#2048=DIRECTION('',(-0.274119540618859,0.,-0.961695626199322));
#2049=AXIS2_PLACEMENT_3D('',#2046,#2047,#2048);
#2050=PLANE('',#2049);
#2051=ORIENTED_EDGE('',*,*,#1738,.T.);
#2052=ORIENTED_EDGE('',*,*,#2040,.F.);
#2053=ORIENTED_EDGE('',*,*,#2018,.F.);
#2054=DIRECTION('',(0.,1.,0.));
#2055=VECTOR('',#2054,1.);
#2056=CARTESIAN_POINT('',(-19.2006973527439,68.58,-23.8881516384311));
#2057=LINE('',#2056,#2055);
#2058=EDGE_CURVE('E1393',#2009,#1737,#2057,.T.);
#2059=ORIENTED_EDGE('',*,*,#2058,.T.);
#2060=EDGE_LOOP('',(#2051,#2052,#2053,#2059));
#2061=FACE_BOUND('',#2060,.T.);
#2062=ADVANCED_FACE('F776',(#2061),#2050,.F.);
#2063=CARTESIAN_POINT('',(-23.6902789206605,68.58,-19.2537171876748));
#2064=DIRECTION('',(0.718242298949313,0.,0.695793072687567));
#2065=DIRECTION('',(0.695793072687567,0.,-0.718242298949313));
#2066=AXIS2_PLACEMENT_3D('',#2063,#2064,#2065);
#2067=PLANE('',#2066);
#2068=ORIENTED_EDGE('',*,*,#1746,.T.);
#2069=ORIENTED_EDGE('',*,*,#2058,.F.);
#2070=ORIENTED_EDGE('',*,*,#2010,.F.);
#2071=DIRECTION('',(0.,1.,0.));
#2072=VECTOR('',#2071,1.);
#2073=CARTESIAN_POINT('',(-23.6902789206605,68.58,-19.2537171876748));
#2074=LINE('',#2073,#2072);
#2075=EDGE_CURVE('E1395',#2001,#1745,#2074,.T.);
#2076=ORIENTED_EDGE('',*,*,#2075,.T.);
#2077=EDGE_LOOP('',(#2068,#2069,#2070,#2076));
#2078=FACE_BOUND('',#2077,.T.);
#2079=ADVANCED_FACE('F779',(#2078),#2067,.F.);
#2080=CARTESIAN_POINT('',(-29.9486076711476,68.58,-20.8245916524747));
#2081=DIRECTION('',(-0.243453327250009,0.,0.969912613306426));
#2082=DIRECTION('',(0.969912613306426,0.,0.243453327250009));
#2083=AXIS2_PLACEMENT_3D('',#2080,#2081,#2082);
#2084=PLANE('',#2083);
#2085=ORIENTED_EDGE('',*,*,#1754,.T.);
#2086=ORIENTED_EDGE('',*,*,#2075,.F.);
#2087=ORIENTED_EDGE('',*,*,#2002,.F.);
#2088=DIRECTION('',(0.,1.,0.));
#2089=VECTOR('',#2088,1.);
#2090=CARTESIAN_POINT('',(-29.9486076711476,68.58,-20.8245916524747));
#2091=LINE('',#2090,#2089);
#2092=EDGE_CURVE('E805',#1993,#1753,#2091,.T.);
#2093=ORIENTED_EDGE('',*,*,#2092,.T.);
#2094=EDGE_LOOP('',(#2085,#2086,#2087,#2093));
#2095=FACE_BOUND('',#2094,.T.);
#2096=ADVANCED_FACE('F783',(#2095),#2084,.F.);
#2097=CARTESIAN_POINT('',(-29.9486076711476,68.58,-20.8245916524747));
#2098=DIRECTION('',(-0.961617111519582,0.,0.274394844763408));
#2099=DIRECTION('',(0.274394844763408,0.,0.961617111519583));
#2100=AXIS2_PLACEMENT_3D('',#2097,#2098,#2099);
#2101=PLANE('',#2100);
#2102=ORIENTED_EDGE('',*,*,#345,.T.);
#2103=ORIENTED_EDGE('',*,*,#1760,.T.);
#2104=ORIENTED_EDGE('',*,*,#2092,.F.);
#2105=ORIENTED_EDGE('',*,*,#1994,.F.);
#2106=EDGE_LOOP('',(#2102,#2103,#2104,#2105));
#2107=FACE_BOUND('',#2106,.T.);
#2108=ADVANCED_FACE('F787',(#2107),#2101,.F.);
#2109=CARTESIAN_POINT('',(28.3936164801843,68.58,-14.8360543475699));
#2110=DIRECTION('',(0.,1.,0.));
#2111=DIRECTION('',(1.,0.,0.));
#2112=AXIS2_PLACEMENT_3D('',#2109,#2110,#2111);
#2113=PLANE('',#2112);
#2114=CARTESIAN_POINT('',(25.4590261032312,68.58,-25.4590261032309));
#2115=DIRECTION('',(0.,1.,0.));
#2116=DIRECTION('',(0.,0.,1.));
#2117=AXIS2_PLACEMENT_3D('',#2114,#2115,#2116);
#2118=CIRCLE('',#2117,4.7625);
#2119=CARTESIAN_POINT('',(25.4590261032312,68.58,-20.6965261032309));
#2120=VERTEX_POINT('',#2119);
#2121=EDGE_CURVE('E928',#2120,#2120,#2118,.T.);
#2122=ORIENTED_EDGE('',*,*,#2121,.F.);
#2123=EDGE_LOOP('',(#2122));
#2124=FACE_BOUND('',#2123,.T.);
#2125=ORIENTED_EDGE('',*,*,#1119,.F.);
#2126=DIRECTION('',(-0.961617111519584,0.,0.274394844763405));
#2127=VECTOR('',#2126,1.);
#2128=CARTESIAN_POINT('',(20.8245916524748,68.58,-29.9486076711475));
#2129=LINE('',#2128,#2127);
#2130=CARTESIAN_POINT('',(20.8245916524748,68.58,-29.9486076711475));
#2131=VERTEX_POINT('',#2130);
#2132=EDGE_CURVE('E696',#179,#2131,#2129,.T.);
#2133=ORIENTED_EDGE('',*,*,#2132,.T.);
#2134=DIRECTION('',(-0.243453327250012,0.,0.969912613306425));
#2135=VECTOR('',#2134,1.);
#2136=CARTESIAN_POINT('',(20.8245916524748,68.58,-29.9486076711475));
#2137=LINE('',#2136,#2135);
#2138=CARTESIAN_POINT('',(19.2537171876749,68.58,-23.6902789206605));
#2139=VERTEX_POINT('',#2138);
#2140=EDGE_CURVE('E700',#2131,#2139,#2137,.T.);
#2141=ORIENTED_EDGE('',*,*,#2140,.T.);
#2142=DIRECTION('',(0.71824229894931,0.,0.69579307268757));
#2143=VECTOR('',#2142,1.);
#2144=CARTESIAN_POINT('',(19.2537171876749,68.58,-23.6902789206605));
#2145=LINE('',#2144,#2143);
#2146=CARTESIAN_POINT('',(23.8881516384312,68.58,-19.2006973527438));
#2147=VERTEX_POINT('',#2146);
#2148=EDGE_CURVE('E704',#2139,#2147,#2145,.T.);
#2149=ORIENTED_EDGE('',*,*,#2148,.T.);
#2150=DIRECTION('',(0.961695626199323,0.,-0.274119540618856));
#2151=VECTOR('',#2150,1.);
#2152=CARTESIAN_POINT('',(23.8881516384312,68.58,-19.2006973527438));
#2153=LINE('',#2152,#2151);
#2154=CARTESIAN_POINT('',(30.0934605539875,68.58,-20.9694445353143));
#2155=VERTEX_POINT('',#2154);
#2156=EDGE_CURVE('E708',#2147,#2155,#2153,.T.);
#2157=ORIENTED_EDGE('',*,*,#2156,.T.);
#2158=DIRECTION('',(0.26707853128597,0.,-0.963674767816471));
#2159=VECTOR('',#2158,1.);
#2160=CARTESIAN_POINT('',(33.591654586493,68.58,-33.5916545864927));
#2161=LINE('',#2160,#2159);
#2162=EDGE_CURVE('E692',#2155,#38,#2161,.T.);
#2163=ORIENTED_EDGE('',*,*,#2162,.T.);
#2164=EDGE_LOOP('',(#2125,#2133,#2141,#2149,#2157,#2163));
#2165=FACE_BOUND('',#2164,.T.);
#2166=ADVANCED_FACE('F768',(#2124,#2165),#2113,.T.);
#2167=CARTESIAN_POINT('',(33.591654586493,68.58,-33.5916545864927));
#2168=DIRECTION('',(0.963674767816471,0.,0.267078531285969));
#2169=DIRECTION('',(0.26707853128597,0.,-0.963674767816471));
#2170=AXIS2_PLACEMENT_3D('',#2167,#2168,#2169);
#2171=PLANE('',#2170);
#2172=ORIENTED_EDGE('',*,*,#39,.T.);
#2173=ORIENTED_EDGE('',*,*,#2162,.F.);
#2174=DIRECTION('',(0.,1.,0.));
#2175=VECTOR('',#2174,1.);
#2176=CARTESIAN_POINT('',(30.0934605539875,68.58,-20.9694445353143));
#2177=LINE('',#2176,#2175);
#2178=EDGE_CURVE('E726',#2155,#1794,#2177,.T.);
#2179=ORIENTED_EDGE('',*,*,#2178,.T.);
#2180=ORIENTED_EDGE('',*,*,#1795,.T.);
#2181=EDGE_LOOP('',(#2172,#2173,#2179,#2180));
#2182=FACE_BOUND('',#2181,.T.);
#2183=ADVANCED_FACE('F763',(#2182),#2171,.F.);
#2184=CARTESIAN_POINT('',(23.8881516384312,68.58,-19.2006973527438));
#2185=DIRECTION('',(0.274119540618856,0.,0.961695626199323));
#2186=DIRECTION('',(0.961695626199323,0.,-0.274119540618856));
#2187=AXIS2_PLACEMENT_3D('',#2184,#2185,#2186);
#2188=PLANE('',#2187);
#2189=ORIENTED_EDGE('',*,*,#1803,.T.);
#2190=ORIENTED_EDGE('',*,*,#2178,.F.);
#2191=ORIENTED_EDGE('',*,*,#2156,.F.);
#2192=DIRECTION('',(0.,1.,0.));
#2193=VECTOR('',#2192,1.);
#2194=CARTESIAN_POINT('',(23.8881516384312,68.58,-19.2006973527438));
#2195=LINE('',#2194,#2193);
#2196=EDGE_CURVE('E730',#2147,#1802,#2195,.T.);
#2197=ORIENTED_EDGE('',*,*,#2196,.T.);
#2198=EDGE_LOOP('',(#2189,#2190,#2191,#2197));
#2199=FACE_BOUND('',#2198,.T.);
#2200=ADVANCED_FACE('F767',(#2199),#2188,.F.);
#2201=CARTESIAN_POINT('',(19.2537171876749,68.58,-23.6902789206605));
#2202=DIRECTION('',(-0.69579307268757,0.,0.71824229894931));
#2203=DIRECTION('',(0.71824229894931,0.,0.69579307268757));
#2204=AXIS2_PLACEMENT_3D('',#2201,#2202,#2203);
#2205=PLANE('',#2204);
#2206=ORIENTED_EDGE('',*,*,#1811,.T.);
#2207=ORIENTED_EDGE('',*,*,#2196,.F.);
#2208=ORIENTED_EDGE('',*,*,#2148,.F.);
#2209=DIRECTION('',(0.,1.,0.));
#2210=VECTOR('',#2209,1.);
#2211=CARTESIAN_POINT('',(19.2537171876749,68.58,-23.6902789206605));
#2212=LINE('',#2211,#2210);
#2213=EDGE_CURVE('E733',#2139,#1810,#2212,.T.);
#2214=ORIENTED_EDGE('',*,*,#2213,.T.);
#2215=EDGE_LOOP('',(#2206,#2207,#2208,#2214));
#2216=FACE_BOUND('',#2215,.T.);
#2217=ADVANCED_FACE('F1136',(#2216),#2205,.F.);
#2218=CARTESIAN_POINT('',(20.8245916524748,68.58,-29.9486076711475));
#2219=DIRECTION('',(-0.969912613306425,0.,-0.243453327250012));
#2220=DIRECTION('',(-0.243453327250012,0.,0.969912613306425));
#2221=AXIS2_PLACEMENT_3D('',#2218,#2219,#2220);
#2222=PLANE('',#2221);
#2223=ORIENTED_EDGE('',*,*,#1819,.T.);
#2224=ORIENTED_EDGE('',*,*,#2213,.F.);
#2225=ORIENTED_EDGE('',*,*,#2140,.F.);
#2226=DIRECTION('',(0.,1.,0.));
#2227=VECTOR('',#2226,1.);
#2228=CARTESIAN_POINT('',(20.8245916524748,68.58,-29.9486076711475));
#2229=LINE('',#2228,#2227);
#2230=EDGE_CURVE('E712',#2131,#1818,#2229,.T.);
#2231=ORIENTED_EDGE('',*,*,#2230,.T.);
#2232=EDGE_LOOP('',(#2223,#2224,#2225,#2231));
#2233=FACE_BOUND('',#2232,.T.);
#2234=ADVANCED_FACE('F760',(#2233),#2222,.F.);
#2235=CARTESIAN_POINT('',(20.8245916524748,68.58,-29.9486076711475));
#2236=DIRECTION('',(-0.274394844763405,0.,-0.961617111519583));
#2237=DIRECTION('',(-0.961617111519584,0.,0.274394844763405));
#2238=AXIS2_PLACEMENT_3D('',#2235,#2236,#2237);
#2239=PLANE('',#2238);
#2240=ORIENTED_EDGE('',*,*,#180,.T.);
#2241=ORIENTED_EDGE('',*,*,#1825,.T.);
#2242=ORIENTED_EDGE('',*,*,#2230,.F.);
#2243=ORIENTED_EDGE('',*,*,#2132,.F.);
#2244=EDGE_LOOP('',(#2240,#2241,#2242,#2243));
#2245=FACE_BOUND('',#2244,.T.);
#2246=ADVANCED_FACE('F755',(#2245),#2239,.F.);
#2247=CARTESIAN_POINT('',(25.4590261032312,55.1096158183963,25.4590261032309));
#2248=DIRECTION('',(0.,1.,0.));
#2249=DIRECTION('',(0.,0.,1.));
#2250=AXIS2_PLACEMENT_3D('',#2247,#2248,#2249);
#2251=CYLINDRICAL_SURFACE('',#2250,4.7625);
#2252=CARTESIAN_POINT('',(25.4590261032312,74.168,25.4590261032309));
#2253=DIRECTION('',(0.,1.,0.));
#2254=DIRECTION('',(0.,0.,1.));
#2255=AXIS2_PLACEMENT_3D('',#2252,#2253,#2254);
#2256=CIRCLE('',#2255,4.7625);
#2257=CARTESIAN_POINT('',(25.4590261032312,74.168,30.2215261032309));
#2258=VERTEX_POINT('',#2257);
#2259=EDGE_CURVE('E952',#2258,#2258,#2256,.F.);
#2260=ORIENTED_EDGE('',*,*,#2259,.T.);
#2261=EDGE_LOOP('',(#2260));
#2262=FACE_BOUND('',#2261,.T.);
#2263=ORIENTED_EDGE('',*,*,#1512,.T.);
#2264=EDGE_LOOP('',(#2263));
#2265=FACE_BOUND('',#2264,.T.);
#2266=ADVANCED_FACE('F759',(#2262,#2265),#2251,.T.);
#2267=CARTESIAN_POINT('',(25.4590261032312,74.93,25.4590261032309));
#2268=DIRECTION('',(0.,1.,0.));
#2269=DIRECTION('',(0.,0.,1.));
#2270=AXIS2_PLACEMENT_3D('',#2267,#2268,#2269);
#2271=PLANE('',#2270);
#2272=CARTESIAN_POINT('',(25.4590261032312,74.93,25.4590261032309));
#2273=DIRECTION('',(0.,1.,0.));
#2274=DIRECTION('',(0.,0.,1.));
#2275=AXIS2_PLACEMENT_3D('',#2272,#2273,#2274);
#2276=CIRCLE('',#2275,4.00050000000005);
#2277=CARTESIAN_POINT('',(25.4590261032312,74.93,29.459526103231));
#2278=VERTEX_POINT('',#2277);
#2279=EDGE_CURVE('E948',#2278,#2278,#2276,.T.);
#2280=ORIENTED_EDGE('',*,*,#2279,.T.);
#2281=EDGE_LOOP('',(#2280));
#2282=FACE_BOUND('',#2281,.T.);
#2283=DIRECTION('',(0.499999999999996,0.,-0.866025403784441));
#2284=VECTOR('',#2283,1.);
#2285=CARTESIAN_POINT('',(26.8230769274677,74.93,27.8216314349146));
#2286=LINE('',#2285,#2284);
#2287=CARTESIAN_POINT('',(26.8230769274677,74.93,27.8216314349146));
#2288=VERTEX_POINT('',#2287);
#2289=CARTESIAN_POINT('',(28.1871277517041,74.93,25.4590261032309));
#2290=VERTEX_POINT('',#2289);
#2291=EDGE_CURVE('E610',#2288,#2290,#2286,.T.);
#2292=ORIENTED_EDGE('',*,*,#2291,.F.);
#2293=DIRECTION('',(1.,0.,0.));
#2294=VECTOR('',#2293,1.);
#2295=CARTESIAN_POINT('',(24.0949752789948,74.93,27.8216314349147));
#2296=LINE('',#2295,#2294);
#2297=CARTESIAN_POINT('',(24.0949752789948,74.93,27.8216314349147));
#2298=VERTEX_POINT('',#2297);
#2299=EDGE_CURVE('E631',#2298,#2288,#2296,.T.);
#2300=ORIENTED_EDGE('',*,*,#2299,.F.);
#2301=DIRECTION('',(0.500000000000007,0.,0.866025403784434));
#2302=VECTOR('',#2301,1.);
#2303=CARTESIAN_POINT('',(22.7309244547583,74.93,25.4590261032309));
#2304=LINE('',#2303,#2302);
#2305=CARTESIAN_POINT('',(22.7309244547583,74.93,25.4590261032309));
#2306=VERTEX_POINT('',#2305);
#2307=EDGE_CURVE('E666',#2306,#2298,#2304,.T.);
#2308=ORIENTED_EDGE('',*,*,#2307,.F.);
#2309=DIRECTION('',(-0.499999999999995,0.,0.866025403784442));
#2310=VECTOR('',#2309,1.);
#2311=CARTESIAN_POINT('',(24.0949752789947,74.93,23.0964207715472));
#2312=LINE('',#2311,#2310);
#2313=CARTESIAN_POINT('',(24.0949752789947,74.93,23.0964207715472));
#2314=VERTEX_POINT('',#2313);
#2315=EDGE_CURVE('E662',#2314,#2306,#2312,.T.);
#2316=ORIENTED_EDGE('',*,*,#2315,.F.);
#2317=DIRECTION('',(-1.,0.,0.));
#2318=VECTOR('',#2317,1.);
#2319=CARTESIAN_POINT('',(26.8230769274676,74.93,23.0964207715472));
#2320=LINE('',#2319,#2318);
#2321=CARTESIAN_POINT('',(26.8230769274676,74.93,23.0964207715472));
#2322=VERTEX_POINT('',#2321);
#2323=EDGE_CURVE('E658',#2322,#2314,#2320,.T.);
#2324=ORIENTED_EDGE('',*,*,#2323,.F.);
#2325=DIRECTION('',(-0.500000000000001,0.,-0.866025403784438));
#2326=VECTOR('',#2325,1.);
#2327=CARTESIAN_POINT('',(28.1871277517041,74.93,25.4590261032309));
#2328=LINE('',#2327,#2326);
#2329=EDGE_CURVE('E654',#2290,#2322,#2328,.T.);
#2330=ORIENTED_EDGE('',*,*,#2329,.F.);
#2331=EDGE_LOOP('',(#2292,#2300,#2308,#2316,#2324,#2330));
#2332=FACE_BOUND('',#2331,.T.);
#2333=ADVANCED_FACE('F1124',(#2282,#2332),#2271,.T.);
#2334=CARTESIAN_POINT('',(26.8230769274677,71.755,27.8216314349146));
#2335=DIRECTION('',(0.866025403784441,0.,0.499999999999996));
#2336=DIRECTION('',(0.499999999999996,0.,-0.866025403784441));
#2337=AXIS2_PLACEMENT_3D('',#2334,#2335,#2336);
#2338=PLANE('',#2337);
#2339=ORIENTED_EDGE('',*,*,#2291,.T.);
#2340=DIRECTION('',(0.,1.,0.));
#2341=VECTOR('',#2340,1.);
#2342=CARTESIAN_POINT('',(28.1871277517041,71.755,25.4590261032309));
#2343=LINE('',#2342,#2341);
#2344=CARTESIAN_POINT('',(28.1871277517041,71.755,25.4590261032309));
#2345=VERTEX_POINT('',#2344);
#2346=EDGE_CURVE('E651',#2345,#2290,#2343,.T.);
#2347=ORIENTED_EDGE('',*,*,#2346,.F.);
#2348=DIRECTION('',(0.499999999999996,0.,-0.866025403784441));
#2349=VECTOR('',#2348,1.);
#2350=CARTESIAN_POINT('',(26.8230769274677,71.755,27.8216314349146));
#2351=LINE('',#2350,#2349);
#2352=CARTESIAN_POINT('',(26.8230769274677,71.755,27.8216314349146));
#2353=VERTEX_POINT('',#2352);
#2354=EDGE_CURVE('E626',#2353,#2345,#2351,.T.);
#2355=ORIENTED_EDGE('',*,*,#2354,.F.);
#2356=DIRECTION('',(0.,1.,0.));
#2357=VECTOR('',#2356,1.);
#2358=CARTESIAN_POINT('',(26.8230769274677,71.755,27.8216314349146));
#2359=LINE('',#2358,#2357);
#2360=EDGE_CURVE('E673',#2353,#2288,#2359,.T.);
#2361=ORIENTED_EDGE('',*,*,#2360,.T.);
#2362=EDGE_LOOP('',(#2339,#2347,#2355,#2361));
#2363=FACE_BOUND('',#2362,.T.);
#2364=ADVANCED_FACE('F1106',(#2363),#2338,.F.);
#2365=CARTESIAN_POINT('',(24.0949752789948,71.755,27.8216314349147));
#2366=DIRECTION('',(0.,0.,1.));
#2367=DIRECTION('',(1.,0.,0.));
#2368=AXIS2_PLACEMENT_3D('',#2365,#2366,#2367);
#2369=PLANE('',#2368);
#2370=ORIENTED_EDGE('',*,*,#2299,.T.);
#2371=ORIENTED_EDGE('',*,*,#2360,.F.);
#2372=DIRECTION('',(1.,0.,0.));
#2373=VECTOR('',#2372,1.);
#2374=CARTESIAN_POINT('',(24.0949752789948,71.755,27.8216314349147));
#2375=LINE('',#2374,#2373);
#2376=CARTESIAN_POINT('',(24.0949752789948,71.755,27.8216314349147));
#2377=VERTEX_POINT('',#2376);
#2378=EDGE_CURVE('E647',#2377,#2353,#2375,.T.);
#2379=ORIENTED_EDGE('',*,*,#2378,.F.);
#2380=DIRECTION('',(0.,1.,0.));
#2381=VECTOR('',#2380,1.);
#2382=CARTESIAN_POINT('',(24.0949752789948,71.755,27.8216314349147));
#2383=LINE('',#2382,#2381);
#2384=EDGE_CURVE('E677',#2377,#2298,#2383,.T.);
#2385=ORIENTED_EDGE('',*,*,#2384,.T.);
#2386=EDGE_LOOP('',(#2370,#2371,#2379,#2385));
#2387=FACE_BOUND('',#2386,.T.);
#2388=ADVANCED_FACE('F1102',(#2387),#2369,.F.);
#2389=CARTESIAN_POINT('',(22.7309244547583,71.755,25.4590261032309));
#2390=DIRECTION('',(-0.866025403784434,0.,0.500000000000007));
#2391=DIRECTION('',(0.500000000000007,0.,0.866025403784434));
#2392=AXIS2_PLACEMENT_3D('',#2389,#2390,#2391);
#2393=PLANE('',#2392);
#2394=ORIENTED_EDGE('',*,*,#2307,.T.);
#2395=ORIENTED_EDGE('',*,*,#2384,.F.);
#2396=DIRECTION('',(0.500000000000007,0.,0.866025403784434));
#2397=VECTOR('',#2396,1.);
#2398=CARTESIAN_POINT('',(22.7309244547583,71.755,25.4590261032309));
#2399=LINE('',#2398,#2397);
#2400=CARTESIAN_POINT('',(22.7309244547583,71.755,25.4590261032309));
#2401=VERTEX_POINT('',#2400);
#2402=EDGE_CURVE('E643',#2401,#2377,#2399,.T.);
#2403=ORIENTED_EDGE('',*,*,#2402,.F.);
#2404=DIRECTION('',(0.,1.,0.));
#2405=VECTOR('',#2404,1.);
#2406=CARTESIAN_POINT('',(22.7309244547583,71.755,25.4590261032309));
#2407=LINE('',#2406,#2405);
#2408=EDGE_CURVE('E680',#2401,#2306,#2407,.T.);
#2409=ORIENTED_EDGE('',*,*,#2408,.T.);
#2410=EDGE_LOOP('',(#2394,#2395,#2403,#2409));
#2411=FACE_BOUND('',#2410,.T.);
#2412=ADVANCED_FACE('F1105',(#2411),#2393,.F.);
#2413=CARTESIAN_POINT('',(24.0949752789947,71.755,23.0964207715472));
#2414=DIRECTION('',(-0.866025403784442,0.,-0.499999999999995));
#2415=DIRECTION('',(-0.499999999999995,0.,0.866025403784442));
#2416=AXIS2_PLACEMENT_3D('',#2413,#2414,#2415);
#2417=PLANE('',#2416);
#2418=ORIENTED_EDGE('',*,*,#2315,.T.);
#2419=ORIENTED_EDGE('',*,*,#2408,.F.);
#2420=DIRECTION('',(-0.499999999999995,0.,0.866025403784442));
#2421=VECTOR('',#2420,1.);
#2422=CARTESIAN_POINT('',(24.0949752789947,71.755,23.0964207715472));
#2423=LINE('',#2422,#2421);
#2424=CARTESIAN_POINT('',(24.0949752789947,71.755,23.0964207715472));
#2425=VERTEX_POINT('',#2424);
#2426=EDGE_CURVE('E639',#2425,#2401,#2423,.T.);
#2427=ORIENTED_EDGE('',*,*,#2426,.F.);
#2428=DIRECTION('',(0.,1.,0.));
#2429=VECTOR('',#2428,1.);
#2430=CARTESIAN_POINT('',(24.0949752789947,71.755,23.0964207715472));
#2431=LINE('',#2430,#2429);
#2432=EDGE_CURVE('E683',#2425,#2314,#2431,.T.);
#2433=ORIENTED_EDGE('',*,*,#2432,.T.);
#2434=EDGE_LOOP('',(#2418,#2419,#2427,#2433));
#2435=FACE_BOUND('',#2434,.T.);
#2436=ADVANCED_FACE('F1110',(#2435),#2417,.F.);
#2437=CARTESIAN_POINT('',(26.8230769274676,71.755,23.0964207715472));
#2438=DIRECTION('',(0.,0.,-1.));
#2439=DIRECTION('',(-1.,0.,0.));
#2440=AXIS2_PLACEMENT_3D('',#2437,#2438,#2439);
#2441=PLANE('',#2440);
#2442=ORIENTED_EDGE('',*,*,#2323,.T.);
#2443=ORIENTED_EDGE('',*,*,#2432,.F.);
#2444=DIRECTION('',(-1.,0.,0.));
#2445=VECTOR('',#2444,1.);
#2446=CARTESIAN_POINT('',(26.8230769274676,71.755,23.0964207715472));
#2447=LINE('',#2446,#2445);
#2448=CARTESIAN_POINT('',(26.8230769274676,71.755,23.0964207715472));
#2449=VERTEX_POINT('',#2448);
#2450=EDGE_CURVE('E635',#2449,#2425,#2447,.T.);
#2451=ORIENTED_EDGE('',*,*,#2450,.F.);
#2452=DIRECTION('',(0.,1.,0.));
#2453=VECTOR('',#2452,1.);
#2454=CARTESIAN_POINT('',(26.8230769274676,71.755,23.0964207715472));
#2455=LINE('',#2454,#2453);
#2456=EDGE_CURVE('E686',#2449,#2322,#2455,.T.);
#2457=ORIENTED_EDGE('',*,*,#2456,.T.);
#2458=EDGE_LOOP('',(#2442,#2443,#2451,#2457));
#2459=FACE_BOUND('',#2458,.T.);
#2460=ADVANCED_FACE('F1114',(#2459),#2441,.F.);
#2461=CARTESIAN_POINT('',(28.1871277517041,71.755,25.4590261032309));
#2462=DIRECTION('',(0.866025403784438,0.,-0.500000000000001));
#2463=DIRECTION('',(-0.500000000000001,0.,-0.866025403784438));
#2464=AXIS2_PLACEMENT_3D('',#2461,#2462,#2463);
#2465=PLANE('',#2464);
#2466=ORIENTED_EDGE('',*,*,#2329,.T.);
#2467=ORIENTED_EDGE('',*,*,#2456,.F.);
#2468=DIRECTION('',(-0.500000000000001,0.,-0.866025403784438));
#2469=VECTOR('',#2468,1.);
#2470=CARTESIAN_POINT('',(28.1871277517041,71.755,25.4590261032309));
#2471=LINE('',#2470,#2469);
#2472=EDGE_CURVE('E630',#2345,#2449,#2471,.T.);
#2473=ORIENTED_EDGE('',*,*,#2472,.F.);
#2474=ORIENTED_EDGE('',*,*,#2346,.T.);
#2475=EDGE_LOOP('',(#2466,#2467,#2473,#2474));
#2476=FACE_BOUND('',#2475,.T.);
#2477=ADVANCED_FACE('F1100',(#2476),#2465,.F.);
#2478=CARTESIAN_POINT('',(28.1871277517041,71.755,25.4590261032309));
#2479=DIRECTION('',(0.,1.,0.));
#2480=DIRECTION('',(0.,0.,1.));
#2481=AXIS2_PLACEMENT_3D('',#2478,#2479,#2480);
#2482=PLANE('',#2481);
#2483=ORIENTED_EDGE('',*,*,#2354,.T.);
#2484=ORIENTED_EDGE('',*,*,#2472,.T.);
#2485=ORIENTED_EDGE('',*,*,#2450,.T.);
#2486=ORIENTED_EDGE('',*,*,#2426,.T.);
#2487=ORIENTED_EDGE('',*,*,#2402,.T.);
#2488=ORIENTED_EDGE('',*,*,#2378,.T.);
#2489=EDGE_LOOP('',(#2483,#2484,#2485,#2486,#2487,#2488));
#2490=FACE_BOUND('',#2489,.T.);
#2491=ADVANCED_FACE('F1096',(#2490),#2482,.T.);
#2492=CARTESIAN_POINT('',(-25.459026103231,55.1096158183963,25.4590261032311));
#2493=DIRECTION('',(0.,1.,0.));
#2494=DIRECTION('',(0.,0.,1.));
#2495=AXIS2_PLACEMENT_3D('',#2492,#2493,#2494);
#2496=CYLINDRICAL_SURFACE('',#2495,4.7625);
#2497=CARTESIAN_POINT('',(-25.459026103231,74.168,25.4590261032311));
#2498=DIRECTION('',(0.,1.,0.));
#2499=DIRECTION('',(0.,0.,1.));
#2500=AXIS2_PLACEMENT_3D('',#2497,#2498,#2499);
#2501=CIRCLE('',#2500,4.7625);
#2502=CARTESIAN_POINT('',(-25.459026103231,74.168,30.2215261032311));
#2503=VERTEX_POINT('',#2502);
#2504=EDGE_CURVE('E960',#2503,#2503,#2501,.F.);
#2505=ORIENTED_EDGE('',*,*,#2504,.T.);
#2506=EDGE_LOOP('',(#2505));
#2507=FACE_BOUND('',#2506,.T.);
#2508=ORIENTED_EDGE('',*,*,#1845,.T.);
#2509=EDGE_LOOP('',(#2508));
#2510=FACE_BOUND('',#2509,.T.);
#2511=ADVANCED_FACE('F1092',(#2507,#2510),#2496,.T.);
#2512=CARTESIAN_POINT('',(-25.459026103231,74.93,25.4590261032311));
#2513=DIRECTION('',(0.,1.,0.));
#2514=DIRECTION('',(-1.,0.,0.));
#2515=AXIS2_PLACEMENT_3D('',#2512,#2513,#2514);
#2516=PLANE('',#2515);
#2517=CARTESIAN_POINT('',(-25.459026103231,74.93,25.4590261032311));
#2518=DIRECTION('',(0.,1.,0.));
#2519=DIRECTION('',(0.,0.,1.));
#2520=AXIS2_PLACEMENT_3D('',#2517,#2518,#2519);
#2521=CIRCLE('',#2520,4.00050000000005);
#2522=CARTESIAN_POINT('',(-25.459026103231,74.93,29.4595261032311));
#2523=VERTEX_POINT('',#2522);
#2524=EDGE_CURVE('E956',#2523,#2523,#2521,.T.);
#2525=ORIENTED_EDGE('',*,*,#2524,.T.);
#2526=EDGE_LOOP('',(#2525));
#2527=FACE_BOUND('',#2526,.T.);
#2528=DIRECTION('',(0.86602540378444,0.,0.499999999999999));
#2529=VECTOR('',#2528,1.);
#2530=CARTESIAN_POINT('',(-27.8216314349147,74.93,26.8230769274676));
#2531=LINE('',#2530,#2529);
#2532=CARTESIAN_POINT('',(-27.8216314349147,74.93,26.8230769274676));
#2533=VERTEX_POINT('',#2532);
#2534=CARTESIAN_POINT('',(-25.459026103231,74.93,28.187127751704));
#2535=VERTEX_POINT('',#2534);
#2536=EDGE_CURVE('E545',#2533,#2535,#2531,.T.);
#2537=ORIENTED_EDGE('',*,*,#2536,.F.);
#2538=DIRECTION('',(0.,0.,1.));
#2539=VECTOR('',#2538,1.);
#2540=CARTESIAN_POINT('',(-27.8216314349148,74.93,24.0949752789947));
#2541=LINE('',#2540,#2539);
#2542=CARTESIAN_POINT('',(-27.8216314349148,74.93,24.0949752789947));
#2543=VERTEX_POINT('',#2542);
#2544=EDGE_CURVE('E565',#2543,#2533,#2541,.T.);
#2545=ORIENTED_EDGE('',*,*,#2544,.F.);
#2546=DIRECTION('',(-0.866025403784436,0.,0.500000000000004));
#2547=VECTOR('',#2546,1.);
#2548=CARTESIAN_POINT('',(-25.459026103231,74.93,22.7309244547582));
#2549=LINE('',#2548,#2547);
#2550=CARTESIAN_POINT('',(-25.459026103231,74.93,22.7309244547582));
#2551=VERTEX_POINT('',#2550);
#2552=EDGE_CURVE('E600',#2551,#2543,#2549,.T.);
#2553=ORIENTED_EDGE('',*,*,#2552,.F.);
#2554=DIRECTION('',(-0.86602540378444,0.,-0.499999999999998));
#2555=VECTOR('',#2554,1.);
#2556=CARTESIAN_POINT('',(-23.0964207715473,74.93,24.0949752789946));
#2557=LINE('',#2556,#2555);
#2558=CARTESIAN_POINT('',(-23.0964207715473,74.93,24.0949752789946));
#2559=VERTEX_POINT('',#2558);
#2560=EDGE_CURVE('E596',#2559,#2551,#2557,.T.);
#2561=ORIENTED_EDGE('',*,*,#2560,.F.);
#2562=DIRECTION('',(0.,0.,-1.));
#2563=VECTOR('',#2562,1.);
#2564=CARTESIAN_POINT('',(-23.0964207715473,74.93,26.8230769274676));
#2565=LINE('',#2564,#2563);
#2566=CARTESIAN_POINT('',(-23.0964207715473,74.93,26.8230769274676));
#2567=VERTEX_POINT('',#2566);
#2568=EDGE_CURVE('E592',#2567,#2559,#2565,.T.);
#2569=ORIENTED_EDGE('',*,*,#2568,.F.);
#2570=DIRECTION('',(0.86602540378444,0.,-0.499999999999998));
#2571=VECTOR('',#2570,1.);
#2572=CARTESIAN_POINT('',(-25.459026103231,74.93,28.187127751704));
#2573=LINE('',#2572,#2571);
#2574=EDGE_CURVE('E588',#2535,#2567,#2573,.T.);
#2575=ORIENTED_EDGE('',*,*,#2574,.F.);
#2576=EDGE_LOOP('',(#2537,#2545,#2553,#2561,#2569,#2575));
#2577=FACE_BOUND('',#2576,.T.);
#2578=ADVANCED_FACE('F1088',(#2527,#2577),#2516,.T.);
#2579=CARTESIAN_POINT('',(-25.459026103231,55.1096158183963,-25.4590261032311));
#2580=DIRECTION('',(0.,1.,0.));
#2581=DIRECTION('',(0.,0.,1.));
#2582=AXIS2_PLACEMENT_3D('',#2579,#2580,#2581);
#2583=CYLINDRICAL_SURFACE('',#2582,4.7625);
#2584=CARTESIAN_POINT('',(-25.459026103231,74.168,-25.4590261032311));
#2585=DIRECTION('',(0.,1.,0.));
#2586=DIRECTION('',(0.,0.,1.));
#2587=AXIS2_PLACEMENT_3D('',#2584,#2585,#2586);
#2588=CIRCLE('',#2587,4.7625);
#2589=CARTESIAN_POINT('',(-25.459026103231,74.168,-20.6965261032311));
#2590=VERTEX_POINT('',#2589);
#2591=EDGE_CURVE('E936',#2590,#2590,#2588,.F.);
#2592=ORIENTED_EDGE('',*,*,#2591,.T.);
#2593=EDGE_LOOP('',(#2592));
#2594=FACE_BOUND('',#2593,.T.);
#2595=ORIENTED_EDGE('',*,*,#1983,.T.);
#2596=EDGE_LOOP('',(#2595));
#2597=FACE_BOUND('',#2596,.T.);
#2598=ADVANCED_FACE('F1084',(#2594,#2597),#2583,.T.);
#2599=CARTESIAN_POINT('',(-25.459026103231,74.93,-25.4590261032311));
#2600=DIRECTION('',(0.,1.,0.));
#2601=DIRECTION('',(0.,0.,-1.));
#2602=AXIS2_PLACEMENT_3D('',#2599,#2600,#2601);
#2603=PLANE('',#2602);
#2604=CARTESIAN_POINT('',(-25.459026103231,74.93,-25.4590261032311));
#2605=DIRECTION('',(0.,1.,0.));
#2606=DIRECTION('',(0.,0.,1.));
#2607=AXIS2_PLACEMENT_3D('',#2604,#2605,#2606);
#2608=CIRCLE('',#2607,4.00050000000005);
#2609=CARTESIAN_POINT('',(-25.459026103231,74.93,-21.458526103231));
#2610=VERTEX_POINT('',#2609);
#2611=EDGE_CURVE('E932',#2610,#2610,#2608,.T.);
#2612=ORIENTED_EDGE('',*,*,#2611,.T.);
#2613=EDGE_LOOP('',(#2612));
#2614=FACE_BOUND('',#2613,.T.);
#2615=DIRECTION('',(-0.500000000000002,0.,0.866025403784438));
#2616=VECTOR('',#2615,1.);
#2617=CARTESIAN_POINT('',(-26.8230769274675,74.93,-27.8216314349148));
#2618=LINE('',#2617,#2616);
#2619=CARTESIAN_POINT('',(-26.8230769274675,74.93,-27.8216314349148));
#2620=VERTEX_POINT('',#2619);
#2621=CARTESIAN_POINT('',(-28.1871277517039,74.93,-25.4590261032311));
#2622=VERTEX_POINT('',#2621);
#2623=EDGE_CURVE('E65',#2620,#2622,#2618,.T.);
#2624=ORIENTED_EDGE('',*,*,#2623,.F.);
#2625=DIRECTION('',(-1.,0.,0.));
#2626=VECTOR('',#2625,1.);
#2627=CARTESIAN_POINT('',(-24.0949752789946,74.93,-27.8216314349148));
#2628=LINE('',#2627,#2626);
#2629=CARTESIAN_POINT('',(-24.0949752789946,74.93,-27.8216314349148));
#2630=VERTEX_POINT('',#2629);
#2631=EDGE_CURVE('E501',#2630,#2620,#2628,.T.);
#2632=ORIENTED_EDGE('',*,*,#2631,.F.);
#2633=DIRECTION('',(-0.500000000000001,0.,-0.866025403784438));
#2634=VECTOR('',#2633,1.);
#2635=CARTESIAN_POINT('',(-22.7309244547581,74.93,-25.4590261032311));
#2636=LINE('',#2635,#2634);
#2637=CARTESIAN_POINT('',(-22.7309244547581,74.93,-25.4590261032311));
#2638=VERTEX_POINT('',#2637);
#2639=EDGE_CURVE('E535',#2638,#2630,#2636,.T.);
#2640=ORIENTED_EDGE('',*,*,#2639,.F.);
#2641=DIRECTION('',(0.500000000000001,0.,-0.866025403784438));
#2642=VECTOR('',#2641,1.);
#2643=CARTESIAN_POINT('',(-24.0949752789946,74.93,-23.0964207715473));
#2644=LINE('',#2643,#2642);
#2645=CARTESIAN_POINT('',(-24.0949752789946,74.93,-23.0964207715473));
#2646=VERTEX_POINT('',#2645);
#2647=EDGE_CURVE('E531',#2646,#2638,#2644,.T.);
#2648=ORIENTED_EDGE('',*,*,#2647,.F.);
#2649=DIRECTION('',(1.,0.,0.));
#2650=VECTOR('',#2649,1.);
#2651=CARTESIAN_POINT('',(-26.8230769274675,74.93,-23.0964207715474));
#2652=LINE('',#2651,#2650);
#2653=CARTESIAN_POINT('',(-26.8230769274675,74.93,-23.0964207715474));
#2654=VERTEX_POINT('',#2653);
#2655=EDGE_CURVE('E527',#2654,#2646,#2652,.T.);
#2656=ORIENTED_EDGE('',*,*,#2655,.F.);
#2657=DIRECTION('',(0.499999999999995,0.,0.866025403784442));
#2658=VECTOR('',#2657,1.);
#2659=CARTESIAN_POINT('',(-28.1871277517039,74.93,-25.4590261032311));
#2660=LINE('',#2659,#2658);
#2661=EDGE_CURVE('E523',#2622,#2654,#2660,.T.);
#2662=ORIENTED_EDGE('',*,*,#2661,.F.);
#2663=EDGE_LOOP('',(#2624,#2632,#2640,#2648,#2656,#2662));
#2664=FACE_BOUND('',#2663,.T.);
#2665=ADVANCED_FACE('F1080',(#2614,#2664),#2603,.T.);
#2666=CARTESIAN_POINT('',(25.4590261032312,55.1096158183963,-25.4590261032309));
#2667=DIRECTION('',(0.,1.,0.));
#2668=DIRECTION('',(0.,0.,1.));
#2669=AXIS2_PLACEMENT_3D('',#2666,#2667,#2668);
#2670=CYLINDRICAL_SURFACE('',#2669,4.7625);
#2671=CARTESIAN_POINT('',(25.4590261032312,74.168,-25.4590261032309));
#2672=DIRECTION('',(0.,1.,0.));
#2673=DIRECTION('',(0.,0.,1.));
#2674=AXIS2_PLACEMENT_3D('',#2671,#2672,#2673);
#2675=CIRCLE('',#2674,4.7625);
#2676=CARTESIAN_POINT('',(25.4590261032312,74.168,-20.6965261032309));
#2677=VERTEX_POINT('',#2676);
#2678=EDGE_CURVE('E944',#2677,#2677,#2675,.F.);
#2679=ORIENTED_EDGE('',*,*,#2678,.T.);
#2680=EDGE_LOOP('',(#2679));
#2681=FACE_BOUND('',#2680,.T.);
#2682=ORIENTED_EDGE('',*,*,#2121,.T.);
#2683=EDGE_LOOP('',(#2682));
#2684=FACE_BOUND('',#2683,.T.);
#2685=ADVANCED_FACE('F1076',(#2681,#2684),#2670,.T.);
#2686=CARTESIAN_POINT('',(25.4590261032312,74.93,-25.4590261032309));
#2687=DIRECTION('',(0.,1.,0.));
#2688=DIRECTION('',(1.,0.,0.));
#2689=AXIS2_PLACEMENT_3D('',#2686,#2687,#2688);
#2690=PLANE('',#2689);
#2691=CARTESIAN_POINT('',(25.4590261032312,74.93,-25.4590261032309));
#2692=DIRECTION('',(0.,1.,0.));
#2693=DIRECTION('',(0.,0.,1.));
#2694=AXIS2_PLACEMENT_3D('',#2691,#2692,#2693);
#2695=CIRCLE('',#2694,4.00050000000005);
#2696=CARTESIAN_POINT('',(25.4590261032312,74.93,-21.4585261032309));
#2697=VERTEX_POINT('',#2696);
#2698=EDGE_CURVE('E940',#2697,#2697,#2695,.T.);
#2699=ORIENTED_EDGE('',*,*,#2698,.T.);
#2700=EDGE_LOOP('',(#2699));
#2701=FACE_BOUND('',#2700,.T.);
#2702=DIRECTION('',(-0.866025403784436,0.,-0.500000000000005));
#2703=VECTOR('',#2702,1.);
#2704=CARTESIAN_POINT('',(27.8216314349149,74.93,-26.8230769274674));
#2705=LINE('',#2704,#2703);
#2706=CARTESIAN_POINT('',(27.8216314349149,74.93,-26.8230769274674));
#2707=VERTEX_POINT('',#2706);
#2708=CARTESIAN_POINT('',(25.4590261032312,74.93,-28.1871277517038));
#2709=VERTEX_POINT('',#2708);
#2710=EDGE_CURVE('E57',#2707,#2709,#2705,.T.);
#2711=ORIENTED_EDGE('',*,*,#2710,.F.);
#2712=DIRECTION('',(0.,0.,-1.));
#2713=VECTOR('',#2712,1.);
#2714=CARTESIAN_POINT('',(27.8216314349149,74.93,-24.0949752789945));
#2715=LINE('',#2714,#2713);
#2716=CARTESIAN_POINT('',(27.8216314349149,74.93,-24.0949752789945));
#2717=VERTEX_POINT('',#2716);
#2718=EDGE_CURVE('E437',#2717,#2707,#2715,.T.);
#2719=ORIENTED_EDGE('',*,*,#2718,.F.);
#2720=DIRECTION('',(0.86602540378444,0.,-0.499999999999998));
#2721=VECTOR('',#2720,1.);
#2722=CARTESIAN_POINT('',(25.4590261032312,74.93,-22.730924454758));
#2723=LINE('',#2722,#2721);
#2724=CARTESIAN_POINT('',(25.4590261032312,74.93,-22.730924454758));
#2725=VERTEX_POINT('',#2724);
#2726=EDGE_CURVE('E472',#2725,#2717,#2723,.T.);
#2727=ORIENTED_EDGE('',*,*,#2726,.F.);
#2728=DIRECTION('',(0.866025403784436,0.,0.500000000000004));
#2729=VECTOR('',#2728,1.);
#2730=CARTESIAN_POINT('',(23.0964207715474,74.93,-24.0949752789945));
#2731=LINE('',#2730,#2729);
#2732=CARTESIAN_POINT('',(23.0964207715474,74.93,-24.0949752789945));
#2733=VERTEX_POINT('',#2732);
#2734=EDGE_CURVE('E468',#2733,#2725,#2731,.T.);
#2735=ORIENTED_EDGE('',*,*,#2734,.F.);
#2736=DIRECTION('',(0.,0.,1.));
#2737=VECTOR('',#2736,1.);
#2738=CARTESIAN_POINT('',(23.0964207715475,74.93,-26.8230769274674));
#2739=LINE('',#2738,#2737);
#2740=CARTESIAN_POINT('',(23.0964207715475,74.93,-26.8230769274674));
#2741=VERTEX_POINT('',#2740);
#2742=EDGE_CURVE('E464',#2741,#2733,#2739,.T.);
#2743=ORIENTED_EDGE('',*,*,#2742,.F.);
#2744=DIRECTION('',(-0.866025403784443,0.,0.499999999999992));
#2745=VECTOR('',#2744,1.);
#2746=CARTESIAN_POINT('',(25.4590261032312,74.93,-28.1871277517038));
#2747=LINE('',#2746,#2745);
#2748=EDGE_CURVE('E460',#2709,#2741,#2747,.T.);
#2749=ORIENTED_EDGE('',*,*,#2748,.F.);
#2750=EDGE_LOOP('',(#2711,#2719,#2727,#2735,#2743,#2749));
#2751=FACE_BOUND('',#2750,.T.);
#2752=ADVANCED_FACE('F1072',(#2701,#2751),#2690,.T.);
#2753=CARTESIAN_POINT('',(-27.8216314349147,71.755,26.8230769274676));
#2754=DIRECTION('',(-0.499999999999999,0.,0.866025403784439));
#2755=DIRECTION('',(0.866025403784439,0.,0.499999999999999));
#2756=AXIS2_PLACEMENT_3D('',#2753,#2754,#2755);
#2757=PLANE('',#2756);
#2758=ORIENTED_EDGE('',*,*,#2536,.T.);
#2759=DIRECTION('',(0.,1.,0.));
#2760=VECTOR('',#2759,1.);
#2761=CARTESIAN_POINT('',(-25.459026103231,71.755,28.187127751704));
#2762=LINE('',#2761,#2760);
#2763=CARTESIAN_POINT('',(-25.459026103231,71.755,28.187127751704));
#2764=VERTEX_POINT('',#2763);
#2765=EDGE_CURVE('E585',#2764,#2535,#2762,.T.);
#2766=ORIENTED_EDGE('',*,*,#2765,.F.);
#2767=DIRECTION('',(0.86602540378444,0.,0.499999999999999));
#2768=VECTOR('',#2767,1.);
#2769=CARTESIAN_POINT('',(-27.8216314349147,71.755,26.8230769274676));
#2770=LINE('',#2769,#2768);
#2771=CARTESIAN_POINT('',(-27.8216314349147,71.755,26.8230769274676));
#2772=VERTEX_POINT('',#2771);
#2773=EDGE_CURVE('E560',#2772,#2764,#2770,.T.);
#2774=ORIENTED_EDGE('',*,*,#2773,.F.);
#2775=DIRECTION('',(0.,1.,0.));
#2776=VECTOR('',#2775,1.);
#2777=CARTESIAN_POINT('',(-27.8216314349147,71.755,26.8230769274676));
#2778=LINE('',#2777,#2776);
#2779=EDGE_CURVE('E607',#2772,#2533,#2778,.T.);
#2780=ORIENTED_EDGE('',*,*,#2779,.T.);
#2781=EDGE_LOOP('',(#2758,#2766,#2774,#2780));
#2782=FACE_BOUND('',#2781,.T.);
#2783=ADVANCED_FACE('F1054',(#2782),#2757,.F.);
#2784=CARTESIAN_POINT('',(-27.8216314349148,71.755,24.0949752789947));
#2785=DIRECTION('',(-1.,0.,0.));
#2786=DIRECTION('',(0.,0.,1.));
#2787=AXIS2_PLACEMENT_3D('',#2784,#2785,#2786);
#2788=PLANE('',#2787);
#2789=ORIENTED_EDGE('',*,*,#2544,.T.);
#2790=ORIENTED_EDGE('',*,*,#2779,.F.);
#2791=DIRECTION('',(0.,0.,1.));
#2792=VECTOR('',#2791,1.);
#2793=CARTESIAN_POINT('',(-27.8216314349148,71.755,24.0949752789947));
#2794=LINE('',#2793,#2792);
#2795=CARTESIAN_POINT('',(-27.8216314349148,71.755,24.0949752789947));
#2796=VERTEX_POINT('',#2795);
#2797=EDGE_CURVE('E581',#2796,#2772,#2794,.T.);
#2798=ORIENTED_EDGE('',*,*,#2797,.F.);
#2799=DIRECTION('',(0.,1.,0.));
#2800=VECTOR('',#2799,1.);
#2801=CARTESIAN_POINT('',(-27.8216314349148,71.755,24.0949752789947));
#2802=LINE('',#2801,#2800);
#2803=EDGE_CURVE('E611',#2796,#2543,#2802,.T.);
#2804=ORIENTED_EDGE('',*,*,#2803,.T.);
#2805=EDGE_LOOP('',(#2789,#2790,#2798,#2804));
#2806=FACE_BOUND('',#2805,.T.);
#2807=ADVANCED_FACE('F1050',(#2806),#2788,.F.);
#2808=CARTESIAN_POINT('',(-25.459026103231,71.755,22.7309244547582));
#2809=DIRECTION('',(-0.500000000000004,0.,-0.866025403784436));
#2810=DIRECTION('',(-0.866025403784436,0.,0.500000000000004));
#2811=AXIS2_PLACEMENT_3D('',#2808,#2809,#2810);
#2812=PLANE('',#2811);
#2813=ORIENTED_EDGE('',*,*,#2552,.T.);
#2814=ORIENTED_EDGE('',*,*,#2803,.F.);
#2815=DIRECTION('',(-0.866025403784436,0.,0.500000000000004));
#2816=VECTOR('',#2815,1.);
#2817=CARTESIAN_POINT('',(-25.459026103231,71.755,22.7309244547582));
#2818=LINE('',#2817,#2816);
#2819=CARTESIAN_POINT('',(-25.459026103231,71.755,22.7309244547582));
#2820=VERTEX_POINT('',#2819);
#2821=EDGE_CURVE('E577',#2820,#2796,#2818,.T.);
#2822=ORIENTED_EDGE('',*,*,#2821,.F.);
#2823=DIRECTION('',(0.,1.,0.));
#2824=VECTOR('',#2823,1.);
#2825=CARTESIAN_POINT('',(-25.459026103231,71.755,22.7309244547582));
#2826=LINE('',#2825,#2824);
#2827=EDGE_CURVE('E614',#2820,#2551,#2826,.T.);
#2828=ORIENTED_EDGE('',*,*,#2827,.T.);
#2829=EDGE_LOOP('',(#2813,#2814,#2822,#2828));
#2830=FACE_BOUND('',#2829,.T.);
#2831=ADVANCED_FACE('F1053',(#2830),#2812,.F.);
#2832=CARTESIAN_POINT('',(-23.0964207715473,71.755,24.0949752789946));
#2833=DIRECTION('',(0.499999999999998,0.,-0.86602540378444));
#2834=DIRECTION('',(-0.86602540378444,0.,-0.499999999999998));
#2835=AXIS2_PLACEMENT_3D('',#2832,#2833,#2834);
#2836=PLANE('',#2835);
#2837=ORIENTED_EDGE('',*,*,#2560,.T.);
#2838=ORIENTED_EDGE('',*,*,#2827,.F.);
#2839=DIRECTION('',(-0.86602540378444,0.,-0.499999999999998));
#2840=VECTOR('',#2839,1.);
#2841=CARTESIAN_POINT('',(-23.0964207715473,71.755,24.0949752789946));
#2842=LINE('',#2841,#2840);
#2843=CARTESIAN_POINT('',(-23.0964207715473,71.755,24.0949752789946));
#2844=VERTEX_POINT('',#2843);
#2845=EDGE_CURVE('E573',#2844,#2820,#2842,.T.);
#2846=ORIENTED_EDGE('',*,*,#2845,.F.);
#2847=DIRECTION('',(0.,1.,0.));
#2848=VECTOR('',#2847,1.);
#2849=CARTESIAN_POINT('',(-23.0964207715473,71.755,24.0949752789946));
#2850=LINE('',#2849,#2848);
#2851=EDGE_CURVE('E617',#2844,#2559,#2850,.T.);
#2852=ORIENTED_EDGE('',*,*,#2851,.T.);
#2853=EDGE_LOOP('',(#2837,#2838,#2846,#2852));
#2854=FACE_BOUND('',#2853,.T.);
#2855=ADVANCED_FACE('F1058',(#2854),#2836,.F.);
#2856=CARTESIAN_POINT('',(-23.0964207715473,71.755,26.8230769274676));
#2857=DIRECTION('',(1.,0.,0.));
#2858=DIRECTION('',(0.,0.,-1.));
#2859=AXIS2_PLACEMENT_3D('',#2856,#2857,#2858);
#2860=PLANE('',#2859);
#2861=ORIENTED_EDGE('',*,*,#2568,.T.);
#2862=ORIENTED_EDGE('',*,*,#2851,.F.);
#2863=DIRECTION('',(0.,0.,-1.));
#2864=VECTOR('',#2863,1.);
#2865=CARTESIAN_POINT('',(-23.0964207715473,71.755,26.8230769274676));
#2866=LINE('',#2865,#2864);
#2867=CARTESIAN_POINT('',(-23.0964207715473,71.755,26.8230769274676));
#2868=VERTEX_POINT('',#2867);
#2869=EDGE_CURVE('E569',#2868,#2844,#2866,.T.);
#2870=ORIENTED_EDGE('',*,*,#2869,.F.);
#2871=DIRECTION('',(0.,1.,0.));
#2872=VECTOR('',#2871,1.);
#2873=CARTESIAN_POINT('',(-23.0964207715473,71.755,26.8230769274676));
#2874=LINE('',#2873,#2872);
#2875=EDGE_CURVE('E620',#2868,#2567,#2874,.T.);
#2876=ORIENTED_EDGE('',*,*,#2875,.T.);
#2877=EDGE_LOOP('',(#2861,#2862,#2870,#2876));
#2878=FACE_BOUND('',#2877,.T.);
#2879=ADVANCED_FACE('F1062',(#2878),#2860,.F.);
#2880=CARTESIAN_POINT('',(-25.459026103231,71.755,28.187127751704));
#2881=DIRECTION('',(0.499999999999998,0.,0.86602540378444));
#2882=DIRECTION('',(0.86602540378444,0.,-0.499999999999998));
#2883=AXIS2_PLACEMENT_3D('',#2880,#2881,#2882);
#2884=PLANE('',#2883);
#2885=ORIENTED_EDGE('',*,*,#2574,.T.);
#2886=ORIENTED_EDGE('',*,*,#2875,.F.);
#2887=DIRECTION('',(0.86602540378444,0.,-0.499999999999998));
#2888=VECTOR('',#2887,1.);
#2889=CARTESIAN_POINT('',(-25.459026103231,71.755,28.187127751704));
#2890=LINE('',#2889,#2888);
#2891=EDGE_CURVE('E564',#2764,#2868,#2890,.T.);
#2892=ORIENTED_EDGE('',*,*,#2891,.F.);
#2893=ORIENTED_EDGE('',*,*,#2765,.T.);
#2894=EDGE_LOOP('',(#2885,#2886,#2892,#2893));
#2895=FACE_BOUND('',#2894,.T.);
#2896=ADVANCED_FACE('F1048',(#2895),#2884,.F.);
#2897=CARTESIAN_POINT('',(-25.459026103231,71.755,28.187127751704));
#2898=DIRECTION('',(0.,1.,0.));
#2899=DIRECTION('',(-1.,0.,0.));
#2900=AXIS2_PLACEMENT_3D('',#2897,#2898,#2899);
#2901=PLANE('',#2900);
#2902=ORIENTED_EDGE('',*,*,#2773,.T.);
#2903=ORIENTED_EDGE('',*,*,#2891,.T.);
#2904=ORIENTED_EDGE('',*,*,#2869,.T.);
#2905=ORIENTED_EDGE('',*,*,#2845,.T.);
#2906=ORIENTED_EDGE('',*,*,#2821,.T.);
#2907=ORIENTED_EDGE('',*,*,#2797,.T.);
#2908=EDGE_LOOP('',(#2902,#2903,#2904,#2905,#2906,#2907));
#2909=FACE_BOUND('',#2908,.T.);
#2910=ADVANCED_FACE('F1045',(#2909),#2901,.T.);
#2911=CARTESIAN_POINT('',(-26.8230769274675,71.755,-27.8216314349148));
#2912=DIRECTION('',(-0.866025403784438,0.,-0.500000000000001));
#2913=DIRECTION('',(-0.500000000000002,0.,0.866025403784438));
#2914=AXIS2_PLACEMENT_3D('',#2911,#2912,#2913);
#2915=PLANE('',#2914);
#2916=ORIENTED_EDGE('',*,*,#2623,.T.);
#2917=DIRECTION('',(0.,1.,0.));
#2918=VECTOR('',#2917,1.);
#2919=CARTESIAN_POINT('',(-28.1871277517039,71.755,-25.4590261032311));
#2920=LINE('',#2919,#2918);
#2921=CARTESIAN_POINT('',(-28.1871277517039,71.755,-25.4590261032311));
#2922=VERTEX_POINT('',#2921);
#2923=EDGE_CURVE('E520',#2922,#2622,#2920,.T.);
#2924=ORIENTED_EDGE('',*,*,#2923,.F.);
#2925=DIRECTION('',(-0.500000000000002,0.,0.866025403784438));
#2926=VECTOR('',#2925,1.);
#2927=CARTESIAN_POINT('',(-26.8230769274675,71.755,-27.8216314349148));
#2928=LINE('',#2927,#2926);
#2929=CARTESIAN_POINT('',(-26.8230769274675,71.755,-27.8216314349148));
#2930=VERTEX_POINT('',#2929);
#2931=EDGE_CURVE('E496',#2930,#2922,#2928,.T.);
#2932=ORIENTED_EDGE('',*,*,#2931,.F.);
#2933=DIRECTION('',(0.,1.,0.));
#2934=VECTOR('',#2933,1.);
#2935=CARTESIAN_POINT('',(-26.8230769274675,71.755,-27.8216314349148));
#2936=LINE('',#2935,#2934);
#2937=EDGE_CURVE('E542',#2930,#2620,#2936,.T.);
#2938=ORIENTED_EDGE('',*,*,#2937,.T.);
#2939=EDGE_LOOP('',(#2916,#2924,#2932,#2938));
#2940=FACE_BOUND('',#2939,.T.);
#2941=ADVANCED_FACE('F1027',(#2940),#2915,.F.);
#2942=CARTESIAN_POINT('',(-24.0949752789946,71.755,-27.8216314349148));
#2943=DIRECTION('',(0.,0.,-1.));
#2944=DIRECTION('',(-1.,0.,0.));
#2945=AXIS2_PLACEMENT_3D('',#2942,#2943,#2944);
#2946=PLANE('',#2945);
#2947=ORIENTED_EDGE('',*,*,#2631,.T.);
#2948=ORIENTED_EDGE('',*,*,#2937,.F.);
#2949=DIRECTION('',(-1.,0.,0.));
#2950=VECTOR('',#2949,1.);
#2951=CARTESIAN_POINT('',(-24.0949752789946,71.755,-27.8216314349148));
#2952=LINE('',#2951,#2950);
#2953=CARTESIAN_POINT('',(-24.0949752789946,71.755,-27.8216314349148));
#2954=VERTEX_POINT('',#2953);
#2955=EDGE_CURVE('E516',#2954,#2930,#2952,.T.);
#2956=ORIENTED_EDGE('',*,*,#2955,.F.);
#2957=DIRECTION('',(0.,1.,0.));
#2958=VECTOR('',#2957,1.);
#2959=CARTESIAN_POINT('',(-24.0949752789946,71.755,-27.8216314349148));
#2960=LINE('',#2959,#2958);
#2961=EDGE_CURVE('E546',#2954,#2630,#2960,.T.);
#2962=ORIENTED_EDGE('',*,*,#2961,.T.);
#2963=EDGE_LOOP('',(#2947,#2948,#2956,#2962));
#2964=FACE_BOUND('',#2963,.T.);
#2965=ADVANCED_FACE('F1023',(#2964),#2946,.F.);
#2966=CARTESIAN_POINT('',(-22.7309244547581,71.755,-25.4590261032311));
#2967=DIRECTION('',(0.866025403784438,0.,-0.500000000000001));
#2968=DIRECTION('',(-0.500000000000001,0.,-0.866025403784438));
#2969=AXIS2_PLACEMENT_3D('',#2966,#2967,#2968);
#2970=PLANE('',#2969);
#2971=ORIENTED_EDGE('',*,*,#2639,.T.);
#2972=ORIENTED_EDGE('',*,*,#2961,.F.);
#2973=DIRECTION('',(-0.500000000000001,0.,-0.866025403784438));
#2974=VECTOR('',#2973,1.);
#2975=CARTESIAN_POINT('',(-22.7309244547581,71.755,-25.4590261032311));
#2976=LINE('',#2975,#2974);
#2977=CARTESIAN_POINT('',(-22.7309244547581,71.755,-25.4590261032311));
#2978=VERTEX_POINT('',#2977);
#2979=EDGE_CURVE('E513',#2978,#2954,#2976,.T.);
#2980=ORIENTED_EDGE('',*,*,#2979,.F.);
#2981=DIRECTION('',(0.,1.,0.));
#2982=VECTOR('',#2981,1.);
#2983=CARTESIAN_POINT('',(-22.7309244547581,71.755,-25.4590261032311));
#2984=LINE('',#2983,#2982);
#2985=EDGE_CURVE('E549',#2978,#2638,#2984,.T.);
#2986=ORIENTED_EDGE('',*,*,#2985,.T.);
#2987=EDGE_LOOP('',(#2971,#2972,#2980,#2986));
#2988=FACE_BOUND('',#2987,.T.);
#2989=ADVANCED_FACE('F1026',(#2988),#2970,.F.);
#2990=CARTESIAN_POINT('',(-24.0949752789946,71.755,-23.0964207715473));
#2991=DIRECTION('',(0.866025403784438,0.,0.500000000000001));
#2992=DIRECTION('',(0.500000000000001,0.,-0.866025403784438));
#2993=AXIS2_PLACEMENT_3D('',#2990,#2991,#2992);
#2994=PLANE('',#2993);
#2995=ORIENTED_EDGE('',*,*,#2647,.T.);
#2996=ORIENTED_EDGE('',*,*,#2985,.F.);
#2997=DIRECTION('',(0.500000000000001,0.,-0.866025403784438));
#2998=VECTOR('',#2997,1.);
#2999=CARTESIAN_POINT('',(-24.0949752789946,71.755,-23.0964207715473));
#3000=LINE('',#2999,#2998);
#3001=CARTESIAN_POINT('',(-24.0949752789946,71.755,-23.0964207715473));
#3002=VERTEX_POINT('',#3001);
#3003=EDGE_CURVE('E509',#3002,#2978,#3000,.T.);
#3004=ORIENTED_EDGE('',*,*,#3003,.F.);
#3005=DIRECTION('',(0.,1.,0.));
#3006=VECTOR('',#3005,1.);
#3007=CARTESIAN_POINT('',(-24.0949752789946,71.755,-23.0964207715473));
#3008=LINE('',#3007,#3006);
#3009=EDGE_CURVE('E552',#3002,#2646,#3008,.T.);
#3010=ORIENTED_EDGE('',*,*,#3009,.T.);
#3011=EDGE_LOOP('',(#2995,#2996,#3004,#3010));
#3012=FACE_BOUND('',#3011,.T.);
#3013=ADVANCED_FACE('F1031',(#3012),#2994,.F.);
#3014=CARTESIAN_POINT('',(-26.8230769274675,71.755,-23.0964207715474));
#3015=DIRECTION('',(0.,0.,1.));
#3016=DIRECTION('',(1.,0.,0.));
#3017=AXIS2_PLACEMENT_3D('',#3014,#3015,#3016);
#3018=PLANE('',#3017);
#3019=ORIENTED_EDGE('',*,*,#2655,.T.);
#3020=ORIENTED_EDGE('',*,*,#3009,.F.);
#3021=DIRECTION('',(1.,0.,0.));
#3022=VECTOR('',#3021,1.);
#3023=CARTESIAN_POINT('',(-26.8230769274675,71.755,-23.0964207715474));
#3024=LINE('',#3023,#3022);
#3025=CARTESIAN_POINT('',(-26.8230769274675,71.755,-23.0964207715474));
#3026=VERTEX_POINT('',#3025);
#3027=EDGE_CURVE('E505',#3026,#3002,#3024,.T.);
#3028=ORIENTED_EDGE('',*,*,#3027,.F.);
#3029=DIRECTION('',(0.,1.,0.));
#3030=VECTOR('',#3029,1.);
#3031=CARTESIAN_POINT('',(-26.8230769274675,71.755,-23.0964207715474));
#3032=LINE('',#3031,#3030);
#3033=EDGE_CURVE('E555',#3026,#2654,#3032,.T.);
#3034=ORIENTED_EDGE('',*,*,#3033,.T.);
#3035=EDGE_LOOP('',(#3019,#3020,#3028,#3034));
#3036=FACE_BOUND('',#3035,.T.);
#3037=ADVANCED_FACE('F1035',(#3036),#3018,.F.);
#3038=CARTESIAN_POINT('',(-28.1871277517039,71.755,-25.4590261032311));
#3039=DIRECTION('',(-0.866025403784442,0.,0.499999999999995));
#3040=DIRECTION('',(0.499999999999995,0.,0.866025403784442));
#3041=AXIS2_PLACEMENT_3D('',#3038,#3039,#3040);
#3042=PLANE('',#3041);
#3043=ORIENTED_EDGE('',*,*,#2661,.T.);
#3044=ORIENTED_EDGE('',*,*,#3033,.F.);
#3045=DIRECTION('',(0.499999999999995,0.,0.866025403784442));
#3046=VECTOR('',#3045,1.);
#3047=CARTESIAN_POINT('',(-28.1871277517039,71.755,-25.4590261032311));
#3048=LINE('',#3047,#3046);
#3049=EDGE_CURVE('E500',#2922,#3026,#3048,.T.);
#3050=ORIENTED_EDGE('',*,*,#3049,.F.);
#3051=ORIENTED_EDGE('',*,*,#2923,.T.);
#3052=EDGE_LOOP('',(#3043,#3044,#3050,#3051));
#3053=FACE_BOUND('',#3052,.T.);
#3054=ADVANCED_FACE('F1021',(#3053),#3042,.F.);
#3055=CARTESIAN_POINT('',(-28.1871277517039,71.755,-25.4590261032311));
#3056=DIRECTION('',(0.,1.,0.));
#3057=DIRECTION('',(0.,0.,-1.));
#3058=AXIS2_PLACEMENT_3D('',#3055,#3056,#3057);
#3059=PLANE('',#3058);
#3060=ORIENTED_EDGE('',*,*,#2931,.T.);
#3061=ORIENTED_EDGE('',*,*,#3049,.T.);
#3062=ORIENTED_EDGE('',*,*,#3027,.T.);
#3063=ORIENTED_EDGE('',*,*,#3003,.T.);
#3064=ORIENTED_EDGE('',*,*,#2979,.T.);
#3065=ORIENTED_EDGE('',*,*,#2955,.T.);
#3066=EDGE_LOOP('',(#3060,#3061,#3062,#3063,#3064,#3065));
#3067=FACE_BOUND('',#3066,.T.);
#3068=ADVANCED_FACE('F1018',(#3067),#3059,.T.);
#3069=CARTESIAN_POINT('',(27.8216314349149,71.755,-26.8230769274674));
#3070=DIRECTION('',(0.500000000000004,0.,-0.866025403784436));
#3071=DIRECTION('',(-0.866025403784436,0.,-0.500000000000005));
#3072=AXIS2_PLACEMENT_3D('',#3069,#3070,#3071);
#3073=PLANE('',#3072);
#3074=ORIENTED_EDGE('',*,*,#2710,.T.);
#3075=DIRECTION('',(0.,1.,0.));
#3076=VECTOR('',#3075,1.);
#3077=CARTESIAN_POINT('',(25.4590261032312,71.755,-28.1871277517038));
#3078=LINE('',#3077,#3076);
#3079=CARTESIAN_POINT('',(25.4590261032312,71.755,-28.1871277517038));
#3080=VERTEX_POINT('',#3079);
#3081=EDGE_CURVE('E457',#3080,#2709,#3078,.T.);
#3082=ORIENTED_EDGE('',*,*,#3081,.F.);
#3083=DIRECTION('',(-0.866025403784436,0.,-0.500000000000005));
#3084=VECTOR('',#3083,1.);
#3085=CARTESIAN_POINT('',(27.8216314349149,71.755,-26.8230769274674));
#3086=LINE('',#3085,#3084);
#3087=CARTESIAN_POINT('',(27.8216314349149,71.755,-26.8230769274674));
#3088=VERTEX_POINT('',#3087);
#3089=EDGE_CURVE('E432',#3088,#3080,#3086,.T.);
#3090=ORIENTED_EDGE('',*,*,#3089,.F.);
#3091=DIRECTION('',(0.,1.,0.));
#3092=VECTOR('',#3091,1.);
#3093=CARTESIAN_POINT('',(27.8216314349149,71.755,-26.8230769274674));
#3094=LINE('',#3093,#3092);
#3095=EDGE_CURVE('E479',#3088,#2707,#3094,.T.);
#3096=ORIENTED_EDGE('',*,*,#3095,.T.);
#3097=EDGE_LOOP('',(#3074,#3082,#3090,#3096));
#3098=FACE_BOUND('',#3097,.T.);
#3099=ADVANCED_FACE('F1000',(#3098),#3073,.F.);
#3100=CARTESIAN_POINT('',(27.8216314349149,71.755,-24.0949752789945));
#3101=DIRECTION('',(1.,0.,0.));
#3102=DIRECTION('',(0.,0.,-1.));
#3103=AXIS2_PLACEMENT_3D('',#3100,#3101,#3102);
#3104=PLANE('',#3103);
#3105=ORIENTED_EDGE('',*,*,#2718,.T.);
#3106=ORIENTED_EDGE('',*,*,#3095,.F.);
#3107=DIRECTION('',(0.,0.,-1.));
#3108=VECTOR('',#3107,1.);
#3109=CARTESIAN_POINT('',(27.8216314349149,71.755,-24.0949752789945));
#3110=LINE('',#3109,#3108);
#3111=CARTESIAN_POINT('',(27.8216314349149,71.755,-24.0949752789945));
#3112=VERTEX_POINT('',#3111);
#3113=EDGE_CURVE('E453',#3112,#3088,#3110,.T.);
#3114=ORIENTED_EDGE('',*,*,#3113,.F.);
#3115=DIRECTION('',(0.,1.,0.));
#3116=VECTOR('',#3115,1.);
#3117=CARTESIAN_POINT('',(27.8216314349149,71.755,-24.0949752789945));
#3118=LINE('',#3117,#3116);
#3119=EDGE_CURVE('E482',#3112,#2717,#3118,.T.);
#3120=ORIENTED_EDGE('',*,*,#3119,.T.);
#3121=EDGE_LOOP('',(#3105,#3106,#3114,#3120));
#3122=FACE_BOUND('',#3121,.T.);
#3123=ADVANCED_FACE('F996',(#3122),#3104,.F.);
#3124=CARTESIAN_POINT('',(25.4590261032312,71.755,-22.730924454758));
#3125=DIRECTION('',(0.499999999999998,0.,0.86602540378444));
#3126=DIRECTION('',(0.86602540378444,0.,-0.499999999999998));
#3127=AXIS2_PLACEMENT_3D('',#3124,#3125,#3126);
#3128=PLANE('',#3127);
#3129=ORIENTED_EDGE('',*,*,#2726,.T.);
#3130=ORIENTED_EDGE('',*,*,#3119,.F.);
#3131=DIRECTION('',(0.86602540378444,0.,-0.499999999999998));
#3132=VECTOR('',#3131,1.);
#3133=CARTESIAN_POINT('',(25.4590261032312,71.755,-22.730924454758));
#3134=LINE('',#3133,#3132);
#3135=CARTESIAN_POINT('',(25.4590261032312,71.755,-22.730924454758));
#3136=VERTEX_POINT('',#3135);
#3137=EDGE_CURVE('E449',#3136,#3112,#3134,.T.);
#3138=ORIENTED_EDGE('',*,*,#3137,.F.);
#3139=DIRECTION('',(0.,1.,0.));
#3140=VECTOR('',#3139,1.);
#3141=CARTESIAN_POINT('',(25.4590261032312,71.755,-22.730924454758));
#3142=LINE('',#3141,#3140);
#3143=EDGE_CURVE('E485',#3136,#2725,#3142,.T.);
#3144=ORIENTED_EDGE('',*,*,#3143,.T.);
#3145=EDGE_LOOP('',(#3129,#3130,#3138,#3144));
#3146=FACE_BOUND('',#3145,.T.);
#3147=ADVANCED_FACE('F999',(#3146),#3128,.F.);
#3148=CARTESIAN_POINT('',(23.0964207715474,71.755,-24.0949752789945));
#3149=DIRECTION('',(-0.500000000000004,0.,0.866025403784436));
#3150=DIRECTION('',(0.866025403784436,0.,0.500000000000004));
#3151=AXIS2_PLACEMENT_3D('',#3148,#3149,#3150);
#3152=PLANE('',#3151);
#3153=ORIENTED_EDGE('',*,*,#2734,.T.);
#3154=ORIENTED_EDGE('',*,*,#3143,.F.);
#3155=DIRECTION('',(0.866025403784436,0.,0.500000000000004));
#3156=VECTOR('',#3155,1.);
#3157=CARTESIAN_POINT('',(23.0964207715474,71.755,-24.0949752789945));
#3158=LINE('',#3157,#3156);
#3159=CARTESIAN_POINT('',(23.0964207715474,71.755,-24.0949752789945));
#3160=VERTEX_POINT('',#3159);
#3161=EDGE_CURVE('E445',#3160,#3136,#3158,.T.);
#3162=ORIENTED_EDGE('',*,*,#3161,.F.);
#3163=DIRECTION('',(0.,1.,0.));
#3164=VECTOR('',#3163,1.);
#3165=CARTESIAN_POINT('',(23.0964207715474,71.755,-24.0949752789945));
#3166=LINE('',#3165,#3164);
#3167=EDGE_CURVE('E488',#3160,#2733,#3166,.T.);
#3168=ORIENTED_EDGE('',*,*,#3167,.T.);
#3169=EDGE_LOOP('',(#3153,#3154,#3162,#3168));
#3170=FACE_BOUND('',#3169,.T.);
#3171=ADVANCED_FACE('F1004',(#3170),#3152,.F.);
#3172=CARTESIAN_POINT('',(23.0964207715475,71.755,-26.8230769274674));
#3173=DIRECTION('',(-1.,0.,0.));
#3174=DIRECTION('',(0.,0.,1.));
#3175=AXIS2_PLACEMENT_3D('',#3172,#3173,#3174);
#3176=PLANE('',#3175);
#3177=ORIENTED_EDGE('',*,*,#2742,.T.);
#3178=ORIENTED_EDGE('',*,*,#3167,.F.);
#3179=DIRECTION('',(0.,0.,1.));
#3180=VECTOR('',#3179,1.);
#3181=CARTESIAN_POINT('',(23.0964207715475,71.755,-26.8230769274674));
#3182=LINE('',#3181,#3180);
#3183=CARTESIAN_POINT('',(23.0964207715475,71.755,-26.8230769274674));
#3184=VERTEX_POINT('',#3183);
#3185=EDGE_CURVE('E441',#3184,#3160,#3182,.T.);
#3186=ORIENTED_EDGE('',*,*,#3185,.F.);
#3187=DIRECTION('',(0.,1.,0.));
#3188=VECTOR('',#3187,1.);
#3189=CARTESIAN_POINT('',(23.0964207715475,71.755,-26.8230769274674));
#3190=LINE('',#3189,#3188);
#3191=EDGE_CURVE('E491',#3184,#2741,#3190,.T.);
#3192=ORIENTED_EDGE('',*,*,#3191,.T.);
#3193=EDGE_LOOP('',(#3177,#3178,#3186,#3192));
#3194=FACE_BOUND('',#3193,.T.);
#3195=ADVANCED_FACE('F1008',(#3194),#3176,.F.);
#3196=CARTESIAN_POINT('',(25.4590261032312,71.755,-28.1871277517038));
#3197=DIRECTION('',(-0.499999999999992,0.,-0.866025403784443));
#3198=DIRECTION('',(-0.866025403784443,0.,0.499999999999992));
#3199=AXIS2_PLACEMENT_3D('',#3196,#3197,#3198);
#3200=PLANE('',#3199);
#3201=ORIENTED_EDGE('',*,*,#2748,.T.);
#3202=ORIENTED_EDGE('',*,*,#3191,.F.);
#3203=DIRECTION('',(-0.866025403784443,0.,0.499999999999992));
#3204=VECTOR('',#3203,1.);
#3205=CARTESIAN_POINT('',(25.4590261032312,71.755,-28.1871277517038));
#3206=LINE('',#3205,#3204);
#3207=EDGE_CURVE('E436',#3080,#3184,#3206,.T.);
#3208=ORIENTED_EDGE('',*,*,#3207,.F.);
#3209=ORIENTED_EDGE('',*,*,#3081,.T.);
#3210=EDGE_LOOP('',(#3201,#3202,#3208,#3209));
#3211=FACE_BOUND('',#3210,.T.);
#3212=ADVANCED_FACE('F994',(#3211),#3200,.F.);
#3213=CARTESIAN_POINT('',(25.4590261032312,71.755,-28.1871277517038));
#3214=DIRECTION('',(0.,1.,0.));
#3215=DIRECTION('',(1.,0.,0.));
#3216=AXIS2_PLACEMENT_3D('',#3213,#3214,#3215);
#3217=PLANE('',#3216);
#3218=ORIENTED_EDGE('',*,*,#3089,.T.);
#3219=ORIENTED_EDGE('',*,*,#3207,.T.);
#3220=ORIENTED_EDGE('',*,*,#3185,.T.);
#3221=ORIENTED_EDGE('',*,*,#3161,.T.);
#3222=ORIENTED_EDGE('',*,*,#3137,.T.);
#3223=ORIENTED_EDGE('',*,*,#3113,.T.);
#3224=EDGE_LOOP('',(#3218,#3219,#3220,#3221,#3222,#3223));
#3225=FACE_BOUND('',#3224,.T.);
#3226=ADVANCED_FACE('F990',(#3225),#3217,.T.);
#3227=CARTESIAN_POINT('',(-25.459026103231,74.93,-25.4590261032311));
#3228=DIRECTION('',(0.,-1.,0.));
#3229=DIRECTION('',(0.,0.,-1.));
#3230=AXIS2_PLACEMENT_3D('',#3227,#3228,#3229);
#3231=CONICAL_SURFACE('',#3230,4.00050000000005,0.785398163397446);
#3232=ORIENTED_EDGE('',*,*,#2591,.F.);
#3233=EDGE_LOOP('',(#3232));
#3234=FACE_BOUND('',#3233,.T.);
#3235=ORIENTED_EDGE('',*,*,#2611,.F.);
#3236=EDGE_LOOP('',(#3235));
#3237=FACE_BOUND('',#3236,.T.);
#3238=ADVANCED_FACE('F993',(#3234,#3237),#3231,.T.);
#3239=CARTESIAN_POINT('',(25.4590261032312,74.93,-25.4590261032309));
#3240=DIRECTION('',(0.,-1.,0.));
#3241=DIRECTION('',(0.,0.,-1.));
#3242=AXIS2_PLACEMENT_3D('',#3239,#3240,#3241);
#3243=CONICAL_SURFACE('',#3242,4.00050000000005,0.785398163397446);
#3244=ORIENTED_EDGE('',*,*,#2678,.F.);
#3245=EDGE_LOOP('',(#3244));
#3246=FACE_BOUND('',#3245,.T.);
#3247=ORIENTED_EDGE('',*,*,#2698,.F.);
#3248=EDGE_LOOP('',(#3247));
#3249=FACE_BOUND('',#3248,.T.);
#3250=ADVANCED_FACE('F1602',(#3246,#3249),#3243,.T.);
#3251=CARTESIAN_POINT('',(25.4590261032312,74.93,25.4590261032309));
#3252=DIRECTION('',(0.,-1.,0.));
#3253=DIRECTION('',(0.,0.,-1.));
#3254=AXIS2_PLACEMENT_3D('',#3251,#3252,#3253);
#3255=CONICAL_SURFACE('',#3254,4.00050000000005,0.785398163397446);
#3256=ORIENTED_EDGE('',*,*,#2259,.F.);
#3257=EDGE_LOOP('',(#3256));
#3258=FACE_BOUND('',#3257,.T.);
#3259=ORIENTED_EDGE('',*,*,#2279,.F.);
#3260=EDGE_LOOP('',(#3259));
#3261=FACE_BOUND('',#3260,.T.);
#3262=ADVANCED_FACE('F1605',(#3258,#3261),#3255,.T.);
#3263=CARTESIAN_POINT('',(-25.459026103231,74.93,25.4590261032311));
#3264=DIRECTION('',(0.,-1.,0.));
#3265=DIRECTION('',(0.,0.,-1.));
#3266=AXIS2_PLACEMENT_3D('',#3263,#3264,#3265);
#3267=CONICAL_SURFACE('',#3266,4.00050000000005,0.785398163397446);
#3268=ORIENTED_EDGE('',*,*,#2504,.F.);
#3269=EDGE_LOOP('',(#3268));
#3270=FACE_BOUND('',#3269,.T.);
#3271=ORIENTED_EDGE('',*,*,#2524,.F.);
#3272=EDGE_LOOP('',(#3271));
#3273=FACE_BOUND('',#3272,.T.);
#3274=ADVANCED_FACE('F39',(#3270,#3273),#3267,.T.);
#3275=CARTESIAN_POINT('',(0.,27.432,43.815));
#3276=DIRECTION('',(0.,0.,1.));
#3277=DIRECTION('',(1.,0.,0.));
#3278=AXIS2_PLACEMENT_3D('',#3275,#3276,#3277);
#3279=CONICAL_SURFACE('',#3278,13.2191265,0.0312064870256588);
#3280=CARTESIAN_POINT('',(0.,27.432,27.559));
#3281=DIRECTION('',(0.,0.,1.));
#3282=DIRECTION('',(1.,0.,0.));
#3283=AXIS2_PLACEMENT_3D('',#3280,#3281,#3282);
#3284=CIRCLE('',#3283,12.7116691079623);
#3285=CARTESIAN_POINT('',(12.7116691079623,27.432,27.559));
#3286=VERTEX_POINT('',#3285);
#3287=EDGE_CURVE('E410',#3286,#3286,#3284,.T.);
#3288=ORIENTED_EDGE('',*,*,#3287,.F.);
#3289=EDGE_LOOP('',(#3288));
#3290=FACE_BOUND('',#3289,.T.);
#3291=ORIENTED_EDGE('',*,*,#1006,.F.);
#3292=EDGE_LOOP('',(#3291));
#3293=FACE_BOUND('',#3292,.T.);
#3294=ADVANCED_FACE('F972',(#3290,#3293),#3279,.F.);
#3295=CARTESIAN_POINT('',(0.,27.432,18.415));
#3296=DIRECTION('',(0.,0.,1.));
#3297=DIRECTION('',(1.,0.,0.));
#3298=AXIS2_PLACEMENT_3D('',#3295,#3296,#3297);
#3299=CONICAL_SURFACE('',#3298,11.5,1.17809724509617);
#3300=CARTESIAN_POINT('',(0.,27.432,13.6515440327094));
#3301=VERTEX_POINT('',#3300);
#3302=VERTEX_LOOP('',#3301);
#3303=FACE_BOUND('',#3302,.T.);
#3304=CARTESIAN_POINT('',(0.,27.432,18.415));
#3305=DIRECTION('',(0.,0.,1.));
#3306=DIRECTION('',(1.,0.,0.));
#3307=AXIS2_PLACEMENT_3D('',#3304,#3305,#3306);
#3308=CIRCLE('',#3307,11.5);
#3309=CARTESIAN_POINT('',(11.5,27.432,18.415));
#3310=VERTEX_POINT('',#3309);
#3311=EDGE_CURVE('E428',#3310,#3310,#3308,.T.);
#3312=ORIENTED_EDGE('',*,*,#3311,.T.);
#3313=EDGE_LOOP('',(#3312));
#3314=FACE_BOUND('',#3313,.T.);
#3315=ADVANCED_FACE('F976',(#3303,#3314),#3299,.F.);
#3316=CARTESIAN_POINT('',(0.,27.432,43.815));
#3317=DIRECTION('',(0.,0.,1.));
#3318=DIRECTION('',(1.,0.,0.));
#3319=AXIS2_PLACEMENT_3D('',#3316,#3317,#3318);
#3320=CYLINDRICAL_SURFACE('',#3319,11.5);
#3321=ORIENTED_EDGE('',*,*,#3311,.F.);
#3322=EDGE_LOOP('',(#3321));
#3323=FACE_BOUND('',#3322,.T.);
#3324=CARTESIAN_POINT('',(0.,27.432,27.559));
#3325=DIRECTION('',(0.,0.,1.));
#3326=DIRECTION('',(1.,0.,0.));
#3327=AXIS2_PLACEMENT_3D('',#3324,#3325,#3326);
#3328=CIRCLE('',#3327,11.5);
#3329=CARTESIAN_POINT('',(11.5,27.432,27.559));
#3330=VERTEX_POINT('',#3329);
#3331=EDGE_CURVE('E417',#3330,#3330,#3328,.T.);
#3332=ORIENTED_EDGE('',*,*,#3331,.T.);
#3333=EDGE_LOOP('',(#3332));
#3334=FACE_BOUND('',#3333,.T.);
#3335=ADVANCED_FACE('F982',(#3323,#3334),#3320,.F.);
#3336=CARTESIAN_POINT('',(11.5,27.432,27.559));
#3337=DIRECTION('',(0.,0.,-1.));
#3338=DIRECTION('',(-1.,0.,0.));
#3339=AXIS2_PLACEMENT_3D('',#3336,#3337,#3338);
#3340=PLANE('',#3339);
#3341=ORIENTED_EDGE('',*,*,#3331,.F.);
#3342=EDGE_LOOP('',(#3341));
#3343=FACE_BOUND('',#3342,.T.);
#3344=ORIENTED_EDGE('',*,*,#3287,.T.);
#3345=EDGE_LOOP('',(#3344));
#3346=FACE_BOUND('',#3345,.T.);
#3347=ADVANCED_FACE('F979',(#3343,#3346),#3340,.F.);
#3348=CARTESIAN_POINT('',(0.,27.432,-43.815));
#3349=DIRECTION('',(0.,0.,-1.));
#3350=DIRECTION('',(-1.,0.,0.));
#3351=AXIS2_PLACEMENT_3D('',#3348,#3349,#3350);
#3352=CONICAL_SURFACE('',#3351,13.2191265,0.0312064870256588);
#3353=CARTESIAN_POINT('',(0.,27.432,-27.559));
#3354=DIRECTION('',(0.,0.,-1.));
#3355=DIRECTION('',(-1.,0.,0.));
#3356=AXIS2_PLACEMENT_3D('',#3353,#3354,#3355);
#3357=CIRCLE('',#3356,12.7116691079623);
#3358=CARTESIAN_POINT('',(-12.7116691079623,27.432,-27.559));
#3359=VERTEX_POINT('',#3358);
#3360=EDGE_CURVE('E421',#3359,#3359,#3357,.T.);
#3361=ORIENTED_EDGE('',*,*,#3360,.F.);
#3362=EDGE_LOOP('',(#3361));
#3363=FACE_BOUND('',#3362,.T.);
#3364=ORIENTED_EDGE('',*,*,#845,.F.);
#3365=EDGE_LOOP('',(#3364));
#3366=FACE_BOUND('',#3365,.T.);
#3367=ADVANCED_FACE('F403',(#3363,#3366),#3352,.F.);
#3368=CARTESIAN_POINT('',(0.,27.432,-18.415));
#3369=DIRECTION('',(0.,0.,-1.));
#3370=DIRECTION('',(-1.,0.,0.));
#3371=AXIS2_PLACEMENT_3D('',#3368,#3369,#3370);
#3372=CONICAL_SURFACE('',#3371,11.5,1.17809724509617);
#3373=CARTESIAN_POINT('',(0.,27.432,-13.6515440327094));
#3374=VERTEX_POINT('',#3373);
#3375=VERTEX_LOOP('',#3374);
#3376=FACE_BOUND('',#3375,.T.);
#3377=CARTESIAN_POINT('',(0.,27.432,-18.415));
#3378=DIRECTION('',(0.,0.,-1.));
#3379=DIRECTION('',(-1.,0.,0.));
#3380=AXIS2_PLACEMENT_3D('',#3377,#3378,#3379);
#3381=CIRCLE('',#3380,11.5);
#3382=CARTESIAN_POINT('',(-11.5,27.432,-18.415));
#3383=VERTEX_POINT('',#3382);
#3384=EDGE_CURVE('E407',#3383,#3383,#3381,.T.);
#3385=ORIENTED_EDGE('',*,*,#3384,.T.);
#3386=EDGE_LOOP('',(#3385));
#3387=FACE_BOUND('',#3386,.T.);
#3388=ADVANCED_FACE('F399',(#3376,#3387),#3372,.F.);
#3389=CARTESIAN_POINT('',(0.,27.432,-43.815));
#3390=DIRECTION('',(0.,0.,-1.));
#3391=DIRECTION('',(-1.,0.,0.));
#3392=AXIS2_PLACEMENT_3D('',#3389,#3390,#3391);
#3393=CYLINDRICAL_SURFACE('',#3392,11.5);
#3394=ORIENTED_EDGE('',*,*,#3384,.F.);
#3395=EDGE_LOOP('',(#3394));
#3396=FACE_BOUND('',#3395,.T.);
#3397=CARTESIAN_POINT('',(0.,27.432,-27.559));
#3398=DIRECTION('',(0.,0.,-1.));
#3399=DIRECTION('',(-1.,0.,0.));
#3400=AXIS2_PLACEMENT_3D('',#3397,#3398,#3399);
#3401=CIRCLE('',#3400,11.5);
#3402=CARTESIAN_POINT('',(-11.5,27.432,-27.559));
#3403=VERTEX_POINT('',#3402);
#3404=EDGE_CURVE('E411',#3403,#3403,#3401,.T.);
#3405=ORIENTED_EDGE('',*,*,#3404,.T.);
#3406=EDGE_LOOP('',(#3405));
#3407=FACE_BOUND('',#3406,.T.);
#3408=ADVANCED_FACE('F402',(#3396,#3407),#3393,.F.);
#3409=CARTESIAN_POINT('',(11.5,27.432,-27.559));
#3410=DIRECTION('',(0.,0.,1.));
#3411=DIRECTION('',(1.,0.,0.));
#3412=AXIS2_PLACEMENT_3D('',#3409,#3410,#3411);
#3413=PLANE('',#3412);
#3414=ORIENTED_EDGE('',*,*,#3404,.F.);
#3415=EDGE_LOOP('',(#3414));
#3416=FACE_BOUND('',#3415,.T.);
#3417=ORIENTED_EDGE('',*,*,#3360,.T.);
#3418=EDGE_LOOP('',(#3417));
#3419=FACE_BOUND('',#3418,.T.);
#3420=ADVANCED_FACE('F2043',(#3416,#3419),#3413,.F.);
#3421=CLOSED_SHELL('',(#682,#1032,#1049,#1069,#1097,#1109,#1127,#1147,#1175,#1195,#1215,#1227,
#1239,#1259,#1312,#1324,#1356,#1380,#1405,#1422,#1434,#1450,#1499,#1557,#1574,#1591,#1608,#1625,
#1637,#1653,#1702,#1718,#1767,#1783,#1832,#1890,#1907,#1924,#1941,#1958,#1970,#2028,#2045,#2062,
#2079,#2096,#2108,#2166,#2183,#2200,#2217,#2234,#2246,#2266,#2333,#2364,#2388,#2412,#2436,#2460,
#2477,#2491,#2511,#2578,#2598,#2665,#2685,#2752,#2783,#2807,#2831,#2855,#2879,#2896,#2910,#2941,
#2965,#2989,#3013,#3037,#3054,#3068,#3099,#3123,#3147,#3171,#3195,#3212,#3226,#3238,#3250,#3262,
#3274,#3294,#3315,#3335,#3347,#3367,#3388,#3408,#3420));
#3422=MANIFOLD_SOLID_BREP('B2',#3421);
#3423=ADVANCED_BREP_SHAPE_REPRESENTATION('',(#18,#3422),#14);
#3424=SHAPE_DEFINITION_REPRESENTATION(#9,#3423);
ENDSEC;
END-ISO-10303-21;
